# OpenTallas tools/mem_compiler/ucie_pma_gen.py: HBM host UCIe analog PMA ABSTRACT ot_ucie_pma_rxm (assumed footprint/timing)
VERSION 5.7 ;
BUSBITCHARS "[]" ;
DIVIDERCHAR "/" ;
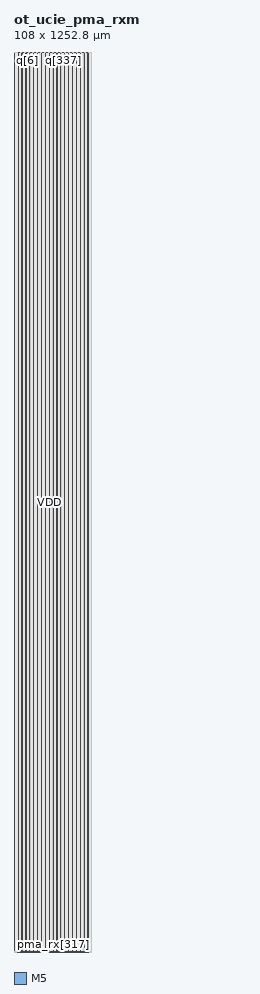
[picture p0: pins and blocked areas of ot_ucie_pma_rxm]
MACRO ot_ucie_pma_rxm
  FOREIGN ot_ucie_pma_rxm 0 0 ;
  SYMMETRY X Y ;
  SIZE 108.000 BY 1252.800 ;
  CLASS BLOCK ;
  PIN pma_rck
    DIRECTION INPUT ;
    USE CLOCK ;
    SHAPE ABUTMENT ;
    PORT
      LAYER M5 ;
      RECT 4.740 0.000 4.764 0.192 ;
    END
  END pma_rck
  PIN pma_rx[0]
    DIRECTION INPUT ;
    USE SIGNAL ;
    SHAPE ABUTMENT ;
    PORT
      LAYER M5 ;
      RECT 4.932 0.000 4.956 0.192 ;
    END
  END pma_rx[0]
  PIN pma_rx[1]
    DIRECTION INPUT ;
    USE SIGNAL ;
    SHAPE ABUTMENT ;
    PORT
      LAYER M5 ;
      RECT 5.124 0.000 5.148 0.192 ;
    END
  END pma_rx[1]
  PIN pma_rx[2]
    DIRECTION INPUT ;
    USE SIGNAL ;
    SHAPE ABUTMENT ;
    PORT
      LAYER M5 ;
      RECT 5.316 0.000 5.340 0.192 ;
    END
  END pma_rx[2]
  PIN pma_rx[3]
    DIRECTION INPUT ;
    USE SIGNAL ;
    SHAPE ABUTMENT ;
    PORT
      LAYER M5 ;
      RECT 5.508 0.000 5.532 0.192 ;
    END
  END pma_rx[3]
  PIN pma_rx[4]
    DIRECTION INPUT ;
    USE SIGNAL ;
    SHAPE ABUTMENT ;
    PORT
      LAYER M5 ;
      RECT 5.700 0.000 5.724 0.192 ;
    END
  END pma_rx[4]
  PIN pma_rx[5]
    DIRECTION INPUT ;
    USE SIGNAL ;
    SHAPE ABUTMENT ;
    PORT
      LAYER M5 ;
      RECT 5.892 0.000 5.916 0.192 ;
    END
  END pma_rx[5]
  PIN pma_rx[6]
    DIRECTION INPUT ;
    USE SIGNAL ;
    SHAPE ABUTMENT ;
    PORT
      LAYER M5 ;
      RECT 6.084 0.000 6.108 0.192 ;
    END
  END pma_rx[6]
  PIN pma_rx[7]
    DIRECTION INPUT ;
    USE SIGNAL ;
    SHAPE ABUTMENT ;
    PORT
      LAYER M5 ;
      RECT 6.276 0.000 6.300 0.192 ;
    END
  END pma_rx[7]
  PIN pma_rx[8]
    DIRECTION INPUT ;
    USE SIGNAL ;
    SHAPE ABUTMENT ;
    PORT
      LAYER M5 ;
      RECT 6.468 0.000 6.492 0.192 ;
    END
  END pma_rx[8]
  PIN pma_rx[9]
    DIRECTION INPUT ;
    USE SIGNAL ;
    SHAPE ABUTMENT ;
    PORT
      LAYER M5 ;
      RECT 6.660 0.000 6.684 0.192 ;
    END
  END pma_rx[9]
  PIN pma_rx[10]
    DIRECTION INPUT ;
    USE SIGNAL ;
    SHAPE ABUTMENT ;
    PORT
      LAYER M5 ;
      RECT 6.852 0.000 6.876 0.192 ;
    END
  END pma_rx[10]
  PIN pma_rx[11]
    DIRECTION INPUT ;
    USE SIGNAL ;
    SHAPE ABUTMENT ;
    PORT
      LAYER M5 ;
      RECT 7.044 0.000 7.068 0.192 ;
    END
  END pma_rx[11]
  PIN pma_rx[12]
    DIRECTION INPUT ;
    USE SIGNAL ;
    SHAPE ABUTMENT ;
    PORT
      LAYER M5 ;
      RECT 7.236 0.000 7.260 0.192 ;
    END
  END pma_rx[12]
  PIN pma_rx[13]
    DIRECTION INPUT ;
    USE SIGNAL ;
    SHAPE ABUTMENT ;
    PORT
      LAYER M5 ;
      RECT 7.428 0.000 7.452 0.192 ;
    END
  END pma_rx[13]
  PIN pma_rx[14]
    DIRECTION INPUT ;
    USE SIGNAL ;
    SHAPE ABUTMENT ;
    PORT
      LAYER M5 ;
      RECT 7.620 0.000 7.644 0.192 ;
    END
  END pma_rx[14]
  PIN pma_rx[15]
    DIRECTION INPUT ;
    USE SIGNAL ;
    SHAPE ABUTMENT ;
    PORT
      LAYER M5 ;
      RECT 7.812 0.000 7.836 0.192 ;
    END
  END pma_rx[15]
  PIN pma_rx[16]
    DIRECTION INPUT ;
    USE SIGNAL ;
    SHAPE ABUTMENT ;
    PORT
      LAYER M5 ;
      RECT 8.004 0.000 8.028 0.192 ;
    END
  END pma_rx[16]
  PIN pma_rx[17]
    DIRECTION INPUT ;
    USE SIGNAL ;
    SHAPE ABUTMENT ;
    PORT
      LAYER M5 ;
      RECT 8.196 0.000 8.220 0.192 ;
    END
  END pma_rx[17]
  PIN pma_rx[18]
    DIRECTION INPUT ;
    USE SIGNAL ;
    SHAPE ABUTMENT ;
    PORT
      LAYER M5 ;
      RECT 8.388 0.000 8.412 0.192 ;
    END
  END pma_rx[18]
  PIN pma_rx[19]
    DIRECTION INPUT ;
    USE SIGNAL ;
    SHAPE ABUTMENT ;
    PORT
      LAYER M5 ;
      RECT 8.580 0.000 8.604 0.192 ;
    END
  END pma_rx[19]
  PIN pma_rx[20]
    DIRECTION INPUT ;
    USE SIGNAL ;
    SHAPE ABUTMENT ;
    PORT
      LAYER M5 ;
      RECT 8.772 0.000 8.796 0.192 ;
    END
  END pma_rx[20]
  PIN pma_rx[21]
    DIRECTION INPUT ;
    USE SIGNAL ;
    SHAPE ABUTMENT ;
    PORT
      LAYER M5 ;
      RECT 8.964 0.000 8.988 0.192 ;
    END
  END pma_rx[21]
  PIN pma_rx[22]
    DIRECTION INPUT ;
    USE SIGNAL ;
    SHAPE ABUTMENT ;
    PORT
      LAYER M5 ;
      RECT 9.156 0.000 9.180 0.192 ;
    END
  END pma_rx[22]
  PIN pma_rx[23]
    DIRECTION INPUT ;
    USE SIGNAL ;
    SHAPE ABUTMENT ;
    PORT
      LAYER M5 ;
      RECT 9.348 0.000 9.372 0.192 ;
    END
  END pma_rx[23]
  PIN pma_rx[24]
    DIRECTION INPUT ;
    USE SIGNAL ;
    SHAPE ABUTMENT ;
    PORT
      LAYER M5 ;
      RECT 9.540 0.000 9.564 0.192 ;
    END
  END pma_rx[24]
  PIN pma_rx[25]
    DIRECTION INPUT ;
    USE SIGNAL ;
    SHAPE ABUTMENT ;
    PORT
      LAYER M5 ;
      RECT 9.732 0.000 9.756 0.192 ;
    END
  END pma_rx[25]
  PIN pma_rx[26]
    DIRECTION INPUT ;
    USE SIGNAL ;
    SHAPE ABUTMENT ;
    PORT
      LAYER M5 ;
      RECT 9.924 0.000 9.948 0.192 ;
    END
  END pma_rx[26]
  PIN pma_rx[27]
    DIRECTION INPUT ;
    USE SIGNAL ;
    SHAPE ABUTMENT ;
    PORT
      LAYER M5 ;
      RECT 10.116 0.000 10.140 0.192 ;
    END
  END pma_rx[27]
  PIN pma_rx[28]
    DIRECTION INPUT ;
    USE SIGNAL ;
    SHAPE ABUTMENT ;
    PORT
      LAYER M5 ;
      RECT 10.308 0.000 10.332 0.192 ;
    END
  END pma_rx[28]
  PIN pma_rx[29]
    DIRECTION INPUT ;
    USE SIGNAL ;
    SHAPE ABUTMENT ;
    PORT
      LAYER M5 ;
      RECT 10.500 0.000 10.524 0.192 ;
    END
  END pma_rx[29]
  PIN pma_rx[30]
    DIRECTION INPUT ;
    USE SIGNAL ;
    SHAPE ABUTMENT ;
    PORT
      LAYER M5 ;
      RECT 10.692 0.000 10.716 0.192 ;
    END
  END pma_rx[30]
  PIN pma_rx[31]
    DIRECTION INPUT ;
    USE SIGNAL ;
    SHAPE ABUTMENT ;
    PORT
      LAYER M5 ;
      RECT 10.884 0.000 10.908 0.192 ;
    END
  END pma_rx[31]
  PIN pma_rx[32]
    DIRECTION INPUT ;
    USE SIGNAL ;
    SHAPE ABUTMENT ;
    PORT
      LAYER M5 ;
      RECT 11.076 0.000 11.100 0.192 ;
    END
  END pma_rx[32]
  PIN pma_rx[33]
    DIRECTION INPUT ;
    USE SIGNAL ;
    SHAPE ABUTMENT ;
    PORT
      LAYER M5 ;
      RECT 11.268 0.000 11.292 0.192 ;
    END
  END pma_rx[33]
  PIN pma_rx[34]
    DIRECTION INPUT ;
    USE SIGNAL ;
    SHAPE ABUTMENT ;
    PORT
      LAYER M5 ;
      RECT 11.460 0.000 11.484 0.192 ;
    END
  END pma_rx[34]
  PIN pma_rx[35]
    DIRECTION INPUT ;
    USE SIGNAL ;
    SHAPE ABUTMENT ;
    PORT
      LAYER M5 ;
      RECT 11.652 0.000 11.676 0.192 ;
    END
  END pma_rx[35]
  PIN pma_rx[36]
    DIRECTION INPUT ;
    USE SIGNAL ;
    SHAPE ABUTMENT ;
    PORT
      LAYER M5 ;
      RECT 11.844 0.000 11.868 0.192 ;
    END
  END pma_rx[36]
  PIN pma_rx[37]
    DIRECTION INPUT ;
    USE SIGNAL ;
    SHAPE ABUTMENT ;
    PORT
      LAYER M5 ;
      RECT 12.036 0.000 12.060 0.192 ;
    END
  END pma_rx[37]
  PIN pma_rx[38]
    DIRECTION INPUT ;
    USE SIGNAL ;
    SHAPE ABUTMENT ;
    PORT
      LAYER M5 ;
      RECT 12.228 0.000 12.252 0.192 ;
    END
  END pma_rx[38]
  PIN pma_rx[39]
    DIRECTION INPUT ;
    USE SIGNAL ;
    SHAPE ABUTMENT ;
    PORT
      LAYER M5 ;
      RECT 12.420 0.000 12.444 0.192 ;
    END
  END pma_rx[39]
  PIN pma_rx[40]
    DIRECTION INPUT ;
    USE SIGNAL ;
    SHAPE ABUTMENT ;
    PORT
      LAYER M5 ;
      RECT 12.612 0.000 12.636 0.192 ;
    END
  END pma_rx[40]
  PIN pma_rx[41]
    DIRECTION INPUT ;
    USE SIGNAL ;
    SHAPE ABUTMENT ;
    PORT
      LAYER M5 ;
      RECT 12.804 0.000 12.828 0.192 ;
    END
  END pma_rx[41]
  PIN pma_rx[42]
    DIRECTION INPUT ;
    USE SIGNAL ;
    SHAPE ABUTMENT ;
    PORT
      LAYER M5 ;
      RECT 12.996 0.000 13.020 0.192 ;
    END
  END pma_rx[42]
  PIN pma_rx[43]
    DIRECTION INPUT ;
    USE SIGNAL ;
    SHAPE ABUTMENT ;
    PORT
      LAYER M5 ;
      RECT 13.188 0.000 13.212 0.192 ;
    END
  END pma_rx[43]
  PIN pma_rx[44]
    DIRECTION INPUT ;
    USE SIGNAL ;
    SHAPE ABUTMENT ;
    PORT
      LAYER M5 ;
      RECT 13.380 0.000 13.404 0.192 ;
    END
  END pma_rx[44]
  PIN pma_rx[45]
    DIRECTION INPUT ;
    USE SIGNAL ;
    SHAPE ABUTMENT ;
    PORT
      LAYER M5 ;
      RECT 13.572 0.000 13.596 0.192 ;
    END
  END pma_rx[45]
  PIN pma_rx[46]
    DIRECTION INPUT ;
    USE SIGNAL ;
    SHAPE ABUTMENT ;
    PORT
      LAYER M5 ;
      RECT 13.764 0.000 13.788 0.192 ;
    END
  END pma_rx[46]
  PIN pma_rx[47]
    DIRECTION INPUT ;
    USE SIGNAL ;
    SHAPE ABUTMENT ;
    PORT
      LAYER M5 ;
      RECT 13.956 0.000 13.980 0.192 ;
    END
  END pma_rx[47]
  PIN pma_rx[48]
    DIRECTION INPUT ;
    USE SIGNAL ;
    SHAPE ABUTMENT ;
    PORT
      LAYER M5 ;
      RECT 14.148 0.000 14.172 0.192 ;
    END
  END pma_rx[48]
  PIN pma_rx[49]
    DIRECTION INPUT ;
    USE SIGNAL ;
    SHAPE ABUTMENT ;
    PORT
      LAYER M5 ;
      RECT 14.340 0.000 14.364 0.192 ;
    END
  END pma_rx[49]
  PIN pma_rx[50]
    DIRECTION INPUT ;
    USE SIGNAL ;
    SHAPE ABUTMENT ;
    PORT
      LAYER M5 ;
      RECT 14.532 0.000 14.556 0.192 ;
    END
  END pma_rx[50]
  PIN pma_rx[51]
    DIRECTION INPUT ;
    USE SIGNAL ;
    SHAPE ABUTMENT ;
    PORT
      LAYER M5 ;
      RECT 14.724 0.000 14.748 0.192 ;
    END
  END pma_rx[51]
  PIN pma_rx[52]
    DIRECTION INPUT ;
    USE SIGNAL ;
    SHAPE ABUTMENT ;
    PORT
      LAYER M5 ;
      RECT 14.916 0.000 14.940 0.192 ;
    END
  END pma_rx[52]
  PIN pma_rx[53]
    DIRECTION INPUT ;
    USE SIGNAL ;
    SHAPE ABUTMENT ;
    PORT
      LAYER M5 ;
      RECT 15.108 0.000 15.132 0.192 ;
    END
  END pma_rx[53]
  PIN pma_rx[54]
    DIRECTION INPUT ;
    USE SIGNAL ;
    SHAPE ABUTMENT ;
    PORT
      LAYER M5 ;
      RECT 15.300 0.000 15.324 0.192 ;
    END
  END pma_rx[54]
  PIN pma_rx[55]
    DIRECTION INPUT ;
    USE SIGNAL ;
    SHAPE ABUTMENT ;
    PORT
      LAYER M5 ;
      RECT 15.492 0.000 15.516 0.192 ;
    END
  END pma_rx[55]
  PIN pma_rx[56]
    DIRECTION INPUT ;
    USE SIGNAL ;
    SHAPE ABUTMENT ;
    PORT
      LAYER M5 ;
      RECT 15.684 0.000 15.708 0.192 ;
    END
  END pma_rx[56]
  PIN pma_rx[57]
    DIRECTION INPUT ;
    USE SIGNAL ;
    SHAPE ABUTMENT ;
    PORT
      LAYER M5 ;
      RECT 15.876 0.000 15.900 0.192 ;
    END
  END pma_rx[57]
  PIN pma_rx[58]
    DIRECTION INPUT ;
    USE SIGNAL ;
    SHAPE ABUTMENT ;
    PORT
      LAYER M5 ;
      RECT 16.068 0.000 16.092 0.192 ;
    END
  END pma_rx[58]
  PIN pma_rx[59]
    DIRECTION INPUT ;
    USE SIGNAL ;
    SHAPE ABUTMENT ;
    PORT
      LAYER M5 ;
      RECT 16.260 0.000 16.284 0.192 ;
    END
  END pma_rx[59]
  PIN pma_rx[60]
    DIRECTION INPUT ;
    USE SIGNAL ;
    SHAPE ABUTMENT ;
    PORT
      LAYER M5 ;
      RECT 16.452 0.000 16.476 0.192 ;
    END
  END pma_rx[60]
  PIN pma_rx[61]
    DIRECTION INPUT ;
    USE SIGNAL ;
    SHAPE ABUTMENT ;
    PORT
      LAYER M5 ;
      RECT 16.644 0.000 16.668 0.192 ;
    END
  END pma_rx[61]
  PIN pma_rx[62]
    DIRECTION INPUT ;
    USE SIGNAL ;
    SHAPE ABUTMENT ;
    PORT
      LAYER M5 ;
      RECT 16.836 0.000 16.860 0.192 ;
    END
  END pma_rx[62]
  PIN pma_rx[63]
    DIRECTION INPUT ;
    USE SIGNAL ;
    SHAPE ABUTMENT ;
    PORT
      LAYER M5 ;
      RECT 17.028 0.000 17.052 0.192 ;
    END
  END pma_rx[63]
  PIN pma_rx[64]
    DIRECTION INPUT ;
    USE SIGNAL ;
    SHAPE ABUTMENT ;
    PORT
      LAYER M5 ;
      RECT 17.220 0.000 17.244 0.192 ;
    END
  END pma_rx[64]
  PIN pma_rx[65]
    DIRECTION INPUT ;
    USE SIGNAL ;
    SHAPE ABUTMENT ;
    PORT
      LAYER M5 ;
      RECT 17.412 0.000 17.436 0.192 ;
    END
  END pma_rx[65]
  PIN pma_rx[66]
    DIRECTION INPUT ;
    USE SIGNAL ;
    SHAPE ABUTMENT ;
    PORT
      LAYER M5 ;
      RECT 17.604 0.000 17.628 0.192 ;
    END
  END pma_rx[66]
  PIN pma_rx[67]
    DIRECTION INPUT ;
    USE SIGNAL ;
    SHAPE ABUTMENT ;
    PORT
      LAYER M5 ;
      RECT 17.796 0.000 17.820 0.192 ;
    END
  END pma_rx[67]
  PIN pma_rx[68]
    DIRECTION INPUT ;
    USE SIGNAL ;
    SHAPE ABUTMENT ;
    PORT
      LAYER M5 ;
      RECT 17.988 0.000 18.012 0.192 ;
    END
  END pma_rx[68]
  PIN pma_rx[69]
    DIRECTION INPUT ;
    USE SIGNAL ;
    SHAPE ABUTMENT ;
    PORT
      LAYER M5 ;
      RECT 18.180 0.000 18.204 0.192 ;
    END
  END pma_rx[69]
  PIN pma_rx[70]
    DIRECTION INPUT ;
    USE SIGNAL ;
    SHAPE ABUTMENT ;
    PORT
      LAYER M5 ;
      RECT 18.372 0.000 18.396 0.192 ;
    END
  END pma_rx[70]
  PIN pma_rx[71]
    DIRECTION INPUT ;
    USE SIGNAL ;
    SHAPE ABUTMENT ;
    PORT
      LAYER M5 ;
      RECT 18.564 0.000 18.588 0.192 ;
    END
  END pma_rx[71]
  PIN pma_rx[72]
    DIRECTION INPUT ;
    USE SIGNAL ;
    SHAPE ABUTMENT ;
    PORT
      LAYER M5 ;
      RECT 18.756 0.000 18.780 0.192 ;
    END
  END pma_rx[72]
  PIN pma_rx[73]
    DIRECTION INPUT ;
    USE SIGNAL ;
    SHAPE ABUTMENT ;
    PORT
      LAYER M5 ;
      RECT 18.948 0.000 18.972 0.192 ;
    END
  END pma_rx[73]
  PIN pma_rx[74]
    DIRECTION INPUT ;
    USE SIGNAL ;
    SHAPE ABUTMENT ;
    PORT
      LAYER M5 ;
      RECT 19.140 0.000 19.164 0.192 ;
    END
  END pma_rx[74]
  PIN pma_rx[75]
    DIRECTION INPUT ;
    USE SIGNAL ;
    SHAPE ABUTMENT ;
    PORT
      LAYER M5 ;
      RECT 19.332 0.000 19.356 0.192 ;
    END
  END pma_rx[75]
  PIN pma_rx[76]
    DIRECTION INPUT ;
    USE SIGNAL ;
    SHAPE ABUTMENT ;
    PORT
      LAYER M5 ;
      RECT 19.524 0.000 19.548 0.192 ;
    END
  END pma_rx[76]
  PIN pma_rx[77]
    DIRECTION INPUT ;
    USE SIGNAL ;
    SHAPE ABUTMENT ;
    PORT
      LAYER M5 ;
      RECT 19.716 0.000 19.740 0.192 ;
    END
  END pma_rx[77]
  PIN pma_rx[78]
    DIRECTION INPUT ;
    USE SIGNAL ;
    SHAPE ABUTMENT ;
    PORT
      LAYER M5 ;
      RECT 19.908 0.000 19.932 0.192 ;
    END
  END pma_rx[78]
  PIN pma_rx[79]
    DIRECTION INPUT ;
    USE SIGNAL ;
    SHAPE ABUTMENT ;
    PORT
      LAYER M5 ;
      RECT 20.100 0.000 20.124 0.192 ;
    END
  END pma_rx[79]
  PIN pma_rx[80]
    DIRECTION INPUT ;
    USE SIGNAL ;
    SHAPE ABUTMENT ;
    PORT
      LAYER M5 ;
      RECT 20.292 0.000 20.316 0.192 ;
    END
  END pma_rx[80]
  PIN pma_rx[81]
    DIRECTION INPUT ;
    USE SIGNAL ;
    SHAPE ABUTMENT ;
    PORT
      LAYER M5 ;
      RECT 20.484 0.000 20.508 0.192 ;
    END
  END pma_rx[81]
  PIN pma_rx[82]
    DIRECTION INPUT ;
    USE SIGNAL ;
    SHAPE ABUTMENT ;
    PORT
      LAYER M5 ;
      RECT 20.676 0.000 20.700 0.192 ;
    END
  END pma_rx[82]
  PIN pma_rx[83]
    DIRECTION INPUT ;
    USE SIGNAL ;
    SHAPE ABUTMENT ;
    PORT
      LAYER M5 ;
      RECT 20.868 0.000 20.892 0.192 ;
    END
  END pma_rx[83]
  PIN pma_rx[84]
    DIRECTION INPUT ;
    USE SIGNAL ;
    SHAPE ABUTMENT ;
    PORT
      LAYER M5 ;
      RECT 21.060 0.000 21.084 0.192 ;
    END
  END pma_rx[84]
  PIN pma_rx[85]
    DIRECTION INPUT ;
    USE SIGNAL ;
    SHAPE ABUTMENT ;
    PORT
      LAYER M5 ;
      RECT 21.252 0.000 21.276 0.192 ;
    END
  END pma_rx[85]
  PIN pma_rx[86]
    DIRECTION INPUT ;
    USE SIGNAL ;
    SHAPE ABUTMENT ;
    PORT
      LAYER M5 ;
      RECT 21.444 0.000 21.468 0.192 ;
    END
  END pma_rx[86]
  PIN pma_rx[87]
    DIRECTION INPUT ;
    USE SIGNAL ;
    SHAPE ABUTMENT ;
    PORT
      LAYER M5 ;
      RECT 21.636 0.000 21.660 0.192 ;
    END
  END pma_rx[87]
  PIN pma_rx[88]
    DIRECTION INPUT ;
    USE SIGNAL ;
    SHAPE ABUTMENT ;
    PORT
      LAYER M5 ;
      RECT 21.828 0.000 21.852 0.192 ;
    END
  END pma_rx[88]
  PIN pma_rx[89]
    DIRECTION INPUT ;
    USE SIGNAL ;
    SHAPE ABUTMENT ;
    PORT
      LAYER M5 ;
      RECT 22.020 0.000 22.044 0.192 ;
    END
  END pma_rx[89]
  PIN pma_rx[90]
    DIRECTION INPUT ;
    USE SIGNAL ;
    SHAPE ABUTMENT ;
    PORT
      LAYER M5 ;
      RECT 22.212 0.000 22.236 0.192 ;
    END
  END pma_rx[90]
  PIN pma_rx[91]
    DIRECTION INPUT ;
    USE SIGNAL ;
    SHAPE ABUTMENT ;
    PORT
      LAYER M5 ;
      RECT 22.404 0.000 22.428 0.192 ;
    END
  END pma_rx[91]
  PIN pma_rx[92]
    DIRECTION INPUT ;
    USE SIGNAL ;
    SHAPE ABUTMENT ;
    PORT
      LAYER M5 ;
      RECT 22.596 0.000 22.620 0.192 ;
    END
  END pma_rx[92]
  PIN pma_rx[93]
    DIRECTION INPUT ;
    USE SIGNAL ;
    SHAPE ABUTMENT ;
    PORT
      LAYER M5 ;
      RECT 22.788 0.000 22.812 0.192 ;
    END
  END pma_rx[93]
  PIN pma_rx[94]
    DIRECTION INPUT ;
    USE SIGNAL ;
    SHAPE ABUTMENT ;
    PORT
      LAYER M5 ;
      RECT 22.980 0.000 23.004 0.192 ;
    END
  END pma_rx[94]
  PIN pma_rx[95]
    DIRECTION INPUT ;
    USE SIGNAL ;
    SHAPE ABUTMENT ;
    PORT
      LAYER M5 ;
      RECT 23.172 0.000 23.196 0.192 ;
    END
  END pma_rx[95]
  PIN pma_rx[96]
    DIRECTION INPUT ;
    USE SIGNAL ;
    SHAPE ABUTMENT ;
    PORT
      LAYER M5 ;
      RECT 23.364 0.000 23.388 0.192 ;
    END
  END pma_rx[96]
  PIN pma_rx[97]
    DIRECTION INPUT ;
    USE SIGNAL ;
    SHAPE ABUTMENT ;
    PORT
      LAYER M5 ;
      RECT 23.556 0.000 23.580 0.192 ;
    END
  END pma_rx[97]
  PIN pma_rx[98]
    DIRECTION INPUT ;
    USE SIGNAL ;
    SHAPE ABUTMENT ;
    PORT
      LAYER M5 ;
      RECT 23.748 0.000 23.772 0.192 ;
    END
  END pma_rx[98]
  PIN pma_rx[99]
    DIRECTION INPUT ;
    USE SIGNAL ;
    SHAPE ABUTMENT ;
    PORT
      LAYER M5 ;
      RECT 23.940 0.000 23.964 0.192 ;
    END
  END pma_rx[99]
  PIN pma_rx[100]
    DIRECTION INPUT ;
    USE SIGNAL ;
    SHAPE ABUTMENT ;
    PORT
      LAYER M5 ;
      RECT 24.132 0.000 24.156 0.192 ;
    END
  END pma_rx[100]
  PIN pma_rx[101]
    DIRECTION INPUT ;
    USE SIGNAL ;
    SHAPE ABUTMENT ;
    PORT
      LAYER M5 ;
      RECT 24.324 0.000 24.348 0.192 ;
    END
  END pma_rx[101]
  PIN pma_rx[102]
    DIRECTION INPUT ;
    USE SIGNAL ;
    SHAPE ABUTMENT ;
    PORT
      LAYER M5 ;
      RECT 24.516 0.000 24.540 0.192 ;
    END
  END pma_rx[102]
  PIN pma_rx[103]
    DIRECTION INPUT ;
    USE SIGNAL ;
    SHAPE ABUTMENT ;
    PORT
      LAYER M5 ;
      RECT 24.708 0.000 24.732 0.192 ;
    END
  END pma_rx[103]
  PIN pma_rx[104]
    DIRECTION INPUT ;
    USE SIGNAL ;
    SHAPE ABUTMENT ;
    PORT
      LAYER M5 ;
      RECT 24.900 0.000 24.924 0.192 ;
    END
  END pma_rx[104]
  PIN pma_rx[105]
    DIRECTION INPUT ;
    USE SIGNAL ;
    SHAPE ABUTMENT ;
    PORT
      LAYER M5 ;
      RECT 25.092 0.000 25.116 0.192 ;
    END
  END pma_rx[105]
  PIN pma_rx[106]
    DIRECTION INPUT ;
    USE SIGNAL ;
    SHAPE ABUTMENT ;
    PORT
      LAYER M5 ;
      RECT 25.284 0.000 25.308 0.192 ;
    END
  END pma_rx[106]
  PIN pma_rx[107]
    DIRECTION INPUT ;
    USE SIGNAL ;
    SHAPE ABUTMENT ;
    PORT
      LAYER M5 ;
      RECT 25.476 0.000 25.500 0.192 ;
    END
  END pma_rx[107]
  PIN pma_rx[108]
    DIRECTION INPUT ;
    USE SIGNAL ;
    SHAPE ABUTMENT ;
    PORT
      LAYER M5 ;
      RECT 25.668 0.000 25.692 0.192 ;
    END
  END pma_rx[108]
  PIN pma_rx[109]
    DIRECTION INPUT ;
    USE SIGNAL ;
    SHAPE ABUTMENT ;
    PORT
      LAYER M5 ;
      RECT 25.860 0.000 25.884 0.192 ;
    END
  END pma_rx[109]
  PIN pma_rx[110]
    DIRECTION INPUT ;
    USE SIGNAL ;
    SHAPE ABUTMENT ;
    PORT
      LAYER M5 ;
      RECT 26.052 0.000 26.076 0.192 ;
    END
  END pma_rx[110]
  PIN pma_rx[111]
    DIRECTION INPUT ;
    USE SIGNAL ;
    SHAPE ABUTMENT ;
    PORT
      LAYER M5 ;
      RECT 26.244 0.000 26.268 0.192 ;
    END
  END pma_rx[111]
  PIN pma_rx[112]
    DIRECTION INPUT ;
    USE SIGNAL ;
    SHAPE ABUTMENT ;
    PORT
      LAYER M5 ;
      RECT 26.436 0.000 26.460 0.192 ;
    END
  END pma_rx[112]
  PIN pma_rx[113]
    DIRECTION INPUT ;
    USE SIGNAL ;
    SHAPE ABUTMENT ;
    PORT
      LAYER M5 ;
      RECT 26.628 0.000 26.652 0.192 ;
    END
  END pma_rx[113]
  PIN pma_rx[114]
    DIRECTION INPUT ;
    USE SIGNAL ;
    SHAPE ABUTMENT ;
    PORT
      LAYER M5 ;
      RECT 26.820 0.000 26.844 0.192 ;
    END
  END pma_rx[114]
  PIN pma_rx[115]
    DIRECTION INPUT ;
    USE SIGNAL ;
    SHAPE ABUTMENT ;
    PORT
      LAYER M5 ;
      RECT 27.012 0.000 27.036 0.192 ;
    END
  END pma_rx[115]
  PIN pma_rx[116]
    DIRECTION INPUT ;
    USE SIGNAL ;
    SHAPE ABUTMENT ;
    PORT
      LAYER M5 ;
      RECT 27.204 0.000 27.228 0.192 ;
    END
  END pma_rx[116]
  PIN pma_rx[117]
    DIRECTION INPUT ;
    USE SIGNAL ;
    SHAPE ABUTMENT ;
    PORT
      LAYER M5 ;
      RECT 27.396 0.000 27.420 0.192 ;
    END
  END pma_rx[117]
  PIN pma_rx[118]
    DIRECTION INPUT ;
    USE SIGNAL ;
    SHAPE ABUTMENT ;
    PORT
      LAYER M5 ;
      RECT 27.588 0.000 27.612 0.192 ;
    END
  END pma_rx[118]
  PIN pma_rx[119]
    DIRECTION INPUT ;
    USE SIGNAL ;
    SHAPE ABUTMENT ;
    PORT
      LAYER M5 ;
      RECT 27.780 0.000 27.804 0.192 ;
    END
  END pma_rx[119]
  PIN pma_rx[120]
    DIRECTION INPUT ;
    USE SIGNAL ;
    SHAPE ABUTMENT ;
    PORT
      LAYER M5 ;
      RECT 27.972 0.000 27.996 0.192 ;
    END
  END pma_rx[120]
  PIN pma_rx[121]
    DIRECTION INPUT ;
    USE SIGNAL ;
    SHAPE ABUTMENT ;
    PORT
      LAYER M5 ;
      RECT 28.164 0.000 28.188 0.192 ;
    END
  END pma_rx[121]
  PIN pma_rx[122]
    DIRECTION INPUT ;
    USE SIGNAL ;
    SHAPE ABUTMENT ;
    PORT
      LAYER M5 ;
      RECT 28.356 0.000 28.380 0.192 ;
    END
  END pma_rx[122]
  PIN pma_rx[123]
    DIRECTION INPUT ;
    USE SIGNAL ;
    SHAPE ABUTMENT ;
    PORT
      LAYER M5 ;
      RECT 28.548 0.000 28.572 0.192 ;
    END
  END pma_rx[123]
  PIN pma_rx[124]
    DIRECTION INPUT ;
    USE SIGNAL ;
    SHAPE ABUTMENT ;
    PORT
      LAYER M5 ;
      RECT 28.740 0.000 28.764 0.192 ;
    END
  END pma_rx[124]
  PIN pma_rx[125]
    DIRECTION INPUT ;
    USE SIGNAL ;
    SHAPE ABUTMENT ;
    PORT
      LAYER M5 ;
      RECT 28.932 0.000 28.956 0.192 ;
    END
  END pma_rx[125]
  PIN pma_rx[126]
    DIRECTION INPUT ;
    USE SIGNAL ;
    SHAPE ABUTMENT ;
    PORT
      LAYER M5 ;
      RECT 29.124 0.000 29.148 0.192 ;
    END
  END pma_rx[126]
  PIN pma_rx[127]
    DIRECTION INPUT ;
    USE SIGNAL ;
    SHAPE ABUTMENT ;
    PORT
      LAYER M5 ;
      RECT 29.316 0.000 29.340 0.192 ;
    END
  END pma_rx[127]
  PIN pma_rx[128]
    DIRECTION INPUT ;
    USE SIGNAL ;
    SHAPE ABUTMENT ;
    PORT
      LAYER M5 ;
      RECT 29.508 0.000 29.532 0.192 ;
    END
  END pma_rx[128]
  PIN pma_rx[129]
    DIRECTION INPUT ;
    USE SIGNAL ;
    SHAPE ABUTMENT ;
    PORT
      LAYER M5 ;
      RECT 29.700 0.000 29.724 0.192 ;
    END
  END pma_rx[129]
  PIN pma_rx[130]
    DIRECTION INPUT ;
    USE SIGNAL ;
    SHAPE ABUTMENT ;
    PORT
      LAYER M5 ;
      RECT 29.892 0.000 29.916 0.192 ;
    END
  END pma_rx[130]
  PIN pma_rx[131]
    DIRECTION INPUT ;
    USE SIGNAL ;
    SHAPE ABUTMENT ;
    PORT
      LAYER M5 ;
      RECT 30.084 0.000 30.108 0.192 ;
    END
  END pma_rx[131]
  PIN pma_rx[132]
    DIRECTION INPUT ;
    USE SIGNAL ;
    SHAPE ABUTMENT ;
    PORT
      LAYER M5 ;
      RECT 30.276 0.000 30.300 0.192 ;
    END
  END pma_rx[132]
  PIN pma_rx[133]
    DIRECTION INPUT ;
    USE SIGNAL ;
    SHAPE ABUTMENT ;
    PORT
      LAYER M5 ;
      RECT 30.468 0.000 30.492 0.192 ;
    END
  END pma_rx[133]
  PIN pma_rx[134]
    DIRECTION INPUT ;
    USE SIGNAL ;
    SHAPE ABUTMENT ;
    PORT
      LAYER M5 ;
      RECT 30.660 0.000 30.684 0.192 ;
    END
  END pma_rx[134]
  PIN pma_rx[135]
    DIRECTION INPUT ;
    USE SIGNAL ;
    SHAPE ABUTMENT ;
    PORT
      LAYER M5 ;
      RECT 30.852 0.000 30.876 0.192 ;
    END
  END pma_rx[135]
  PIN pma_rx[136]
    DIRECTION INPUT ;
    USE SIGNAL ;
    SHAPE ABUTMENT ;
    PORT
      LAYER M5 ;
      RECT 31.044 0.000 31.068 0.192 ;
    END
  END pma_rx[136]
  PIN pma_rx[137]
    DIRECTION INPUT ;
    USE SIGNAL ;
    SHAPE ABUTMENT ;
    PORT
      LAYER M5 ;
      RECT 31.236 0.000 31.260 0.192 ;
    END
  END pma_rx[137]
  PIN pma_rx[138]
    DIRECTION INPUT ;
    USE SIGNAL ;
    SHAPE ABUTMENT ;
    PORT
      LAYER M5 ;
      RECT 31.428 0.000 31.452 0.192 ;
    END
  END pma_rx[138]
  PIN pma_rx[139]
    DIRECTION INPUT ;
    USE SIGNAL ;
    SHAPE ABUTMENT ;
    PORT
      LAYER M5 ;
      RECT 31.620 0.000 31.644 0.192 ;
    END
  END pma_rx[139]
  PIN pma_rx[140]
    DIRECTION INPUT ;
    USE SIGNAL ;
    SHAPE ABUTMENT ;
    PORT
      LAYER M5 ;
      RECT 31.812 0.000 31.836 0.192 ;
    END
  END pma_rx[140]
  PIN pma_rx[141]
    DIRECTION INPUT ;
    USE SIGNAL ;
    SHAPE ABUTMENT ;
    PORT
      LAYER M5 ;
      RECT 32.004 0.000 32.028 0.192 ;
    END
  END pma_rx[141]
  PIN pma_rx[142]
    DIRECTION INPUT ;
    USE SIGNAL ;
    SHAPE ABUTMENT ;
    PORT
      LAYER M5 ;
      RECT 32.196 0.000 32.220 0.192 ;
    END
  END pma_rx[142]
  PIN pma_rx[143]
    DIRECTION INPUT ;
    USE SIGNAL ;
    SHAPE ABUTMENT ;
    PORT
      LAYER M5 ;
      RECT 32.388 0.000 32.412 0.192 ;
    END
  END pma_rx[143]
  PIN pma_rx[144]
    DIRECTION INPUT ;
    USE SIGNAL ;
    SHAPE ABUTMENT ;
    PORT
      LAYER M5 ;
      RECT 32.580 0.000 32.604 0.192 ;
    END
  END pma_rx[144]
  PIN pma_rx[145]
    DIRECTION INPUT ;
    USE SIGNAL ;
    SHAPE ABUTMENT ;
    PORT
      LAYER M5 ;
      RECT 32.772 0.000 32.796 0.192 ;
    END
  END pma_rx[145]
  PIN pma_rx[146]
    DIRECTION INPUT ;
    USE SIGNAL ;
    SHAPE ABUTMENT ;
    PORT
      LAYER M5 ;
      RECT 32.964 0.000 32.988 0.192 ;
    END
  END pma_rx[146]
  PIN pma_rx[147]
    DIRECTION INPUT ;
    USE SIGNAL ;
    SHAPE ABUTMENT ;
    PORT
      LAYER M5 ;
      RECT 33.156 0.000 33.180 0.192 ;
    END
  END pma_rx[147]
  PIN pma_rx[148]
    DIRECTION INPUT ;
    USE SIGNAL ;
    SHAPE ABUTMENT ;
    PORT
      LAYER M5 ;
      RECT 33.348 0.000 33.372 0.192 ;
    END
  END pma_rx[148]
  PIN pma_rx[149]
    DIRECTION INPUT ;
    USE SIGNAL ;
    SHAPE ABUTMENT ;
    PORT
      LAYER M5 ;
      RECT 33.540 0.000 33.564 0.192 ;
    END
  END pma_rx[149]
  PIN pma_rx[150]
    DIRECTION INPUT ;
    USE SIGNAL ;
    SHAPE ABUTMENT ;
    PORT
      LAYER M5 ;
      RECT 33.732 0.000 33.756 0.192 ;
    END
  END pma_rx[150]
  PIN pma_rx[151]
    DIRECTION INPUT ;
    USE SIGNAL ;
    SHAPE ABUTMENT ;
    PORT
      LAYER M5 ;
      RECT 33.924 0.000 33.948 0.192 ;
    END
  END pma_rx[151]
  PIN pma_rx[152]
    DIRECTION INPUT ;
    USE SIGNAL ;
    SHAPE ABUTMENT ;
    PORT
      LAYER M5 ;
      RECT 34.116 0.000 34.140 0.192 ;
    END
  END pma_rx[152]
  PIN pma_rx[153]
    DIRECTION INPUT ;
    USE SIGNAL ;
    SHAPE ABUTMENT ;
    PORT
      LAYER M5 ;
      RECT 34.308 0.000 34.332 0.192 ;
    END
  END pma_rx[153]
  PIN pma_rx[154]
    DIRECTION INPUT ;
    USE SIGNAL ;
    SHAPE ABUTMENT ;
    PORT
      LAYER M5 ;
      RECT 34.500 0.000 34.524 0.192 ;
    END
  END pma_rx[154]
  PIN pma_rx[155]
    DIRECTION INPUT ;
    USE SIGNAL ;
    SHAPE ABUTMENT ;
    PORT
      LAYER M5 ;
      RECT 34.692 0.000 34.716 0.192 ;
    END
  END pma_rx[155]
  PIN pma_rx[156]
    DIRECTION INPUT ;
    USE SIGNAL ;
    SHAPE ABUTMENT ;
    PORT
      LAYER M5 ;
      RECT 34.884 0.000 34.908 0.192 ;
    END
  END pma_rx[156]
  PIN pma_rx[157]
    DIRECTION INPUT ;
    USE SIGNAL ;
    SHAPE ABUTMENT ;
    PORT
      LAYER M5 ;
      RECT 35.076 0.000 35.100 0.192 ;
    END
  END pma_rx[157]
  PIN pma_rx[158]
    DIRECTION INPUT ;
    USE SIGNAL ;
    SHAPE ABUTMENT ;
    PORT
      LAYER M5 ;
      RECT 35.268 0.000 35.292 0.192 ;
    END
  END pma_rx[158]
  PIN pma_rx[159]
    DIRECTION INPUT ;
    USE SIGNAL ;
    SHAPE ABUTMENT ;
    PORT
      LAYER M5 ;
      RECT 35.460 0.000 35.484 0.192 ;
    END
  END pma_rx[159]
  PIN pma_rx[160]
    DIRECTION INPUT ;
    USE SIGNAL ;
    SHAPE ABUTMENT ;
    PORT
      LAYER M5 ;
      RECT 35.652 0.000 35.676 0.192 ;
    END
  END pma_rx[160]
  PIN pma_rx[161]
    DIRECTION INPUT ;
    USE SIGNAL ;
    SHAPE ABUTMENT ;
    PORT
      LAYER M5 ;
      RECT 35.844 0.000 35.868 0.192 ;
    END
  END pma_rx[161]
  PIN pma_rx[162]
    DIRECTION INPUT ;
    USE SIGNAL ;
    SHAPE ABUTMENT ;
    PORT
      LAYER M5 ;
      RECT 36.036 0.000 36.060 0.192 ;
    END
  END pma_rx[162]
  PIN pma_rx[163]
    DIRECTION INPUT ;
    USE SIGNAL ;
    SHAPE ABUTMENT ;
    PORT
      LAYER M5 ;
      RECT 36.228 0.000 36.252 0.192 ;
    END
  END pma_rx[163]
  PIN pma_rx[164]
    DIRECTION INPUT ;
    USE SIGNAL ;
    SHAPE ABUTMENT ;
    PORT
      LAYER M5 ;
      RECT 36.420 0.000 36.444 0.192 ;
    END
  END pma_rx[164]
  PIN pma_rx[165]
    DIRECTION INPUT ;
    USE SIGNAL ;
    SHAPE ABUTMENT ;
    PORT
      LAYER M5 ;
      RECT 36.612 0.000 36.636 0.192 ;
    END
  END pma_rx[165]
  PIN pma_rx[166]
    DIRECTION INPUT ;
    USE SIGNAL ;
    SHAPE ABUTMENT ;
    PORT
      LAYER M5 ;
      RECT 36.804 0.000 36.828 0.192 ;
    END
  END pma_rx[166]
  PIN pma_rx[167]
    DIRECTION INPUT ;
    USE SIGNAL ;
    SHAPE ABUTMENT ;
    PORT
      LAYER M5 ;
      RECT 36.996 0.000 37.020 0.192 ;
    END
  END pma_rx[167]
  PIN pma_rx[168]
    DIRECTION INPUT ;
    USE SIGNAL ;
    SHAPE ABUTMENT ;
    PORT
      LAYER M5 ;
      RECT 37.188 0.000 37.212 0.192 ;
    END
  END pma_rx[168]
  PIN pma_rx[169]
    DIRECTION INPUT ;
    USE SIGNAL ;
    SHAPE ABUTMENT ;
    PORT
      LAYER M5 ;
      RECT 37.380 0.000 37.404 0.192 ;
    END
  END pma_rx[169]
  PIN pma_rx[170]
    DIRECTION INPUT ;
    USE SIGNAL ;
    SHAPE ABUTMENT ;
    PORT
      LAYER M5 ;
      RECT 37.572 0.000 37.596 0.192 ;
    END
  END pma_rx[170]
  PIN pma_rx[171]
    DIRECTION INPUT ;
    USE SIGNAL ;
    SHAPE ABUTMENT ;
    PORT
      LAYER M5 ;
      RECT 37.764 0.000 37.788 0.192 ;
    END
  END pma_rx[171]
  PIN pma_rx[172]
    DIRECTION INPUT ;
    USE SIGNAL ;
    SHAPE ABUTMENT ;
    PORT
      LAYER M5 ;
      RECT 37.956 0.000 37.980 0.192 ;
    END
  END pma_rx[172]
  PIN pma_rx[173]
    DIRECTION INPUT ;
    USE SIGNAL ;
    SHAPE ABUTMENT ;
    PORT
      LAYER M5 ;
      RECT 38.148 0.000 38.172 0.192 ;
    END
  END pma_rx[173]
  PIN pma_rx[174]
    DIRECTION INPUT ;
    USE SIGNAL ;
    SHAPE ABUTMENT ;
    PORT
      LAYER M5 ;
      RECT 38.340 0.000 38.364 0.192 ;
    END
  END pma_rx[174]
  PIN pma_rx[175]
    DIRECTION INPUT ;
    USE SIGNAL ;
    SHAPE ABUTMENT ;
    PORT
      LAYER M5 ;
      RECT 38.532 0.000 38.556 0.192 ;
    END
  END pma_rx[175]
  PIN pma_rx[176]
    DIRECTION INPUT ;
    USE SIGNAL ;
    SHAPE ABUTMENT ;
    PORT
      LAYER M5 ;
      RECT 38.724 0.000 38.748 0.192 ;
    END
  END pma_rx[176]
  PIN pma_rx[177]
    DIRECTION INPUT ;
    USE SIGNAL ;
    SHAPE ABUTMENT ;
    PORT
      LAYER M5 ;
      RECT 38.916 0.000 38.940 0.192 ;
    END
  END pma_rx[177]
  PIN pma_rx[178]
    DIRECTION INPUT ;
    USE SIGNAL ;
    SHAPE ABUTMENT ;
    PORT
      LAYER M5 ;
      RECT 39.108 0.000 39.132 0.192 ;
    END
  END pma_rx[178]
  PIN pma_rx[179]
    DIRECTION INPUT ;
    USE SIGNAL ;
    SHAPE ABUTMENT ;
    PORT
      LAYER M5 ;
      RECT 39.300 0.000 39.324 0.192 ;
    END
  END pma_rx[179]
  PIN pma_rx[180]
    DIRECTION INPUT ;
    USE SIGNAL ;
    SHAPE ABUTMENT ;
    PORT
      LAYER M5 ;
      RECT 39.492 0.000 39.516 0.192 ;
    END
  END pma_rx[180]
  PIN pma_rx[181]
    DIRECTION INPUT ;
    USE SIGNAL ;
    SHAPE ABUTMENT ;
    PORT
      LAYER M5 ;
      RECT 39.684 0.000 39.708 0.192 ;
    END
  END pma_rx[181]
  PIN pma_rx[182]
    DIRECTION INPUT ;
    USE SIGNAL ;
    SHAPE ABUTMENT ;
    PORT
      LAYER M5 ;
      RECT 39.876 0.000 39.900 0.192 ;
    END
  END pma_rx[182]
  PIN pma_rx[183]
    DIRECTION INPUT ;
    USE SIGNAL ;
    SHAPE ABUTMENT ;
    PORT
      LAYER M5 ;
      RECT 40.068 0.000 40.092 0.192 ;
    END
  END pma_rx[183]
  PIN pma_rx[184]
    DIRECTION INPUT ;
    USE SIGNAL ;
    SHAPE ABUTMENT ;
    PORT
      LAYER M5 ;
      RECT 40.260 0.000 40.284 0.192 ;
    END
  END pma_rx[184]
  PIN pma_rx[185]
    DIRECTION INPUT ;
    USE SIGNAL ;
    SHAPE ABUTMENT ;
    PORT
      LAYER M5 ;
      RECT 40.452 0.000 40.476 0.192 ;
    END
  END pma_rx[185]
  PIN pma_rx[186]
    DIRECTION INPUT ;
    USE SIGNAL ;
    SHAPE ABUTMENT ;
    PORT
      LAYER M5 ;
      RECT 40.644 0.000 40.668 0.192 ;
    END
  END pma_rx[186]
  PIN pma_rx[187]
    DIRECTION INPUT ;
    USE SIGNAL ;
    SHAPE ABUTMENT ;
    PORT
      LAYER M5 ;
      RECT 40.836 0.000 40.860 0.192 ;
    END
  END pma_rx[187]
  PIN pma_rx[188]
    DIRECTION INPUT ;
    USE SIGNAL ;
    SHAPE ABUTMENT ;
    PORT
      LAYER M5 ;
      RECT 41.028 0.000 41.052 0.192 ;
    END
  END pma_rx[188]
  PIN pma_rx[189]
    DIRECTION INPUT ;
    USE SIGNAL ;
    SHAPE ABUTMENT ;
    PORT
      LAYER M5 ;
      RECT 41.220 0.000 41.244 0.192 ;
    END
  END pma_rx[189]
  PIN pma_rx[190]
    DIRECTION INPUT ;
    USE SIGNAL ;
    SHAPE ABUTMENT ;
    PORT
      LAYER M5 ;
      RECT 41.412 0.000 41.436 0.192 ;
    END
  END pma_rx[190]
  PIN pma_rx[191]
    DIRECTION INPUT ;
    USE SIGNAL ;
    SHAPE ABUTMENT ;
    PORT
      LAYER M5 ;
      RECT 41.604 0.000 41.628 0.192 ;
    END
  END pma_rx[191]
  PIN pma_rx[192]
    DIRECTION INPUT ;
    USE SIGNAL ;
    SHAPE ABUTMENT ;
    PORT
      LAYER M5 ;
      RECT 41.796 0.000 41.820 0.192 ;
    END
  END pma_rx[192]
  PIN pma_rx[193]
    DIRECTION INPUT ;
    USE SIGNAL ;
    SHAPE ABUTMENT ;
    PORT
      LAYER M5 ;
      RECT 41.988 0.000 42.012 0.192 ;
    END
  END pma_rx[193]
  PIN pma_rx[194]
    DIRECTION INPUT ;
    USE SIGNAL ;
    SHAPE ABUTMENT ;
    PORT
      LAYER M5 ;
      RECT 42.180 0.000 42.204 0.192 ;
    END
  END pma_rx[194]
  PIN pma_rx[195]
    DIRECTION INPUT ;
    USE SIGNAL ;
    SHAPE ABUTMENT ;
    PORT
      LAYER M5 ;
      RECT 42.372 0.000 42.396 0.192 ;
    END
  END pma_rx[195]
  PIN pma_rx[196]
    DIRECTION INPUT ;
    USE SIGNAL ;
    SHAPE ABUTMENT ;
    PORT
      LAYER M5 ;
      RECT 42.564 0.000 42.588 0.192 ;
    END
  END pma_rx[196]
  PIN pma_rx[197]
    DIRECTION INPUT ;
    USE SIGNAL ;
    SHAPE ABUTMENT ;
    PORT
      LAYER M5 ;
      RECT 42.756 0.000 42.780 0.192 ;
    END
  END pma_rx[197]
  PIN pma_rx[198]
    DIRECTION INPUT ;
    USE SIGNAL ;
    SHAPE ABUTMENT ;
    PORT
      LAYER M5 ;
      RECT 42.948 0.000 42.972 0.192 ;
    END
  END pma_rx[198]
  PIN pma_rx[199]
    DIRECTION INPUT ;
    USE SIGNAL ;
    SHAPE ABUTMENT ;
    PORT
      LAYER M5 ;
      RECT 43.140 0.000 43.164 0.192 ;
    END
  END pma_rx[199]
  PIN pma_rx[200]
    DIRECTION INPUT ;
    USE SIGNAL ;
    SHAPE ABUTMENT ;
    PORT
      LAYER M5 ;
      RECT 43.332 0.000 43.356 0.192 ;
    END
  END pma_rx[200]
  PIN pma_rx[201]
    DIRECTION INPUT ;
    USE SIGNAL ;
    SHAPE ABUTMENT ;
    PORT
      LAYER M5 ;
      RECT 43.524 0.000 43.548 0.192 ;
    END
  END pma_rx[201]
  PIN pma_rx[202]
    DIRECTION INPUT ;
    USE SIGNAL ;
    SHAPE ABUTMENT ;
    PORT
      LAYER M5 ;
      RECT 43.716 0.000 43.740 0.192 ;
    END
  END pma_rx[202]
  PIN pma_rx[203]
    DIRECTION INPUT ;
    USE SIGNAL ;
    SHAPE ABUTMENT ;
    PORT
      LAYER M5 ;
      RECT 43.908 0.000 43.932 0.192 ;
    END
  END pma_rx[203]
  PIN pma_rx[204]
    DIRECTION INPUT ;
    USE SIGNAL ;
    SHAPE ABUTMENT ;
    PORT
      LAYER M5 ;
      RECT 44.100 0.000 44.124 0.192 ;
    END
  END pma_rx[204]
  PIN pma_rx[205]
    DIRECTION INPUT ;
    USE SIGNAL ;
    SHAPE ABUTMENT ;
    PORT
      LAYER M5 ;
      RECT 44.292 0.000 44.316 0.192 ;
    END
  END pma_rx[205]
  PIN pma_rx[206]
    DIRECTION INPUT ;
    USE SIGNAL ;
    SHAPE ABUTMENT ;
    PORT
      LAYER M5 ;
      RECT 44.484 0.000 44.508 0.192 ;
    END
  END pma_rx[206]
  PIN pma_rx[207]
    DIRECTION INPUT ;
    USE SIGNAL ;
    SHAPE ABUTMENT ;
    PORT
      LAYER M5 ;
      RECT 44.676 0.000 44.700 0.192 ;
    END
  END pma_rx[207]
  PIN pma_rx[208]
    DIRECTION INPUT ;
    USE SIGNAL ;
    SHAPE ABUTMENT ;
    PORT
      LAYER M5 ;
      RECT 44.868 0.000 44.892 0.192 ;
    END
  END pma_rx[208]
  PIN pma_rx[209]
    DIRECTION INPUT ;
    USE SIGNAL ;
    SHAPE ABUTMENT ;
    PORT
      LAYER M5 ;
      RECT 45.060 0.000 45.084 0.192 ;
    END
  END pma_rx[209]
  PIN pma_rx[210]
    DIRECTION INPUT ;
    USE SIGNAL ;
    SHAPE ABUTMENT ;
    PORT
      LAYER M5 ;
      RECT 45.252 0.000 45.276 0.192 ;
    END
  END pma_rx[210]
  PIN pma_rx[211]
    DIRECTION INPUT ;
    USE SIGNAL ;
    SHAPE ABUTMENT ;
    PORT
      LAYER M5 ;
      RECT 45.444 0.000 45.468 0.192 ;
    END
  END pma_rx[211]
  PIN pma_rx[212]
    DIRECTION INPUT ;
    USE SIGNAL ;
    SHAPE ABUTMENT ;
    PORT
      LAYER M5 ;
      RECT 45.636 0.000 45.660 0.192 ;
    END
  END pma_rx[212]
  PIN pma_rx[213]
    DIRECTION INPUT ;
    USE SIGNAL ;
    SHAPE ABUTMENT ;
    PORT
      LAYER M5 ;
      RECT 45.828 0.000 45.852 0.192 ;
    END
  END pma_rx[213]
  PIN pma_rx[214]
    DIRECTION INPUT ;
    USE SIGNAL ;
    SHAPE ABUTMENT ;
    PORT
      LAYER M5 ;
      RECT 46.020 0.000 46.044 0.192 ;
    END
  END pma_rx[214]
  PIN pma_rx[215]
    DIRECTION INPUT ;
    USE SIGNAL ;
    SHAPE ABUTMENT ;
    PORT
      LAYER M5 ;
      RECT 46.212 0.000 46.236 0.192 ;
    END
  END pma_rx[215]
  PIN pma_rx[216]
    DIRECTION INPUT ;
    USE SIGNAL ;
    SHAPE ABUTMENT ;
    PORT
      LAYER M5 ;
      RECT 46.404 0.000 46.428 0.192 ;
    END
  END pma_rx[216]
  PIN pma_rx[217]
    DIRECTION INPUT ;
    USE SIGNAL ;
    SHAPE ABUTMENT ;
    PORT
      LAYER M5 ;
      RECT 46.596 0.000 46.620 0.192 ;
    END
  END pma_rx[217]
  PIN pma_rx[218]
    DIRECTION INPUT ;
    USE SIGNAL ;
    SHAPE ABUTMENT ;
    PORT
      LAYER M5 ;
      RECT 46.788 0.000 46.812 0.192 ;
    END
  END pma_rx[218]
  PIN pma_rx[219]
    DIRECTION INPUT ;
    USE SIGNAL ;
    SHAPE ABUTMENT ;
    PORT
      LAYER M5 ;
      RECT 46.980 0.000 47.004 0.192 ;
    END
  END pma_rx[219]
  PIN pma_rx[220]
    DIRECTION INPUT ;
    USE SIGNAL ;
    SHAPE ABUTMENT ;
    PORT
      LAYER M5 ;
      RECT 47.172 0.000 47.196 0.192 ;
    END
  END pma_rx[220]
  PIN pma_rx[221]
    DIRECTION INPUT ;
    USE SIGNAL ;
    SHAPE ABUTMENT ;
    PORT
      LAYER M5 ;
      RECT 47.364 0.000 47.388 0.192 ;
    END
  END pma_rx[221]
  PIN pma_rx[222]
    DIRECTION INPUT ;
    USE SIGNAL ;
    SHAPE ABUTMENT ;
    PORT
      LAYER M5 ;
      RECT 47.556 0.000 47.580 0.192 ;
    END
  END pma_rx[222]
  PIN pma_rx[223]
    DIRECTION INPUT ;
    USE SIGNAL ;
    SHAPE ABUTMENT ;
    PORT
      LAYER M5 ;
      RECT 47.748 0.000 47.772 0.192 ;
    END
  END pma_rx[223]
  PIN pma_rx[224]
    DIRECTION INPUT ;
    USE SIGNAL ;
    SHAPE ABUTMENT ;
    PORT
      LAYER M5 ;
      RECT 47.940 0.000 47.964 0.192 ;
    END
  END pma_rx[224]
  PIN pma_rx[225]
    DIRECTION INPUT ;
    USE SIGNAL ;
    SHAPE ABUTMENT ;
    PORT
      LAYER M5 ;
      RECT 48.132 0.000 48.156 0.192 ;
    END
  END pma_rx[225]
  PIN pma_rx[226]
    DIRECTION INPUT ;
    USE SIGNAL ;
    SHAPE ABUTMENT ;
    PORT
      LAYER M5 ;
      RECT 48.324 0.000 48.348 0.192 ;
    END
  END pma_rx[226]
  PIN pma_rx[227]
    DIRECTION INPUT ;
    USE SIGNAL ;
    SHAPE ABUTMENT ;
    PORT
      LAYER M5 ;
      RECT 48.516 0.000 48.540 0.192 ;
    END
  END pma_rx[227]
  PIN pma_rx[228]
    DIRECTION INPUT ;
    USE SIGNAL ;
    SHAPE ABUTMENT ;
    PORT
      LAYER M5 ;
      RECT 48.708 0.000 48.732 0.192 ;
    END
  END pma_rx[228]
  PIN pma_rx[229]
    DIRECTION INPUT ;
    USE SIGNAL ;
    SHAPE ABUTMENT ;
    PORT
      LAYER M5 ;
      RECT 48.900 0.000 48.924 0.192 ;
    END
  END pma_rx[229]
  PIN pma_rx[230]
    DIRECTION INPUT ;
    USE SIGNAL ;
    SHAPE ABUTMENT ;
    PORT
      LAYER M5 ;
      RECT 49.092 0.000 49.116 0.192 ;
    END
  END pma_rx[230]
  PIN pma_rx[231]
    DIRECTION INPUT ;
    USE SIGNAL ;
    SHAPE ABUTMENT ;
    PORT
      LAYER M5 ;
      RECT 49.284 0.000 49.308 0.192 ;
    END
  END pma_rx[231]
  PIN pma_rx[232]
    DIRECTION INPUT ;
    USE SIGNAL ;
    SHAPE ABUTMENT ;
    PORT
      LAYER M5 ;
      RECT 49.476 0.000 49.500 0.192 ;
    END
  END pma_rx[232]
  PIN pma_rx[233]
    DIRECTION INPUT ;
    USE SIGNAL ;
    SHAPE ABUTMENT ;
    PORT
      LAYER M5 ;
      RECT 49.668 0.000 49.692 0.192 ;
    END
  END pma_rx[233]
  PIN pma_rx[234]
    DIRECTION INPUT ;
    USE SIGNAL ;
    SHAPE ABUTMENT ;
    PORT
      LAYER M5 ;
      RECT 49.860 0.000 49.884 0.192 ;
    END
  END pma_rx[234]
  PIN pma_rx[235]
    DIRECTION INPUT ;
    USE SIGNAL ;
    SHAPE ABUTMENT ;
    PORT
      LAYER M5 ;
      RECT 50.052 0.000 50.076 0.192 ;
    END
  END pma_rx[235]
  PIN pma_rx[236]
    DIRECTION INPUT ;
    USE SIGNAL ;
    SHAPE ABUTMENT ;
    PORT
      LAYER M5 ;
      RECT 50.244 0.000 50.268 0.192 ;
    END
  END pma_rx[236]
  PIN pma_rx[237]
    DIRECTION INPUT ;
    USE SIGNAL ;
    SHAPE ABUTMENT ;
    PORT
      LAYER M5 ;
      RECT 50.436 0.000 50.460 0.192 ;
    END
  END pma_rx[237]
  PIN pma_rx[238]
    DIRECTION INPUT ;
    USE SIGNAL ;
    SHAPE ABUTMENT ;
    PORT
      LAYER M5 ;
      RECT 50.628 0.000 50.652 0.192 ;
    END
  END pma_rx[238]
  PIN pma_rx[239]
    DIRECTION INPUT ;
    USE SIGNAL ;
    SHAPE ABUTMENT ;
    PORT
      LAYER M5 ;
      RECT 50.820 0.000 50.844 0.192 ;
    END
  END pma_rx[239]
  PIN pma_rx[240]
    DIRECTION INPUT ;
    USE SIGNAL ;
    SHAPE ABUTMENT ;
    PORT
      LAYER M5 ;
      RECT 51.012 0.000 51.036 0.192 ;
    END
  END pma_rx[240]
  PIN pma_rx[241]
    DIRECTION INPUT ;
    USE SIGNAL ;
    SHAPE ABUTMENT ;
    PORT
      LAYER M5 ;
      RECT 51.204 0.000 51.228 0.192 ;
    END
  END pma_rx[241]
  PIN pma_rx[242]
    DIRECTION INPUT ;
    USE SIGNAL ;
    SHAPE ABUTMENT ;
    PORT
      LAYER M5 ;
      RECT 51.396 0.000 51.420 0.192 ;
    END
  END pma_rx[242]
  PIN pma_rx[243]
    DIRECTION INPUT ;
    USE SIGNAL ;
    SHAPE ABUTMENT ;
    PORT
      LAYER M5 ;
      RECT 51.588 0.000 51.612 0.192 ;
    END
  END pma_rx[243]
  PIN pma_rx[244]
    DIRECTION INPUT ;
    USE SIGNAL ;
    SHAPE ABUTMENT ;
    PORT
      LAYER M5 ;
      RECT 51.780 0.000 51.804 0.192 ;
    END
  END pma_rx[244]
  PIN pma_rx[245]
    DIRECTION INPUT ;
    USE SIGNAL ;
    SHAPE ABUTMENT ;
    PORT
      LAYER M5 ;
      RECT 51.972 0.000 51.996 0.192 ;
    END
  END pma_rx[245]
  PIN pma_rx[246]
    DIRECTION INPUT ;
    USE SIGNAL ;
    SHAPE ABUTMENT ;
    PORT
      LAYER M5 ;
      RECT 52.164 0.000 52.188 0.192 ;
    END
  END pma_rx[246]
  PIN pma_rx[247]
    DIRECTION INPUT ;
    USE SIGNAL ;
    SHAPE ABUTMENT ;
    PORT
      LAYER M5 ;
      RECT 52.356 0.000 52.380 0.192 ;
    END
  END pma_rx[247]
  PIN pma_rx[248]
    DIRECTION INPUT ;
    USE SIGNAL ;
    SHAPE ABUTMENT ;
    PORT
      LAYER M5 ;
      RECT 52.548 0.000 52.572 0.192 ;
    END
  END pma_rx[248]
  PIN pma_rx[249]
    DIRECTION INPUT ;
    USE SIGNAL ;
    SHAPE ABUTMENT ;
    PORT
      LAYER M5 ;
      RECT 52.740 0.000 52.764 0.192 ;
    END
  END pma_rx[249]
  PIN pma_rx[250]
    DIRECTION INPUT ;
    USE SIGNAL ;
    SHAPE ABUTMENT ;
    PORT
      LAYER M5 ;
      RECT 52.932 0.000 52.956 0.192 ;
    END
  END pma_rx[250]
  PIN pma_rx[251]
    DIRECTION INPUT ;
    USE SIGNAL ;
    SHAPE ABUTMENT ;
    PORT
      LAYER M5 ;
      RECT 53.124 0.000 53.148 0.192 ;
    END
  END pma_rx[251]
  PIN pma_rx[252]
    DIRECTION INPUT ;
    USE SIGNAL ;
    SHAPE ABUTMENT ;
    PORT
      LAYER M5 ;
      RECT 53.316 0.000 53.340 0.192 ;
    END
  END pma_rx[252]
  PIN pma_rx[253]
    DIRECTION INPUT ;
    USE SIGNAL ;
    SHAPE ABUTMENT ;
    PORT
      LAYER M5 ;
      RECT 53.508 0.000 53.532 0.192 ;
    END
  END pma_rx[253]
  PIN pma_rx[254]
    DIRECTION INPUT ;
    USE SIGNAL ;
    SHAPE ABUTMENT ;
    PORT
      LAYER M5 ;
      RECT 53.700 0.000 53.724 0.192 ;
    END
  END pma_rx[254]
  PIN pma_rx[255]
    DIRECTION INPUT ;
    USE SIGNAL ;
    SHAPE ABUTMENT ;
    PORT
      LAYER M5 ;
      RECT 53.892 0.000 53.916 0.192 ;
    END
  END pma_rx[255]
  PIN pma_rx[256]
    DIRECTION INPUT ;
    USE SIGNAL ;
    SHAPE ABUTMENT ;
    PORT
      LAYER M5 ;
      RECT 54.084 0.000 54.108 0.192 ;
    END
  END pma_rx[256]
  PIN pma_rx[257]
    DIRECTION INPUT ;
    USE SIGNAL ;
    SHAPE ABUTMENT ;
    PORT
      LAYER M5 ;
      RECT 54.276 0.000 54.300 0.192 ;
    END
  END pma_rx[257]
  PIN pma_rx[258]
    DIRECTION INPUT ;
    USE SIGNAL ;
    SHAPE ABUTMENT ;
    PORT
      LAYER M5 ;
      RECT 54.468 0.000 54.492 0.192 ;
    END
  END pma_rx[258]
  PIN pma_rx[259]
    DIRECTION INPUT ;
    USE SIGNAL ;
    SHAPE ABUTMENT ;
    PORT
      LAYER M5 ;
      RECT 54.660 0.000 54.684 0.192 ;
    END
  END pma_rx[259]
  PIN pma_rx[260]
    DIRECTION INPUT ;
    USE SIGNAL ;
    SHAPE ABUTMENT ;
    PORT
      LAYER M5 ;
      RECT 54.852 0.000 54.876 0.192 ;
    END
  END pma_rx[260]
  PIN pma_rx[261]
    DIRECTION INPUT ;
    USE SIGNAL ;
    SHAPE ABUTMENT ;
    PORT
      LAYER M5 ;
      RECT 55.044 0.000 55.068 0.192 ;
    END
  END pma_rx[261]
  PIN pma_rx[262]
    DIRECTION INPUT ;
    USE SIGNAL ;
    SHAPE ABUTMENT ;
    PORT
      LAYER M5 ;
      RECT 55.236 0.000 55.260 0.192 ;
    END
  END pma_rx[262]
  PIN pma_rx[263]
    DIRECTION INPUT ;
    USE SIGNAL ;
    SHAPE ABUTMENT ;
    PORT
      LAYER M5 ;
      RECT 55.428 0.000 55.452 0.192 ;
    END
  END pma_rx[263]
  PIN pma_rx[264]
    DIRECTION INPUT ;
    USE SIGNAL ;
    SHAPE ABUTMENT ;
    PORT
      LAYER M5 ;
      RECT 55.620 0.000 55.644 0.192 ;
    END
  END pma_rx[264]
  PIN pma_rx[265]
    DIRECTION INPUT ;
    USE SIGNAL ;
    SHAPE ABUTMENT ;
    PORT
      LAYER M5 ;
      RECT 55.812 0.000 55.836 0.192 ;
    END
  END pma_rx[265]
  PIN pma_rx[266]
    DIRECTION INPUT ;
    USE SIGNAL ;
    SHAPE ABUTMENT ;
    PORT
      LAYER M5 ;
      RECT 56.004 0.000 56.028 0.192 ;
    END
  END pma_rx[266]
  PIN pma_rx[267]
    DIRECTION INPUT ;
    USE SIGNAL ;
    SHAPE ABUTMENT ;
    PORT
      LAYER M5 ;
      RECT 56.196 0.000 56.220 0.192 ;
    END
  END pma_rx[267]
  PIN pma_rx[268]
    DIRECTION INPUT ;
    USE SIGNAL ;
    SHAPE ABUTMENT ;
    PORT
      LAYER M5 ;
      RECT 56.388 0.000 56.412 0.192 ;
    END
  END pma_rx[268]
  PIN pma_rx[269]
    DIRECTION INPUT ;
    USE SIGNAL ;
    SHAPE ABUTMENT ;
    PORT
      LAYER M5 ;
      RECT 56.580 0.000 56.604 0.192 ;
    END
  END pma_rx[269]
  PIN pma_rx[270]
    DIRECTION INPUT ;
    USE SIGNAL ;
    SHAPE ABUTMENT ;
    PORT
      LAYER M5 ;
      RECT 56.772 0.000 56.796 0.192 ;
    END
  END pma_rx[270]
  PIN pma_rx[271]
    DIRECTION INPUT ;
    USE SIGNAL ;
    SHAPE ABUTMENT ;
    PORT
      LAYER M5 ;
      RECT 56.964 0.000 56.988 0.192 ;
    END
  END pma_rx[271]
  PIN pma_rx[272]
    DIRECTION INPUT ;
    USE SIGNAL ;
    SHAPE ABUTMENT ;
    PORT
      LAYER M5 ;
      RECT 57.156 0.000 57.180 0.192 ;
    END
  END pma_rx[272]
  PIN pma_rx[273]
    DIRECTION INPUT ;
    USE SIGNAL ;
    SHAPE ABUTMENT ;
    PORT
      LAYER M5 ;
      RECT 57.348 0.000 57.372 0.192 ;
    END
  END pma_rx[273]
  PIN pma_rx[274]
    DIRECTION INPUT ;
    USE SIGNAL ;
    SHAPE ABUTMENT ;
    PORT
      LAYER M5 ;
      RECT 57.540 0.000 57.564 0.192 ;
    END
  END pma_rx[274]
  PIN pma_rx[275]
    DIRECTION INPUT ;
    USE SIGNAL ;
    SHAPE ABUTMENT ;
    PORT
      LAYER M5 ;
      RECT 57.732 0.000 57.756 0.192 ;
    END
  END pma_rx[275]
  PIN pma_rx[276]
    DIRECTION INPUT ;
    USE SIGNAL ;
    SHAPE ABUTMENT ;
    PORT
      LAYER M5 ;
      RECT 57.924 0.000 57.948 0.192 ;
    END
  END pma_rx[276]
  PIN pma_rx[277]
    DIRECTION INPUT ;
    USE SIGNAL ;
    SHAPE ABUTMENT ;
    PORT
      LAYER M5 ;
      RECT 58.116 0.000 58.140 0.192 ;
    END
  END pma_rx[277]
  PIN pma_rx[278]
    DIRECTION INPUT ;
    USE SIGNAL ;
    SHAPE ABUTMENT ;
    PORT
      LAYER M5 ;
      RECT 58.308 0.000 58.332 0.192 ;
    END
  END pma_rx[278]
  PIN pma_rx[279]
    DIRECTION INPUT ;
    USE SIGNAL ;
    SHAPE ABUTMENT ;
    PORT
      LAYER M5 ;
      RECT 58.500 0.000 58.524 0.192 ;
    END
  END pma_rx[279]
  PIN pma_rx[280]
    DIRECTION INPUT ;
    USE SIGNAL ;
    SHAPE ABUTMENT ;
    PORT
      LAYER M5 ;
      RECT 58.692 0.000 58.716 0.192 ;
    END
  END pma_rx[280]
  PIN pma_rx[281]
    DIRECTION INPUT ;
    USE SIGNAL ;
    SHAPE ABUTMENT ;
    PORT
      LAYER M5 ;
      RECT 58.884 0.000 58.908 0.192 ;
    END
  END pma_rx[281]
  PIN pma_rx[282]
    DIRECTION INPUT ;
    USE SIGNAL ;
    SHAPE ABUTMENT ;
    PORT
      LAYER M5 ;
      RECT 59.076 0.000 59.100 0.192 ;
    END
  END pma_rx[282]
  PIN pma_rx[283]
    DIRECTION INPUT ;
    USE SIGNAL ;
    SHAPE ABUTMENT ;
    PORT
      LAYER M5 ;
      RECT 59.268 0.000 59.292 0.192 ;
    END
  END pma_rx[283]
  PIN pma_rx[284]
    DIRECTION INPUT ;
    USE SIGNAL ;
    SHAPE ABUTMENT ;
    PORT
      LAYER M5 ;
      RECT 59.460 0.000 59.484 0.192 ;
    END
  END pma_rx[284]
  PIN pma_rx[285]
    DIRECTION INPUT ;
    USE SIGNAL ;
    SHAPE ABUTMENT ;
    PORT
      LAYER M5 ;
      RECT 59.652 0.000 59.676 0.192 ;
    END
  END pma_rx[285]
  PIN pma_rx[286]
    DIRECTION INPUT ;
    USE SIGNAL ;
    SHAPE ABUTMENT ;
    PORT
      LAYER M5 ;
      RECT 59.844 0.000 59.868 0.192 ;
    END
  END pma_rx[286]
  PIN pma_rx[287]
    DIRECTION INPUT ;
    USE SIGNAL ;
    SHAPE ABUTMENT ;
    PORT
      LAYER M5 ;
      RECT 60.036 0.000 60.060 0.192 ;
    END
  END pma_rx[287]
  PIN pma_rx[288]
    DIRECTION INPUT ;
    USE SIGNAL ;
    SHAPE ABUTMENT ;
    PORT
      LAYER M5 ;
      RECT 60.228 0.000 60.252 0.192 ;
    END
  END pma_rx[288]
  PIN pma_rx[289]
    DIRECTION INPUT ;
    USE SIGNAL ;
    SHAPE ABUTMENT ;
    PORT
      LAYER M5 ;
      RECT 60.420 0.000 60.444 0.192 ;
    END
  END pma_rx[289]
  PIN pma_rx[290]
    DIRECTION INPUT ;
    USE SIGNAL ;
    SHAPE ABUTMENT ;
    PORT
      LAYER M5 ;
      RECT 60.612 0.000 60.636 0.192 ;
    END
  END pma_rx[290]
  PIN pma_rx[291]
    DIRECTION INPUT ;
    USE SIGNAL ;
    SHAPE ABUTMENT ;
    PORT
      LAYER M5 ;
      RECT 60.804 0.000 60.828 0.192 ;
    END
  END pma_rx[291]
  PIN pma_rx[292]
    DIRECTION INPUT ;
    USE SIGNAL ;
    SHAPE ABUTMENT ;
    PORT
      LAYER M5 ;
      RECT 60.996 0.000 61.020 0.192 ;
    END
  END pma_rx[292]
  PIN pma_rx[293]
    DIRECTION INPUT ;
    USE SIGNAL ;
    SHAPE ABUTMENT ;
    PORT
      LAYER M5 ;
      RECT 61.188 0.000 61.212 0.192 ;
    END
  END pma_rx[293]
  PIN pma_rx[294]
    DIRECTION INPUT ;
    USE SIGNAL ;
    SHAPE ABUTMENT ;
    PORT
      LAYER M5 ;
      RECT 61.380 0.000 61.404 0.192 ;
    END
  END pma_rx[294]
  PIN pma_rx[295]
    DIRECTION INPUT ;
    USE SIGNAL ;
    SHAPE ABUTMENT ;
    PORT
      LAYER M5 ;
      RECT 61.572 0.000 61.596 0.192 ;
    END
  END pma_rx[295]
  PIN pma_rx[296]
    DIRECTION INPUT ;
    USE SIGNAL ;
    SHAPE ABUTMENT ;
    PORT
      LAYER M5 ;
      RECT 61.764 0.000 61.788 0.192 ;
    END
  END pma_rx[296]
  PIN pma_rx[297]
    DIRECTION INPUT ;
    USE SIGNAL ;
    SHAPE ABUTMENT ;
    PORT
      LAYER M5 ;
      RECT 61.956 0.000 61.980 0.192 ;
    END
  END pma_rx[297]
  PIN pma_rx[298]
    DIRECTION INPUT ;
    USE SIGNAL ;
    SHAPE ABUTMENT ;
    PORT
      LAYER M5 ;
      RECT 62.148 0.000 62.172 0.192 ;
    END
  END pma_rx[298]
  PIN pma_rx[299]
    DIRECTION INPUT ;
    USE SIGNAL ;
    SHAPE ABUTMENT ;
    PORT
      LAYER M5 ;
      RECT 62.340 0.000 62.364 0.192 ;
    END
  END pma_rx[299]
  PIN pma_rx[300]
    DIRECTION INPUT ;
    USE SIGNAL ;
    SHAPE ABUTMENT ;
    PORT
      LAYER M5 ;
      RECT 62.532 0.000 62.556 0.192 ;
    END
  END pma_rx[300]
  PIN pma_rx[301]
    DIRECTION INPUT ;
    USE SIGNAL ;
    SHAPE ABUTMENT ;
    PORT
      LAYER M5 ;
      RECT 62.724 0.000 62.748 0.192 ;
    END
  END pma_rx[301]
  PIN pma_rx[302]
    DIRECTION INPUT ;
    USE SIGNAL ;
    SHAPE ABUTMENT ;
    PORT
      LAYER M5 ;
      RECT 62.916 0.000 62.940 0.192 ;
    END
  END pma_rx[302]
  PIN pma_rx[303]
    DIRECTION INPUT ;
    USE SIGNAL ;
    SHAPE ABUTMENT ;
    PORT
      LAYER M5 ;
      RECT 63.108 0.000 63.132 0.192 ;
    END
  END pma_rx[303]
  PIN pma_rx[304]
    DIRECTION INPUT ;
    USE SIGNAL ;
    SHAPE ABUTMENT ;
    PORT
      LAYER M5 ;
      RECT 63.300 0.000 63.324 0.192 ;
    END
  END pma_rx[304]
  PIN pma_rx[305]
    DIRECTION INPUT ;
    USE SIGNAL ;
    SHAPE ABUTMENT ;
    PORT
      LAYER M5 ;
      RECT 63.492 0.000 63.516 0.192 ;
    END
  END pma_rx[305]
  PIN pma_rx[306]
    DIRECTION INPUT ;
    USE SIGNAL ;
    SHAPE ABUTMENT ;
    PORT
      LAYER M5 ;
      RECT 63.684 0.000 63.708 0.192 ;
    END
  END pma_rx[306]
  PIN pma_rx[307]
    DIRECTION INPUT ;
    USE SIGNAL ;
    SHAPE ABUTMENT ;
    PORT
      LAYER M5 ;
      RECT 63.876 0.000 63.900 0.192 ;
    END
  END pma_rx[307]
  PIN pma_rx[308]
    DIRECTION INPUT ;
    USE SIGNAL ;
    SHAPE ABUTMENT ;
    PORT
      LAYER M5 ;
      RECT 64.068 0.000 64.092 0.192 ;
    END
  END pma_rx[308]
  PIN pma_rx[309]
    DIRECTION INPUT ;
    USE SIGNAL ;
    SHAPE ABUTMENT ;
    PORT
      LAYER M5 ;
      RECT 64.260 0.000 64.284 0.192 ;
    END
  END pma_rx[309]
  PIN pma_rx[310]
    DIRECTION INPUT ;
    USE SIGNAL ;
    SHAPE ABUTMENT ;
    PORT
      LAYER M5 ;
      RECT 64.452 0.000 64.476 0.192 ;
    END
  END pma_rx[310]
  PIN pma_rx[311]
    DIRECTION INPUT ;
    USE SIGNAL ;
    SHAPE ABUTMENT ;
    PORT
      LAYER M5 ;
      RECT 64.644 0.000 64.668 0.192 ;
    END
  END pma_rx[311]
  PIN pma_rx[312]
    DIRECTION INPUT ;
    USE SIGNAL ;
    SHAPE ABUTMENT ;
    PORT
      LAYER M5 ;
      RECT 64.836 0.000 64.860 0.192 ;
    END
  END pma_rx[312]
  PIN pma_rx[313]
    DIRECTION INPUT ;
    USE SIGNAL ;
    SHAPE ABUTMENT ;
    PORT
      LAYER M5 ;
      RECT 65.028 0.000 65.052 0.192 ;
    END
  END pma_rx[313]
  PIN pma_rx[314]
    DIRECTION INPUT ;
    USE SIGNAL ;
    SHAPE ABUTMENT ;
    PORT
      LAYER M5 ;
      RECT 65.220 0.000 65.244 0.192 ;
    END
  END pma_rx[314]
  PIN pma_rx[315]
    DIRECTION INPUT ;
    USE SIGNAL ;
    SHAPE ABUTMENT ;
    PORT
      LAYER M5 ;
      RECT 65.412 0.000 65.436 0.192 ;
    END
  END pma_rx[315]
  PIN pma_rx[316]
    DIRECTION INPUT ;
    USE SIGNAL ;
    SHAPE ABUTMENT ;
    PORT
      LAYER M5 ;
      RECT 65.604 0.000 65.628 0.192 ;
    END
  END pma_rx[316]
  PIN pma_rx[317]
    DIRECTION INPUT ;
    USE SIGNAL ;
    SHAPE ABUTMENT ;
    PORT
      LAYER M5 ;
      RECT 65.796 0.000 65.820 0.192 ;
    END
  END pma_rx[317]
  PIN pma_rx[318]
    DIRECTION INPUT ;
    USE SIGNAL ;
    SHAPE ABUTMENT ;
    PORT
      LAYER M5 ;
      RECT 65.988 0.000 66.012 0.192 ;
    END
  END pma_rx[318]
  PIN pma_rx[319]
    DIRECTION INPUT ;
    USE SIGNAL ;
    SHAPE ABUTMENT ;
    PORT
      LAYER M5 ;
      RECT 66.180 0.000 66.204 0.192 ;
    END
  END pma_rx[319]
  PIN pma_rx[320]
    DIRECTION INPUT ;
    USE SIGNAL ;
    SHAPE ABUTMENT ;
    PORT
      LAYER M5 ;
      RECT 66.372 0.000 66.396 0.192 ;
    END
  END pma_rx[320]
  PIN pma_rx[321]
    DIRECTION INPUT ;
    USE SIGNAL ;
    SHAPE ABUTMENT ;
    PORT
      LAYER M5 ;
      RECT 66.564 0.000 66.588 0.192 ;
    END
  END pma_rx[321]
  PIN pma_rx[322]
    DIRECTION INPUT ;
    USE SIGNAL ;
    SHAPE ABUTMENT ;
    PORT
      LAYER M5 ;
      RECT 66.756 0.000 66.780 0.192 ;
    END
  END pma_rx[322]
  PIN pma_rx[323]
    DIRECTION INPUT ;
    USE SIGNAL ;
    SHAPE ABUTMENT ;
    PORT
      LAYER M5 ;
      RECT 66.948 0.000 66.972 0.192 ;
    END
  END pma_rx[323]
  PIN pma_rx[324]
    DIRECTION INPUT ;
    USE SIGNAL ;
    SHAPE ABUTMENT ;
    PORT
      LAYER M5 ;
      RECT 67.140 0.000 67.164 0.192 ;
    END
  END pma_rx[324]
  PIN pma_rx[325]
    DIRECTION INPUT ;
    USE SIGNAL ;
    SHAPE ABUTMENT ;
    PORT
      LAYER M5 ;
      RECT 67.332 0.000 67.356 0.192 ;
    END
  END pma_rx[325]
  PIN pma_rx[326]
    DIRECTION INPUT ;
    USE SIGNAL ;
    SHAPE ABUTMENT ;
    PORT
      LAYER M5 ;
      RECT 67.524 0.000 67.548 0.192 ;
    END
  END pma_rx[326]
  PIN pma_rx[327]
    DIRECTION INPUT ;
    USE SIGNAL ;
    SHAPE ABUTMENT ;
    PORT
      LAYER M5 ;
      RECT 67.716 0.000 67.740 0.192 ;
    END
  END pma_rx[327]
  PIN pma_rx[328]
    DIRECTION INPUT ;
    USE SIGNAL ;
    SHAPE ABUTMENT ;
    PORT
      LAYER M5 ;
      RECT 67.908 0.000 67.932 0.192 ;
    END
  END pma_rx[328]
  PIN pma_rx[329]
    DIRECTION INPUT ;
    USE SIGNAL ;
    SHAPE ABUTMENT ;
    PORT
      LAYER M5 ;
      RECT 68.100 0.000 68.124 0.192 ;
    END
  END pma_rx[329]
  PIN pma_rx[330]
    DIRECTION INPUT ;
    USE SIGNAL ;
    SHAPE ABUTMENT ;
    PORT
      LAYER M5 ;
      RECT 68.292 0.000 68.316 0.192 ;
    END
  END pma_rx[330]
  PIN pma_rx[331]
    DIRECTION INPUT ;
    USE SIGNAL ;
    SHAPE ABUTMENT ;
    PORT
      LAYER M5 ;
      RECT 68.484 0.000 68.508 0.192 ;
    END
  END pma_rx[331]
  PIN pma_rx[332]
    DIRECTION INPUT ;
    USE SIGNAL ;
    SHAPE ABUTMENT ;
    PORT
      LAYER M5 ;
      RECT 68.676 0.000 68.700 0.192 ;
    END
  END pma_rx[332]
  PIN pma_rx[333]
    DIRECTION INPUT ;
    USE SIGNAL ;
    SHAPE ABUTMENT ;
    PORT
      LAYER M5 ;
      RECT 68.868 0.000 68.892 0.192 ;
    END
  END pma_rx[333]
  PIN pma_rx[334]
    DIRECTION INPUT ;
    USE SIGNAL ;
    SHAPE ABUTMENT ;
    PORT
      LAYER M5 ;
      RECT 69.060 0.000 69.084 0.192 ;
    END
  END pma_rx[334]
  PIN pma_rx[335]
    DIRECTION INPUT ;
    USE SIGNAL ;
    SHAPE ABUTMENT ;
    PORT
      LAYER M5 ;
      RECT 69.252 0.000 69.276 0.192 ;
    END
  END pma_rx[335]
  PIN pma_rx[336]
    DIRECTION INPUT ;
    USE SIGNAL ;
    SHAPE ABUTMENT ;
    PORT
      LAYER M5 ;
      RECT 69.444 0.000 69.468 0.192 ;
    END
  END pma_rx[336]
  PIN pma_rx[337]
    DIRECTION INPUT ;
    USE SIGNAL ;
    SHAPE ABUTMENT ;
    PORT
      LAYER M5 ;
      RECT 69.636 0.000 69.660 0.192 ;
    END
  END pma_rx[337]
  PIN pma_rx[338]
    DIRECTION INPUT ;
    USE SIGNAL ;
    SHAPE ABUTMENT ;
    PORT
      LAYER M5 ;
      RECT 69.828 0.000 69.852 0.192 ;
    END
  END pma_rx[338]
  PIN pma_rx[339]
    DIRECTION INPUT ;
    USE SIGNAL ;
    SHAPE ABUTMENT ;
    PORT
      LAYER M5 ;
      RECT 70.020 0.000 70.044 0.192 ;
    END
  END pma_rx[339]
  PIN pma_rx[340]
    DIRECTION INPUT ;
    USE SIGNAL ;
    SHAPE ABUTMENT ;
    PORT
      LAYER M5 ;
      RECT 70.212 0.000 70.236 0.192 ;
    END
  END pma_rx[340]
  PIN pma_rx[341]
    DIRECTION INPUT ;
    USE SIGNAL ;
    SHAPE ABUTMENT ;
    PORT
      LAYER M5 ;
      RECT 70.404 0.000 70.428 0.192 ;
    END
  END pma_rx[341]
  PIN pma_rx[342]
    DIRECTION INPUT ;
    USE SIGNAL ;
    SHAPE ABUTMENT ;
    PORT
      LAYER M5 ;
      RECT 70.596 0.000 70.620 0.192 ;
    END
  END pma_rx[342]
  PIN pma_rx[343]
    DIRECTION INPUT ;
    USE SIGNAL ;
    SHAPE ABUTMENT ;
    PORT
      LAYER M5 ;
      RECT 70.788 0.000 70.812 0.192 ;
    END
  END pma_rx[343]
  PIN pma_rx[344]
    DIRECTION INPUT ;
    USE SIGNAL ;
    SHAPE ABUTMENT ;
    PORT
      LAYER M5 ;
      RECT 70.980 0.000 71.004 0.192 ;
    END
  END pma_rx[344]
  PIN pma_rx[345]
    DIRECTION INPUT ;
    USE SIGNAL ;
    SHAPE ABUTMENT ;
    PORT
      LAYER M5 ;
      RECT 71.172 0.000 71.196 0.192 ;
    END
  END pma_rx[345]
  PIN pma_rx[346]
    DIRECTION INPUT ;
    USE SIGNAL ;
    SHAPE ABUTMENT ;
    PORT
      LAYER M5 ;
      RECT 71.364 0.000 71.388 0.192 ;
    END
  END pma_rx[346]
  PIN pma_rx[347]
    DIRECTION INPUT ;
    USE SIGNAL ;
    SHAPE ABUTMENT ;
    PORT
      LAYER M5 ;
      RECT 71.556 0.000 71.580 0.192 ;
    END
  END pma_rx[347]
  PIN pma_rx[348]
    DIRECTION INPUT ;
    USE SIGNAL ;
    SHAPE ABUTMENT ;
    PORT
      LAYER M5 ;
      RECT 71.748 0.000 71.772 0.192 ;
    END
  END pma_rx[348]
  PIN pma_rx[349]
    DIRECTION INPUT ;
    USE SIGNAL ;
    SHAPE ABUTMENT ;
    PORT
      LAYER M5 ;
      RECT 71.940 0.000 71.964 0.192 ;
    END
  END pma_rx[349]
  PIN pma_rx[350]
    DIRECTION INPUT ;
    USE SIGNAL ;
    SHAPE ABUTMENT ;
    PORT
      LAYER M5 ;
      RECT 72.132 0.000 72.156 0.192 ;
    END
  END pma_rx[350]
  PIN pma_rx[351]
    DIRECTION INPUT ;
    USE SIGNAL ;
    SHAPE ABUTMENT ;
    PORT
      LAYER M5 ;
      RECT 72.324 0.000 72.348 0.192 ;
    END
  END pma_rx[351]
  PIN pma_rx[352]
    DIRECTION INPUT ;
    USE SIGNAL ;
    SHAPE ABUTMENT ;
    PORT
      LAYER M5 ;
      RECT 72.516 0.000 72.540 0.192 ;
    END
  END pma_rx[352]
  PIN pma_rx[353]
    DIRECTION INPUT ;
    USE SIGNAL ;
    SHAPE ABUTMENT ;
    PORT
      LAYER M5 ;
      RECT 72.708 0.000 72.732 0.192 ;
    END
  END pma_rx[353]
  PIN pma_rx[354]
    DIRECTION INPUT ;
    USE SIGNAL ;
    SHAPE ABUTMENT ;
    PORT
      LAYER M5 ;
      RECT 72.900 0.000 72.924 0.192 ;
    END
  END pma_rx[354]
  PIN pma_rx[355]
    DIRECTION INPUT ;
    USE SIGNAL ;
    SHAPE ABUTMENT ;
    PORT
      LAYER M5 ;
      RECT 73.092 0.000 73.116 0.192 ;
    END
  END pma_rx[355]
  PIN pma_rx[356]
    DIRECTION INPUT ;
    USE SIGNAL ;
    SHAPE ABUTMENT ;
    PORT
      LAYER M5 ;
      RECT 73.284 0.000 73.308 0.192 ;
    END
  END pma_rx[356]
  PIN pma_rx[357]
    DIRECTION INPUT ;
    USE SIGNAL ;
    SHAPE ABUTMENT ;
    PORT
      LAYER M5 ;
      RECT 73.476 0.000 73.500 0.192 ;
    END
  END pma_rx[357]
  PIN pma_rx[358]
    DIRECTION INPUT ;
    USE SIGNAL ;
    SHAPE ABUTMENT ;
    PORT
      LAYER M5 ;
      RECT 73.668 0.000 73.692 0.192 ;
    END
  END pma_rx[358]
  PIN pma_rx[359]
    DIRECTION INPUT ;
    USE SIGNAL ;
    SHAPE ABUTMENT ;
    PORT
      LAYER M5 ;
      RECT 73.860 0.000 73.884 0.192 ;
    END
  END pma_rx[359]
  PIN pma_rx[360]
    DIRECTION INPUT ;
    USE SIGNAL ;
    SHAPE ABUTMENT ;
    PORT
      LAYER M5 ;
      RECT 74.052 0.000 74.076 0.192 ;
    END
  END pma_rx[360]
  PIN pma_rx[361]
    DIRECTION INPUT ;
    USE SIGNAL ;
    SHAPE ABUTMENT ;
    PORT
      LAYER M5 ;
      RECT 74.244 0.000 74.268 0.192 ;
    END
  END pma_rx[361]
  PIN pma_rx[362]
    DIRECTION INPUT ;
    USE SIGNAL ;
    SHAPE ABUTMENT ;
    PORT
      LAYER M5 ;
      RECT 74.436 0.000 74.460 0.192 ;
    END
  END pma_rx[362]
  PIN pma_rx[363]
    DIRECTION INPUT ;
    USE SIGNAL ;
    SHAPE ABUTMENT ;
    PORT
      LAYER M5 ;
      RECT 74.628 0.000 74.652 0.192 ;
    END
  END pma_rx[363]
  PIN pma_rx[364]
    DIRECTION INPUT ;
    USE SIGNAL ;
    SHAPE ABUTMENT ;
    PORT
      LAYER M5 ;
      RECT 74.820 0.000 74.844 0.192 ;
    END
  END pma_rx[364]
  PIN pma_rx[365]
    DIRECTION INPUT ;
    USE SIGNAL ;
    SHAPE ABUTMENT ;
    PORT
      LAYER M5 ;
      RECT 75.012 0.000 75.036 0.192 ;
    END
  END pma_rx[365]
  PIN pma_rx[366]
    DIRECTION INPUT ;
    USE SIGNAL ;
    SHAPE ABUTMENT ;
    PORT
      LAYER M5 ;
      RECT 75.204 0.000 75.228 0.192 ;
    END
  END pma_rx[366]
  PIN pma_rx[367]
    DIRECTION INPUT ;
    USE SIGNAL ;
    SHAPE ABUTMENT ;
    PORT
      LAYER M5 ;
      RECT 75.396 0.000 75.420 0.192 ;
    END
  END pma_rx[367]
  PIN pma_rx[368]
    DIRECTION INPUT ;
    USE SIGNAL ;
    SHAPE ABUTMENT ;
    PORT
      LAYER M5 ;
      RECT 75.588 0.000 75.612 0.192 ;
    END
  END pma_rx[368]
  PIN pma_rx[369]
    DIRECTION INPUT ;
    USE SIGNAL ;
    SHAPE ABUTMENT ;
    PORT
      LAYER M5 ;
      RECT 75.780 0.000 75.804 0.192 ;
    END
  END pma_rx[369]
  PIN pma_rx[370]
    DIRECTION INPUT ;
    USE SIGNAL ;
    SHAPE ABUTMENT ;
    PORT
      LAYER M5 ;
      RECT 75.972 0.000 75.996 0.192 ;
    END
  END pma_rx[370]
  PIN pma_rx[371]
    DIRECTION INPUT ;
    USE SIGNAL ;
    SHAPE ABUTMENT ;
    PORT
      LAYER M5 ;
      RECT 76.164 0.000 76.188 0.192 ;
    END
  END pma_rx[371]
  PIN pma_rx[372]
    DIRECTION INPUT ;
    USE SIGNAL ;
    SHAPE ABUTMENT ;
    PORT
      LAYER M5 ;
      RECT 76.356 0.000 76.380 0.192 ;
    END
  END pma_rx[372]
  PIN pma_rx[373]
    DIRECTION INPUT ;
    USE SIGNAL ;
    SHAPE ABUTMENT ;
    PORT
      LAYER M5 ;
      RECT 76.548 0.000 76.572 0.192 ;
    END
  END pma_rx[373]
  PIN pma_rx[374]
    DIRECTION INPUT ;
    USE SIGNAL ;
    SHAPE ABUTMENT ;
    PORT
      LAYER M5 ;
      RECT 76.740 0.000 76.764 0.192 ;
    END
  END pma_rx[374]
  PIN pma_rx[375]
    DIRECTION INPUT ;
    USE SIGNAL ;
    SHAPE ABUTMENT ;
    PORT
      LAYER M5 ;
      RECT 76.932 0.000 76.956 0.192 ;
    END
  END pma_rx[375]
  PIN pma_rx[376]
    DIRECTION INPUT ;
    USE SIGNAL ;
    SHAPE ABUTMENT ;
    PORT
      LAYER M5 ;
      RECT 77.124 0.000 77.148 0.192 ;
    END
  END pma_rx[376]
  PIN pma_rx[377]
    DIRECTION INPUT ;
    USE SIGNAL ;
    SHAPE ABUTMENT ;
    PORT
      LAYER M5 ;
      RECT 77.316 0.000 77.340 0.192 ;
    END
  END pma_rx[377]
  PIN pma_rx[378]
    DIRECTION INPUT ;
    USE SIGNAL ;
    SHAPE ABUTMENT ;
    PORT
      LAYER M5 ;
      RECT 77.508 0.000 77.532 0.192 ;
    END
  END pma_rx[378]
  PIN pma_rx[379]
    DIRECTION INPUT ;
    USE SIGNAL ;
    SHAPE ABUTMENT ;
    PORT
      LAYER M5 ;
      RECT 77.700 0.000 77.724 0.192 ;
    END
  END pma_rx[379]
  PIN pma_rx[380]
    DIRECTION INPUT ;
    USE SIGNAL ;
    SHAPE ABUTMENT ;
    PORT
      LAYER M5 ;
      RECT 77.892 0.000 77.916 0.192 ;
    END
  END pma_rx[380]
  PIN pma_rx[381]
    DIRECTION INPUT ;
    USE SIGNAL ;
    SHAPE ABUTMENT ;
    PORT
      LAYER M5 ;
      RECT 78.084 0.000 78.108 0.192 ;
    END
  END pma_rx[381]
  PIN pma_rx[382]
    DIRECTION INPUT ;
    USE SIGNAL ;
    SHAPE ABUTMENT ;
    PORT
      LAYER M5 ;
      RECT 78.276 0.000 78.300 0.192 ;
    END
  END pma_rx[382]
  PIN pma_rx[383]
    DIRECTION INPUT ;
    USE SIGNAL ;
    SHAPE ABUTMENT ;
    PORT
      LAYER M5 ;
      RECT 78.468 0.000 78.492 0.192 ;
    END
  END pma_rx[383]
  PIN pma_rx[384]
    DIRECTION INPUT ;
    USE SIGNAL ;
    SHAPE ABUTMENT ;
    PORT
      LAYER M5 ;
      RECT 78.660 0.000 78.684 0.192 ;
    END
  END pma_rx[384]
  PIN pma_rx[385]
    DIRECTION INPUT ;
    USE SIGNAL ;
    SHAPE ABUTMENT ;
    PORT
      LAYER M5 ;
      RECT 78.852 0.000 78.876 0.192 ;
    END
  END pma_rx[385]
  PIN pma_rx[386]
    DIRECTION INPUT ;
    USE SIGNAL ;
    SHAPE ABUTMENT ;
    PORT
      LAYER M5 ;
      RECT 79.044 0.000 79.068 0.192 ;
    END
  END pma_rx[386]
  PIN pma_rx[387]
    DIRECTION INPUT ;
    USE SIGNAL ;
    SHAPE ABUTMENT ;
    PORT
      LAYER M5 ;
      RECT 79.236 0.000 79.260 0.192 ;
    END
  END pma_rx[387]
  PIN pma_rx[388]
    DIRECTION INPUT ;
    USE SIGNAL ;
    SHAPE ABUTMENT ;
    PORT
      LAYER M5 ;
      RECT 79.428 0.000 79.452 0.192 ;
    END
  END pma_rx[388]
  PIN pma_rx[389]
    DIRECTION INPUT ;
    USE SIGNAL ;
    SHAPE ABUTMENT ;
    PORT
      LAYER M5 ;
      RECT 79.620 0.000 79.644 0.192 ;
    END
  END pma_rx[389]
  PIN pma_rx[390]
    DIRECTION INPUT ;
    USE SIGNAL ;
    SHAPE ABUTMENT ;
    PORT
      LAYER M5 ;
      RECT 79.812 0.000 79.836 0.192 ;
    END
  END pma_rx[390]
  PIN pma_rx[391]
    DIRECTION INPUT ;
    USE SIGNAL ;
    SHAPE ABUTMENT ;
    PORT
      LAYER M5 ;
      RECT 80.004 0.000 80.028 0.192 ;
    END
  END pma_rx[391]
  PIN pma_rx[392]
    DIRECTION INPUT ;
    USE SIGNAL ;
    SHAPE ABUTMENT ;
    PORT
      LAYER M5 ;
      RECT 80.196 0.000 80.220 0.192 ;
    END
  END pma_rx[392]
  PIN pma_rx[393]
    DIRECTION INPUT ;
    USE SIGNAL ;
    SHAPE ABUTMENT ;
    PORT
      LAYER M5 ;
      RECT 80.388 0.000 80.412 0.192 ;
    END
  END pma_rx[393]
  PIN pma_rx[394]
    DIRECTION INPUT ;
    USE SIGNAL ;
    SHAPE ABUTMENT ;
    PORT
      LAYER M5 ;
      RECT 80.580 0.000 80.604 0.192 ;
    END
  END pma_rx[394]
  PIN pma_rx[395]
    DIRECTION INPUT ;
    USE SIGNAL ;
    SHAPE ABUTMENT ;
    PORT
      LAYER M5 ;
      RECT 80.772 0.000 80.796 0.192 ;
    END
  END pma_rx[395]
  PIN pma_rx[396]
    DIRECTION INPUT ;
    USE SIGNAL ;
    SHAPE ABUTMENT ;
    PORT
      LAYER M5 ;
      RECT 80.964 0.000 80.988 0.192 ;
    END
  END pma_rx[396]
  PIN pma_rx[397]
    DIRECTION INPUT ;
    USE SIGNAL ;
    SHAPE ABUTMENT ;
    PORT
      LAYER M5 ;
      RECT 81.156 0.000 81.180 0.192 ;
    END
  END pma_rx[397]
  PIN pma_rx[398]
    DIRECTION INPUT ;
    USE SIGNAL ;
    SHAPE ABUTMENT ;
    PORT
      LAYER M5 ;
      RECT 81.348 0.000 81.372 0.192 ;
    END
  END pma_rx[398]
  PIN pma_rx[399]
    DIRECTION INPUT ;
    USE SIGNAL ;
    SHAPE ABUTMENT ;
    PORT
      LAYER M5 ;
      RECT 81.540 0.000 81.564 0.192 ;
    END
  END pma_rx[399]
  PIN pma_rx[400]
    DIRECTION INPUT ;
    USE SIGNAL ;
    SHAPE ABUTMENT ;
    PORT
      LAYER M5 ;
      RECT 81.732 0.000 81.756 0.192 ;
    END
  END pma_rx[400]
  PIN pma_rx[401]
    DIRECTION INPUT ;
    USE SIGNAL ;
    SHAPE ABUTMENT ;
    PORT
      LAYER M5 ;
      RECT 81.924 0.000 81.948 0.192 ;
    END
  END pma_rx[401]
  PIN pma_rx[402]
    DIRECTION INPUT ;
    USE SIGNAL ;
    SHAPE ABUTMENT ;
    PORT
      LAYER M5 ;
      RECT 82.116 0.000 82.140 0.192 ;
    END
  END pma_rx[402]
  PIN pma_rx[403]
    DIRECTION INPUT ;
    USE SIGNAL ;
    SHAPE ABUTMENT ;
    PORT
      LAYER M5 ;
      RECT 82.308 0.000 82.332 0.192 ;
    END
  END pma_rx[403]
  PIN pma_rx[404]
    DIRECTION INPUT ;
    USE SIGNAL ;
    SHAPE ABUTMENT ;
    PORT
      LAYER M5 ;
      RECT 82.500 0.000 82.524 0.192 ;
    END
  END pma_rx[404]
  PIN pma_rx[405]
    DIRECTION INPUT ;
    USE SIGNAL ;
    SHAPE ABUTMENT ;
    PORT
      LAYER M5 ;
      RECT 82.692 0.000 82.716 0.192 ;
    END
  END pma_rx[405]
  PIN pma_rx[406]
    DIRECTION INPUT ;
    USE SIGNAL ;
    SHAPE ABUTMENT ;
    PORT
      LAYER M5 ;
      RECT 82.884 0.000 82.908 0.192 ;
    END
  END pma_rx[406]
  PIN pma_rx[407]
    DIRECTION INPUT ;
    USE SIGNAL ;
    SHAPE ABUTMENT ;
    PORT
      LAYER M5 ;
      RECT 83.076 0.000 83.100 0.192 ;
    END
  END pma_rx[407]
  PIN pma_rx[408]
    DIRECTION INPUT ;
    USE SIGNAL ;
    SHAPE ABUTMENT ;
    PORT
      LAYER M5 ;
      RECT 83.268 0.000 83.292 0.192 ;
    END
  END pma_rx[408]
  PIN pma_rx[409]
    DIRECTION INPUT ;
    USE SIGNAL ;
    SHAPE ABUTMENT ;
    PORT
      LAYER M5 ;
      RECT 83.460 0.000 83.484 0.192 ;
    END
  END pma_rx[409]
  PIN pma_rx[410]
    DIRECTION INPUT ;
    USE SIGNAL ;
    SHAPE ABUTMENT ;
    PORT
      LAYER M5 ;
      RECT 83.652 0.000 83.676 0.192 ;
    END
  END pma_rx[410]
  PIN pma_rx[411]
    DIRECTION INPUT ;
    USE SIGNAL ;
    SHAPE ABUTMENT ;
    PORT
      LAYER M5 ;
      RECT 83.844 0.000 83.868 0.192 ;
    END
  END pma_rx[411]
  PIN pma_rx[412]
    DIRECTION INPUT ;
    USE SIGNAL ;
    SHAPE ABUTMENT ;
    PORT
      LAYER M5 ;
      RECT 84.036 0.000 84.060 0.192 ;
    END
  END pma_rx[412]
  PIN pma_rx[413]
    DIRECTION INPUT ;
    USE SIGNAL ;
    SHAPE ABUTMENT ;
    PORT
      LAYER M5 ;
      RECT 84.228 0.000 84.252 0.192 ;
    END
  END pma_rx[413]
  PIN pma_rx[414]
    DIRECTION INPUT ;
    USE SIGNAL ;
    SHAPE ABUTMENT ;
    PORT
      LAYER M5 ;
      RECT 84.420 0.000 84.444 0.192 ;
    END
  END pma_rx[414]
  PIN pma_rx[415]
    DIRECTION INPUT ;
    USE SIGNAL ;
    SHAPE ABUTMENT ;
    PORT
      LAYER M5 ;
      RECT 84.612 0.000 84.636 0.192 ;
    END
  END pma_rx[415]
  PIN pma_rx[416]
    DIRECTION INPUT ;
    USE SIGNAL ;
    SHAPE ABUTMENT ;
    PORT
      LAYER M5 ;
      RECT 84.804 0.000 84.828 0.192 ;
    END
  END pma_rx[416]
  PIN pma_rx[417]
    DIRECTION INPUT ;
    USE SIGNAL ;
    SHAPE ABUTMENT ;
    PORT
      LAYER M5 ;
      RECT 84.996 0.000 85.020 0.192 ;
    END
  END pma_rx[417]
  PIN pma_rx[418]
    DIRECTION INPUT ;
    USE SIGNAL ;
    SHAPE ABUTMENT ;
    PORT
      LAYER M5 ;
      RECT 85.188 0.000 85.212 0.192 ;
    END
  END pma_rx[418]
  PIN pma_rx[419]
    DIRECTION INPUT ;
    USE SIGNAL ;
    SHAPE ABUTMENT ;
    PORT
      LAYER M5 ;
      RECT 85.380 0.000 85.404 0.192 ;
    END
  END pma_rx[419]
  PIN pma_rx[420]
    DIRECTION INPUT ;
    USE SIGNAL ;
    SHAPE ABUTMENT ;
    PORT
      LAYER M5 ;
      RECT 85.572 0.000 85.596 0.192 ;
    END
  END pma_rx[420]
  PIN pma_rx[421]
    DIRECTION INPUT ;
    USE SIGNAL ;
    SHAPE ABUTMENT ;
    PORT
      LAYER M5 ;
      RECT 85.764 0.000 85.788 0.192 ;
    END
  END pma_rx[421]
  PIN pma_rx[422]
    DIRECTION INPUT ;
    USE SIGNAL ;
    SHAPE ABUTMENT ;
    PORT
      LAYER M5 ;
      RECT 85.956 0.000 85.980 0.192 ;
    END
  END pma_rx[422]
  PIN pma_rx[423]
    DIRECTION INPUT ;
    USE SIGNAL ;
    SHAPE ABUTMENT ;
    PORT
      LAYER M5 ;
      RECT 86.148 0.000 86.172 0.192 ;
    END
  END pma_rx[423]
  PIN pma_rx[424]
    DIRECTION INPUT ;
    USE SIGNAL ;
    SHAPE ABUTMENT ;
    PORT
      LAYER M5 ;
      RECT 86.340 0.000 86.364 0.192 ;
    END
  END pma_rx[424]
  PIN pma_rx[425]
    DIRECTION INPUT ;
    USE SIGNAL ;
    SHAPE ABUTMENT ;
    PORT
      LAYER M5 ;
      RECT 86.532 0.000 86.556 0.192 ;
    END
  END pma_rx[425]
  PIN pma_rx[426]
    DIRECTION INPUT ;
    USE SIGNAL ;
    SHAPE ABUTMENT ;
    PORT
      LAYER M5 ;
      RECT 86.724 0.000 86.748 0.192 ;
    END
  END pma_rx[426]
  PIN pma_rx[427]
    DIRECTION INPUT ;
    USE SIGNAL ;
    SHAPE ABUTMENT ;
    PORT
      LAYER M5 ;
      RECT 86.916 0.000 86.940 0.192 ;
    END
  END pma_rx[427]
  PIN pma_rx[428]
    DIRECTION INPUT ;
    USE SIGNAL ;
    SHAPE ABUTMENT ;
    PORT
      LAYER M5 ;
      RECT 87.108 0.000 87.132 0.192 ;
    END
  END pma_rx[428]
  PIN pma_rx[429]
    DIRECTION INPUT ;
    USE SIGNAL ;
    SHAPE ABUTMENT ;
    PORT
      LAYER M5 ;
      RECT 87.300 0.000 87.324 0.192 ;
    END
  END pma_rx[429]
  PIN pma_rx[430]
    DIRECTION INPUT ;
    USE SIGNAL ;
    SHAPE ABUTMENT ;
    PORT
      LAYER M5 ;
      RECT 87.492 0.000 87.516 0.192 ;
    END
  END pma_rx[430]
  PIN pma_rx[431]
    DIRECTION INPUT ;
    USE SIGNAL ;
    SHAPE ABUTMENT ;
    PORT
      LAYER M5 ;
      RECT 87.684 0.000 87.708 0.192 ;
    END
  END pma_rx[431]
  PIN pma_rx[432]
    DIRECTION INPUT ;
    USE SIGNAL ;
    SHAPE ABUTMENT ;
    PORT
      LAYER M5 ;
      RECT 87.876 0.000 87.900 0.192 ;
    END
  END pma_rx[432]
  PIN pma_rx[433]
    DIRECTION INPUT ;
    USE SIGNAL ;
    SHAPE ABUTMENT ;
    PORT
      LAYER M5 ;
      RECT 88.068 0.000 88.092 0.192 ;
    END
  END pma_rx[433]
  PIN pma_rx[434]
    DIRECTION INPUT ;
    USE SIGNAL ;
    SHAPE ABUTMENT ;
    PORT
      LAYER M5 ;
      RECT 88.260 0.000 88.284 0.192 ;
    END
  END pma_rx[434]
  PIN pma_rx[435]
    DIRECTION INPUT ;
    USE SIGNAL ;
    SHAPE ABUTMENT ;
    PORT
      LAYER M5 ;
      RECT 88.452 0.000 88.476 0.192 ;
    END
  END pma_rx[435]
  PIN pma_rx[436]
    DIRECTION INPUT ;
    USE SIGNAL ;
    SHAPE ABUTMENT ;
    PORT
      LAYER M5 ;
      RECT 88.644 0.000 88.668 0.192 ;
    END
  END pma_rx[436]
  PIN pma_rx[437]
    DIRECTION INPUT ;
    USE SIGNAL ;
    SHAPE ABUTMENT ;
    PORT
      LAYER M5 ;
      RECT 88.836 0.000 88.860 0.192 ;
    END
  END pma_rx[437]
  PIN pma_rx[438]
    DIRECTION INPUT ;
    USE SIGNAL ;
    SHAPE ABUTMENT ;
    PORT
      LAYER M5 ;
      RECT 89.028 0.000 89.052 0.192 ;
    END
  END pma_rx[438]
  PIN pma_rx[439]
    DIRECTION INPUT ;
    USE SIGNAL ;
    SHAPE ABUTMENT ;
    PORT
      LAYER M5 ;
      RECT 89.220 0.000 89.244 0.192 ;
    END
  END pma_rx[439]
  PIN pma_rx[440]
    DIRECTION INPUT ;
    USE SIGNAL ;
    SHAPE ABUTMENT ;
    PORT
      LAYER M5 ;
      RECT 89.412 0.000 89.436 0.192 ;
    END
  END pma_rx[440]
  PIN pma_rx[441]
    DIRECTION INPUT ;
    USE SIGNAL ;
    SHAPE ABUTMENT ;
    PORT
      LAYER M5 ;
      RECT 89.604 0.000 89.628 0.192 ;
    END
  END pma_rx[441]
  PIN pma_rx[442]
    DIRECTION INPUT ;
    USE SIGNAL ;
    SHAPE ABUTMENT ;
    PORT
      LAYER M5 ;
      RECT 89.796 0.000 89.820 0.192 ;
    END
  END pma_rx[442]
  PIN pma_rx[443]
    DIRECTION INPUT ;
    USE SIGNAL ;
    SHAPE ABUTMENT ;
    PORT
      LAYER M5 ;
      RECT 89.988 0.000 90.012 0.192 ;
    END
  END pma_rx[443]
  PIN pma_rx[444]
    DIRECTION INPUT ;
    USE SIGNAL ;
    SHAPE ABUTMENT ;
    PORT
      LAYER M5 ;
      RECT 90.180 0.000 90.204 0.192 ;
    END
  END pma_rx[444]
  PIN pma_rx[445]
    DIRECTION INPUT ;
    USE SIGNAL ;
    SHAPE ABUTMENT ;
    PORT
      LAYER M5 ;
      RECT 90.372 0.000 90.396 0.192 ;
    END
  END pma_rx[445]
  PIN pma_rx[446]
    DIRECTION INPUT ;
    USE SIGNAL ;
    SHAPE ABUTMENT ;
    PORT
      LAYER M5 ;
      RECT 90.564 0.000 90.588 0.192 ;
    END
  END pma_rx[446]
  PIN pma_rx[447]
    DIRECTION INPUT ;
    USE SIGNAL ;
    SHAPE ABUTMENT ;
    PORT
      LAYER M5 ;
      RECT 90.756 0.000 90.780 0.192 ;
    END
  END pma_rx[447]
  PIN pma_rx[448]
    DIRECTION INPUT ;
    USE SIGNAL ;
    SHAPE ABUTMENT ;
    PORT
      LAYER M5 ;
      RECT 90.948 0.000 90.972 0.192 ;
    END
  END pma_rx[448]
  PIN pma_rx[449]
    DIRECTION INPUT ;
    USE SIGNAL ;
    SHAPE ABUTMENT ;
    PORT
      LAYER M5 ;
      RECT 91.140 0.000 91.164 0.192 ;
    END
  END pma_rx[449]
  PIN pma_rx[450]
    DIRECTION INPUT ;
    USE SIGNAL ;
    SHAPE ABUTMENT ;
    PORT
      LAYER M5 ;
      RECT 91.332 0.000 91.356 0.192 ;
    END
  END pma_rx[450]
  PIN pma_rx[451]
    DIRECTION INPUT ;
    USE SIGNAL ;
    SHAPE ABUTMENT ;
    PORT
      LAYER M5 ;
      RECT 91.524 0.000 91.548 0.192 ;
    END
  END pma_rx[451]
  PIN pma_rx[452]
    DIRECTION INPUT ;
    USE SIGNAL ;
    SHAPE ABUTMENT ;
    PORT
      LAYER M5 ;
      RECT 91.716 0.000 91.740 0.192 ;
    END
  END pma_rx[452]
  PIN pma_rx[453]
    DIRECTION INPUT ;
    USE SIGNAL ;
    SHAPE ABUTMENT ;
    PORT
      LAYER M5 ;
      RECT 91.908 0.000 91.932 0.192 ;
    END
  END pma_rx[453]
  PIN pma_rx[454]
    DIRECTION INPUT ;
    USE SIGNAL ;
    SHAPE ABUTMENT ;
    PORT
      LAYER M5 ;
      RECT 92.100 0.000 92.124 0.192 ;
    END
  END pma_rx[454]
  PIN pma_rx[455]
    DIRECTION INPUT ;
    USE SIGNAL ;
    SHAPE ABUTMENT ;
    PORT
      LAYER M5 ;
      RECT 92.292 0.000 92.316 0.192 ;
    END
  END pma_rx[455]
  PIN pma_rx[456]
    DIRECTION INPUT ;
    USE SIGNAL ;
    SHAPE ABUTMENT ;
    PORT
      LAYER M5 ;
      RECT 92.484 0.000 92.508 0.192 ;
    END
  END pma_rx[456]
  PIN pma_rx[457]
    DIRECTION INPUT ;
    USE SIGNAL ;
    SHAPE ABUTMENT ;
    PORT
      LAYER M5 ;
      RECT 92.676 0.000 92.700 0.192 ;
    END
  END pma_rx[457]
  PIN pma_rx[458]
    DIRECTION INPUT ;
    USE SIGNAL ;
    SHAPE ABUTMENT ;
    PORT
      LAYER M5 ;
      RECT 92.868 0.000 92.892 0.192 ;
    END
  END pma_rx[458]
  PIN pma_rx[459]
    DIRECTION INPUT ;
    USE SIGNAL ;
    SHAPE ABUTMENT ;
    PORT
      LAYER M5 ;
      RECT 93.060 0.000 93.084 0.192 ;
    END
  END pma_rx[459]
  PIN pma_rx[460]
    DIRECTION INPUT ;
    USE SIGNAL ;
    SHAPE ABUTMENT ;
    PORT
      LAYER M5 ;
      RECT 93.252 0.000 93.276 0.192 ;
    END
  END pma_rx[460]
  PIN pma_rx[461]
    DIRECTION INPUT ;
    USE SIGNAL ;
    SHAPE ABUTMENT ;
    PORT
      LAYER M5 ;
      RECT 93.444 0.000 93.468 0.192 ;
    END
  END pma_rx[461]
  PIN pma_rx[462]
    DIRECTION INPUT ;
    USE SIGNAL ;
    SHAPE ABUTMENT ;
    PORT
      LAYER M5 ;
      RECT 93.636 0.000 93.660 0.192 ;
    END
  END pma_rx[462]
  PIN pma_rx[463]
    DIRECTION INPUT ;
    USE SIGNAL ;
    SHAPE ABUTMENT ;
    PORT
      LAYER M5 ;
      RECT 93.828 0.000 93.852 0.192 ;
    END
  END pma_rx[463]
  PIN pma_rx[464]
    DIRECTION INPUT ;
    USE SIGNAL ;
    SHAPE ABUTMENT ;
    PORT
      LAYER M5 ;
      RECT 94.020 0.000 94.044 0.192 ;
    END
  END pma_rx[464]
  PIN pma_rx[465]
    DIRECTION INPUT ;
    USE SIGNAL ;
    SHAPE ABUTMENT ;
    PORT
      LAYER M5 ;
      RECT 94.212 0.000 94.236 0.192 ;
    END
  END pma_rx[465]
  PIN pma_rx[466]
    DIRECTION INPUT ;
    USE SIGNAL ;
    SHAPE ABUTMENT ;
    PORT
      LAYER M5 ;
      RECT 94.404 0.000 94.428 0.192 ;
    END
  END pma_rx[466]
  PIN pma_rx[467]
    DIRECTION INPUT ;
    USE SIGNAL ;
    SHAPE ABUTMENT ;
    PORT
      LAYER M5 ;
      RECT 94.596 0.000 94.620 0.192 ;
    END
  END pma_rx[467]
  PIN pma_rx[468]
    DIRECTION INPUT ;
    USE SIGNAL ;
    SHAPE ABUTMENT ;
    PORT
      LAYER M5 ;
      RECT 94.788 0.000 94.812 0.192 ;
    END
  END pma_rx[468]
  PIN pma_rx[469]
    DIRECTION INPUT ;
    USE SIGNAL ;
    SHAPE ABUTMENT ;
    PORT
      LAYER M5 ;
      RECT 94.980 0.000 95.004 0.192 ;
    END
  END pma_rx[469]
  PIN pma_rx[470]
    DIRECTION INPUT ;
    USE SIGNAL ;
    SHAPE ABUTMENT ;
    PORT
      LAYER M5 ;
      RECT 95.172 0.000 95.196 0.192 ;
    END
  END pma_rx[470]
  PIN pma_rx[471]
    DIRECTION INPUT ;
    USE SIGNAL ;
    SHAPE ABUTMENT ;
    PORT
      LAYER M5 ;
      RECT 95.364 0.000 95.388 0.192 ;
    END
  END pma_rx[471]
  PIN pma_rx[472]
    DIRECTION INPUT ;
    USE SIGNAL ;
    SHAPE ABUTMENT ;
    PORT
      LAYER M5 ;
      RECT 95.556 0.000 95.580 0.192 ;
    END
  END pma_rx[472]
  PIN pma_rx[473]
    DIRECTION INPUT ;
    USE SIGNAL ;
    SHAPE ABUTMENT ;
    PORT
      LAYER M5 ;
      RECT 95.748 0.000 95.772 0.192 ;
    END
  END pma_rx[473]
  PIN pma_rx[474]
    DIRECTION INPUT ;
    USE SIGNAL ;
    SHAPE ABUTMENT ;
    PORT
      LAYER M5 ;
      RECT 95.940 0.000 95.964 0.192 ;
    END
  END pma_rx[474]
  PIN pma_rx[475]
    DIRECTION INPUT ;
    USE SIGNAL ;
    SHAPE ABUTMENT ;
    PORT
      LAYER M5 ;
      RECT 96.132 0.000 96.156 0.192 ;
    END
  END pma_rx[475]
  PIN pma_rx[476]
    DIRECTION INPUT ;
    USE SIGNAL ;
    SHAPE ABUTMENT ;
    PORT
      LAYER M5 ;
      RECT 96.324 0.000 96.348 0.192 ;
    END
  END pma_rx[476]
  PIN pma_rx[477]
    DIRECTION INPUT ;
    USE SIGNAL ;
    SHAPE ABUTMENT ;
    PORT
      LAYER M5 ;
      RECT 96.516 0.000 96.540 0.192 ;
    END
  END pma_rx[477]
  PIN pma_rx[478]
    DIRECTION INPUT ;
    USE SIGNAL ;
    SHAPE ABUTMENT ;
    PORT
      LAYER M5 ;
      RECT 96.708 0.000 96.732 0.192 ;
    END
  END pma_rx[478]
  PIN pma_rx[479]
    DIRECTION INPUT ;
    USE SIGNAL ;
    SHAPE ABUTMENT ;
    PORT
      LAYER M5 ;
      RECT 96.900 0.000 96.924 0.192 ;
    END
  END pma_rx[479]
  PIN pma_rx[480]
    DIRECTION INPUT ;
    USE SIGNAL ;
    SHAPE ABUTMENT ;
    PORT
      LAYER M5 ;
      RECT 97.092 0.000 97.116 0.192 ;
    END
  END pma_rx[480]
  PIN pma_rx[481]
    DIRECTION INPUT ;
    USE SIGNAL ;
    SHAPE ABUTMENT ;
    PORT
      LAYER M5 ;
      RECT 97.284 0.000 97.308 0.192 ;
    END
  END pma_rx[481]
  PIN pma_rx[482]
    DIRECTION INPUT ;
    USE SIGNAL ;
    SHAPE ABUTMENT ;
    PORT
      LAYER M5 ;
      RECT 97.476 0.000 97.500 0.192 ;
    END
  END pma_rx[482]
  PIN pma_rx[483]
    DIRECTION INPUT ;
    USE SIGNAL ;
    SHAPE ABUTMENT ;
    PORT
      LAYER M5 ;
      RECT 97.668 0.000 97.692 0.192 ;
    END
  END pma_rx[483]
  PIN pma_rx[484]
    DIRECTION INPUT ;
    USE SIGNAL ;
    SHAPE ABUTMENT ;
    PORT
      LAYER M5 ;
      RECT 97.860 0.000 97.884 0.192 ;
    END
  END pma_rx[484]
  PIN pma_rx[485]
    DIRECTION INPUT ;
    USE SIGNAL ;
    SHAPE ABUTMENT ;
    PORT
      LAYER M5 ;
      RECT 98.052 0.000 98.076 0.192 ;
    END
  END pma_rx[485]
  PIN pma_rx[486]
    DIRECTION INPUT ;
    USE SIGNAL ;
    SHAPE ABUTMENT ;
    PORT
      LAYER M5 ;
      RECT 98.244 0.000 98.268 0.192 ;
    END
  END pma_rx[486]
  PIN pma_rx[487]
    DIRECTION INPUT ;
    USE SIGNAL ;
    SHAPE ABUTMENT ;
    PORT
      LAYER M5 ;
      RECT 98.436 0.000 98.460 0.192 ;
    END
  END pma_rx[487]
  PIN pma_rx[488]
    DIRECTION INPUT ;
    USE SIGNAL ;
    SHAPE ABUTMENT ;
    PORT
      LAYER M5 ;
      RECT 98.628 0.000 98.652 0.192 ;
    END
  END pma_rx[488]
  PIN pma_rx[489]
    DIRECTION INPUT ;
    USE SIGNAL ;
    SHAPE ABUTMENT ;
    PORT
      LAYER M5 ;
      RECT 98.820 0.000 98.844 0.192 ;
    END
  END pma_rx[489]
  PIN pma_rx[490]
    DIRECTION INPUT ;
    USE SIGNAL ;
    SHAPE ABUTMENT ;
    PORT
      LAYER M5 ;
      RECT 99.012 0.000 99.036 0.192 ;
    END
  END pma_rx[490]
  PIN pma_rx[491]
    DIRECTION INPUT ;
    USE SIGNAL ;
    SHAPE ABUTMENT ;
    PORT
      LAYER M5 ;
      RECT 99.204 0.000 99.228 0.192 ;
    END
  END pma_rx[491]
  PIN pma_rx[492]
    DIRECTION INPUT ;
    USE SIGNAL ;
    SHAPE ABUTMENT ;
    PORT
      LAYER M5 ;
      RECT 99.396 0.000 99.420 0.192 ;
    END
  END pma_rx[492]
  PIN pma_rx[493]
    DIRECTION INPUT ;
    USE SIGNAL ;
    SHAPE ABUTMENT ;
    PORT
      LAYER M5 ;
      RECT 99.588 0.000 99.612 0.192 ;
    END
  END pma_rx[493]
  PIN pma_rx[494]
    DIRECTION INPUT ;
    USE SIGNAL ;
    SHAPE ABUTMENT ;
    PORT
      LAYER M5 ;
      RECT 99.780 0.000 99.804 0.192 ;
    END
  END pma_rx[494]
  PIN pma_rx[495]
    DIRECTION INPUT ;
    USE SIGNAL ;
    SHAPE ABUTMENT ;
    PORT
      LAYER M5 ;
      RECT 99.972 0.000 99.996 0.192 ;
    END
  END pma_rx[495]
  PIN pma_rx[496]
    DIRECTION INPUT ;
    USE SIGNAL ;
    SHAPE ABUTMENT ;
    PORT
      LAYER M5 ;
      RECT 100.164 0.000 100.188 0.192 ;
    END
  END pma_rx[496]
  PIN pma_rx[497]
    DIRECTION INPUT ;
    USE SIGNAL ;
    SHAPE ABUTMENT ;
    PORT
      LAYER M5 ;
      RECT 100.356 0.000 100.380 0.192 ;
    END
  END pma_rx[497]
  PIN pma_rx[498]
    DIRECTION INPUT ;
    USE SIGNAL ;
    SHAPE ABUTMENT ;
    PORT
      LAYER M5 ;
      RECT 100.548 0.000 100.572 0.192 ;
    END
  END pma_rx[498]
  PIN pma_rx[499]
    DIRECTION INPUT ;
    USE SIGNAL ;
    SHAPE ABUTMENT ;
    PORT
      LAYER M5 ;
      RECT 100.740 0.000 100.764 0.192 ;
    END
  END pma_rx[499]
  PIN pma_rx[500]
    DIRECTION INPUT ;
    USE SIGNAL ;
    SHAPE ABUTMENT ;
    PORT
      LAYER M5 ;
      RECT 100.932 0.000 100.956 0.192 ;
    END
  END pma_rx[500]
  PIN pma_rx[501]
    DIRECTION INPUT ;
    USE SIGNAL ;
    SHAPE ABUTMENT ;
    PORT
      LAYER M5 ;
      RECT 101.124 0.000 101.148 0.192 ;
    END
  END pma_rx[501]
  PIN pma_rx[502]
    DIRECTION INPUT ;
    USE SIGNAL ;
    SHAPE ABUTMENT ;
    PORT
      LAYER M5 ;
      RECT 101.316 0.000 101.340 0.192 ;
    END
  END pma_rx[502]
  PIN pma_rx[503]
    DIRECTION INPUT ;
    USE SIGNAL ;
    SHAPE ABUTMENT ;
    PORT
      LAYER M5 ;
      RECT 101.508 0.000 101.532 0.192 ;
    END
  END pma_rx[503]
  PIN pma_rx[504]
    DIRECTION INPUT ;
    USE SIGNAL ;
    SHAPE ABUTMENT ;
    PORT
      LAYER M5 ;
      RECT 101.700 0.000 101.724 0.192 ;
    END
  END pma_rx[504]
  PIN pma_rx[505]
    DIRECTION INPUT ;
    USE SIGNAL ;
    SHAPE ABUTMENT ;
    PORT
      LAYER M5 ;
      RECT 101.892 0.000 101.916 0.192 ;
    END
  END pma_rx[505]
  PIN pma_rx[506]
    DIRECTION INPUT ;
    USE SIGNAL ;
    SHAPE ABUTMENT ;
    PORT
      LAYER M5 ;
      RECT 102.084 0.000 102.108 0.192 ;
    END
  END pma_rx[506]
  PIN pma_rx[507]
    DIRECTION INPUT ;
    USE SIGNAL ;
    SHAPE ABUTMENT ;
    PORT
      LAYER M5 ;
      RECT 102.276 0.000 102.300 0.192 ;
    END
  END pma_rx[507]
  PIN pma_rx[508]
    DIRECTION INPUT ;
    USE SIGNAL ;
    SHAPE ABUTMENT ;
    PORT
      LAYER M5 ;
      RECT 102.468 0.000 102.492 0.192 ;
    END
  END pma_rx[508]
  PIN pma_rx[509]
    DIRECTION INPUT ;
    USE SIGNAL ;
    SHAPE ABUTMENT ;
    PORT
      LAYER M5 ;
      RECT 102.660 0.000 102.684 0.192 ;
    END
  END pma_rx[509]
  PIN pma_rx[510]
    DIRECTION INPUT ;
    USE SIGNAL ;
    SHAPE ABUTMENT ;
    PORT
      LAYER M5 ;
      RECT 102.852 0.000 102.876 0.192 ;
    END
  END pma_rx[510]
  PIN pma_rx[511]
    DIRECTION INPUT ;
    USE SIGNAL ;
    SHAPE ABUTMENT ;
    PORT
      LAYER M5 ;
      RECT 103.044 0.000 103.068 0.192 ;
    END
  END pma_rx[511]
  PIN pma_rx[512]
    DIRECTION INPUT ;
    USE SIGNAL ;
    SHAPE ABUTMENT ;
    PORT
      LAYER M5 ;
      RECT 103.236 0.000 103.260 0.192 ;
    END
  END pma_rx[512]
  PIN q[0]
    DIRECTION OUTPUT ;
    USE SIGNAL ;
    SHAPE ABUTMENT ;
    PORT
      LAYER M5 ;
      RECT 4.836 1252.608 4.860 1252.800 ;
    END
  END q[0]
  PIN q[1]
    DIRECTION OUTPUT ;
    USE SIGNAL ;
    SHAPE ABUTMENT ;
    PORT
      LAYER M5 ;
      RECT 5.028 1252.608 5.052 1252.800 ;
    END
  END q[1]
  PIN q[2]
    DIRECTION OUTPUT ;
    USE SIGNAL ;
    SHAPE ABUTMENT ;
    PORT
      LAYER M5 ;
      RECT 5.220 1252.608 5.244 1252.800 ;
    END
  END q[2]
  PIN q[3]
    DIRECTION OUTPUT ;
    USE SIGNAL ;
    SHAPE ABUTMENT ;
    PORT
      LAYER M5 ;
      RECT 5.412 1252.608 5.436 1252.800 ;
    END
  END q[3]
  PIN q[4]
    DIRECTION OUTPUT ;
    USE SIGNAL ;
    SHAPE ABUTMENT ;
    PORT
      LAYER M5 ;
      RECT 5.604 1252.608 5.628 1252.800 ;
    END
  END q[4]
  PIN q[5]
    DIRECTION OUTPUT ;
    USE SIGNAL ;
    SHAPE ABUTMENT ;
    PORT
      LAYER M5 ;
      RECT 5.796 1252.608 5.820 1252.800 ;
    END
  END q[5]
  PIN q[6]
    DIRECTION OUTPUT ;
    USE SIGNAL ;
    SHAPE ABUTMENT ;
    PORT
      LAYER M5 ;
      RECT 5.988 1252.608 6.012 1252.800 ;
    END
  END q[6]
  PIN q[7]
    DIRECTION OUTPUT ;
    USE SIGNAL ;
    SHAPE ABUTMENT ;
    PORT
      LAYER M5 ;
      RECT 6.180 1252.608 6.204 1252.800 ;
    END
  END q[7]
  PIN q[8]
    DIRECTION OUTPUT ;
    USE SIGNAL ;
    SHAPE ABUTMENT ;
    PORT
      LAYER M5 ;
      RECT 6.372 1252.608 6.396 1252.800 ;
    END
  END q[8]
  PIN q[9]
    DIRECTION OUTPUT ;
    USE SIGNAL ;
    SHAPE ABUTMENT ;
    PORT
      LAYER M5 ;
      RECT 6.564 1252.608 6.588 1252.800 ;
    END
  END q[9]
  PIN q[10]
    DIRECTION OUTPUT ;
    USE SIGNAL ;
    SHAPE ABUTMENT ;
    PORT
      LAYER M5 ;
      RECT 6.756 1252.608 6.780 1252.800 ;
    END
  END q[10]
  PIN q[11]
    DIRECTION OUTPUT ;
    USE SIGNAL ;
    SHAPE ABUTMENT ;
    PORT
      LAYER M5 ;
      RECT 6.948 1252.608 6.972 1252.800 ;
    END
  END q[11]
  PIN q[12]
    DIRECTION OUTPUT ;
    USE SIGNAL ;
    SHAPE ABUTMENT ;
    PORT
      LAYER M5 ;
      RECT 7.140 1252.608 7.164 1252.800 ;
    END
  END q[12]
  PIN q[13]
    DIRECTION OUTPUT ;
    USE SIGNAL ;
    SHAPE ABUTMENT ;
    PORT
      LAYER M5 ;
      RECT 7.332 1252.608 7.356 1252.800 ;
    END
  END q[13]
  PIN q[14]
    DIRECTION OUTPUT ;
    USE SIGNAL ;
    SHAPE ABUTMENT ;
    PORT
      LAYER M5 ;
      RECT 7.524 1252.608 7.548 1252.800 ;
    END
  END q[14]
  PIN q[15]
    DIRECTION OUTPUT ;
    USE SIGNAL ;
    SHAPE ABUTMENT ;
    PORT
      LAYER M5 ;
      RECT 7.716 1252.608 7.740 1252.800 ;
    END
  END q[15]
  PIN q[16]
    DIRECTION OUTPUT ;
    USE SIGNAL ;
    SHAPE ABUTMENT ;
    PORT
      LAYER M5 ;
      RECT 7.908 1252.608 7.932 1252.800 ;
    END
  END q[16]
  PIN q[17]
    DIRECTION OUTPUT ;
    USE SIGNAL ;
    SHAPE ABUTMENT ;
    PORT
      LAYER M5 ;
      RECT 8.100 1252.608 8.124 1252.800 ;
    END
  END q[17]
  PIN q[18]
    DIRECTION OUTPUT ;
    USE SIGNAL ;
    SHAPE ABUTMENT ;
    PORT
      LAYER M5 ;
      RECT 8.292 1252.608 8.316 1252.800 ;
    END
  END q[18]
  PIN q[19]
    DIRECTION OUTPUT ;
    USE SIGNAL ;
    SHAPE ABUTMENT ;
    PORT
      LAYER M5 ;
      RECT 8.484 1252.608 8.508 1252.800 ;
    END
  END q[19]
  PIN q[20]
    DIRECTION OUTPUT ;
    USE SIGNAL ;
    SHAPE ABUTMENT ;
    PORT
      LAYER M5 ;
      RECT 8.676 1252.608 8.700 1252.800 ;
    END
  END q[20]
  PIN q[21]
    DIRECTION OUTPUT ;
    USE SIGNAL ;
    SHAPE ABUTMENT ;
    PORT
      LAYER M5 ;
      RECT 8.868 1252.608 8.892 1252.800 ;
    END
  END q[21]
  PIN q[22]
    DIRECTION OUTPUT ;
    USE SIGNAL ;
    SHAPE ABUTMENT ;
    PORT
      LAYER M5 ;
      RECT 9.060 1252.608 9.084 1252.800 ;
    END
  END q[22]
  PIN q[23]
    DIRECTION OUTPUT ;
    USE SIGNAL ;
    SHAPE ABUTMENT ;
    PORT
      LAYER M5 ;
      RECT 9.252 1252.608 9.276 1252.800 ;
    END
  END q[23]
  PIN q[24]
    DIRECTION OUTPUT ;
    USE SIGNAL ;
    SHAPE ABUTMENT ;
    PORT
      LAYER M5 ;
      RECT 9.444 1252.608 9.468 1252.800 ;
    END
  END q[24]
  PIN q[25]
    DIRECTION OUTPUT ;
    USE SIGNAL ;
    SHAPE ABUTMENT ;
    PORT
      LAYER M5 ;
      RECT 9.636 1252.608 9.660 1252.800 ;
    END
  END q[25]
  PIN q[26]
    DIRECTION OUTPUT ;
    USE SIGNAL ;
    SHAPE ABUTMENT ;
    PORT
      LAYER M5 ;
      RECT 9.828 1252.608 9.852 1252.800 ;
    END
  END q[26]
  PIN q[27]
    DIRECTION OUTPUT ;
    USE SIGNAL ;
    SHAPE ABUTMENT ;
    PORT
      LAYER M5 ;
      RECT 10.020 1252.608 10.044 1252.800 ;
    END
  END q[27]
  PIN q[28]
    DIRECTION OUTPUT ;
    USE SIGNAL ;
    SHAPE ABUTMENT ;
    PORT
      LAYER M5 ;
      RECT 10.212 1252.608 10.236 1252.800 ;
    END
  END q[28]
  PIN q[29]
    DIRECTION OUTPUT ;
    USE SIGNAL ;
    SHAPE ABUTMENT ;
    PORT
      LAYER M5 ;
      RECT 10.404 1252.608 10.428 1252.800 ;
    END
  END q[29]
  PIN q[30]
    DIRECTION OUTPUT ;
    USE SIGNAL ;
    SHAPE ABUTMENT ;
    PORT
      LAYER M5 ;
      RECT 10.596 1252.608 10.620 1252.800 ;
    END
  END q[30]
  PIN q[31]
    DIRECTION OUTPUT ;
    USE SIGNAL ;
    SHAPE ABUTMENT ;
    PORT
      LAYER M5 ;
      RECT 10.788 1252.608 10.812 1252.800 ;
    END
  END q[31]
  PIN q[32]
    DIRECTION OUTPUT ;
    USE SIGNAL ;
    SHAPE ABUTMENT ;
    PORT
      LAYER M5 ;
      RECT 10.980 1252.608 11.004 1252.800 ;
    END
  END q[32]
  PIN q[33]
    DIRECTION OUTPUT ;
    USE SIGNAL ;
    SHAPE ABUTMENT ;
    PORT
      LAYER M5 ;
      RECT 11.172 1252.608 11.196 1252.800 ;
    END
  END q[33]
  PIN q[34]
    DIRECTION OUTPUT ;
    USE SIGNAL ;
    SHAPE ABUTMENT ;
    PORT
      LAYER M5 ;
      RECT 11.364 1252.608 11.388 1252.800 ;
    END
  END q[34]
  PIN q[35]
    DIRECTION OUTPUT ;
    USE SIGNAL ;
    SHAPE ABUTMENT ;
    PORT
      LAYER M5 ;
      RECT 11.556 1252.608 11.580 1252.800 ;
    END
  END q[35]
  PIN q[36]
    DIRECTION OUTPUT ;
    USE SIGNAL ;
    SHAPE ABUTMENT ;
    PORT
      LAYER M5 ;
      RECT 11.748 1252.608 11.772 1252.800 ;
    END
  END q[36]
  PIN q[37]
    DIRECTION OUTPUT ;
    USE SIGNAL ;
    SHAPE ABUTMENT ;
    PORT
      LAYER M5 ;
      RECT 11.940 1252.608 11.964 1252.800 ;
    END
  END q[37]
  PIN q[38]
    DIRECTION OUTPUT ;
    USE SIGNAL ;
    SHAPE ABUTMENT ;
    PORT
      LAYER M5 ;
      RECT 12.132 1252.608 12.156 1252.800 ;
    END
  END q[38]
  PIN q[39]
    DIRECTION OUTPUT ;
    USE SIGNAL ;
    SHAPE ABUTMENT ;
    PORT
      LAYER M5 ;
      RECT 12.324 1252.608 12.348 1252.800 ;
    END
  END q[39]
  PIN q[40]
    DIRECTION OUTPUT ;
    USE SIGNAL ;
    SHAPE ABUTMENT ;
    PORT
      LAYER M5 ;
      RECT 12.516 1252.608 12.540 1252.800 ;
    END
  END q[40]
  PIN q[41]
    DIRECTION OUTPUT ;
    USE SIGNAL ;
    SHAPE ABUTMENT ;
    PORT
      LAYER M5 ;
      RECT 12.708 1252.608 12.732 1252.800 ;
    END
  END q[41]
  PIN q[42]
    DIRECTION OUTPUT ;
    USE SIGNAL ;
    SHAPE ABUTMENT ;
    PORT
      LAYER M5 ;
      RECT 12.900 1252.608 12.924 1252.800 ;
    END
  END q[42]
  PIN q[43]
    DIRECTION OUTPUT ;
    USE SIGNAL ;
    SHAPE ABUTMENT ;
    PORT
      LAYER M5 ;
      RECT 13.092 1252.608 13.116 1252.800 ;
    END
  END q[43]
  PIN q[44]
    DIRECTION OUTPUT ;
    USE SIGNAL ;
    SHAPE ABUTMENT ;
    PORT
      LAYER M5 ;
      RECT 13.284 1252.608 13.308 1252.800 ;
    END
  END q[44]
  PIN q[45]
    DIRECTION OUTPUT ;
    USE SIGNAL ;
    SHAPE ABUTMENT ;
    PORT
      LAYER M5 ;
      RECT 13.476 1252.608 13.500 1252.800 ;
    END
  END q[45]
  PIN q[46]
    DIRECTION OUTPUT ;
    USE SIGNAL ;
    SHAPE ABUTMENT ;
    PORT
      LAYER M5 ;
      RECT 13.668 1252.608 13.692 1252.800 ;
    END
  END q[46]
  PIN q[47]
    DIRECTION OUTPUT ;
    USE SIGNAL ;
    SHAPE ABUTMENT ;
    PORT
      LAYER M5 ;
      RECT 13.860 1252.608 13.884 1252.800 ;
    END
  END q[47]
  PIN q[48]
    DIRECTION OUTPUT ;
    USE SIGNAL ;
    SHAPE ABUTMENT ;
    PORT
      LAYER M5 ;
      RECT 14.052 1252.608 14.076 1252.800 ;
    END
  END q[48]
  PIN q[49]
    DIRECTION OUTPUT ;
    USE SIGNAL ;
    SHAPE ABUTMENT ;
    PORT
      LAYER M5 ;
      RECT 14.244 1252.608 14.268 1252.800 ;
    END
  END q[49]
  PIN q[50]
    DIRECTION OUTPUT ;
    USE SIGNAL ;
    SHAPE ABUTMENT ;
    PORT
      LAYER M5 ;
      RECT 14.436 1252.608 14.460 1252.800 ;
    END
  END q[50]
  PIN q[51]
    DIRECTION OUTPUT ;
    USE SIGNAL ;
    SHAPE ABUTMENT ;
    PORT
      LAYER M5 ;
      RECT 14.628 1252.608 14.652 1252.800 ;
    END
  END q[51]
  PIN q[52]
    DIRECTION OUTPUT ;
    USE SIGNAL ;
    SHAPE ABUTMENT ;
    PORT
      LAYER M5 ;
      RECT 14.820 1252.608 14.844 1252.800 ;
    END
  END q[52]
  PIN q[53]
    DIRECTION OUTPUT ;
    USE SIGNAL ;
    SHAPE ABUTMENT ;
    PORT
      LAYER M5 ;
      RECT 15.012 1252.608 15.036 1252.800 ;
    END
  END q[53]
  PIN q[54]
    DIRECTION OUTPUT ;
    USE SIGNAL ;
    SHAPE ABUTMENT ;
    PORT
      LAYER M5 ;
      RECT 15.204 1252.608 15.228 1252.800 ;
    END
  END q[54]
  PIN q[55]
    DIRECTION OUTPUT ;
    USE SIGNAL ;
    SHAPE ABUTMENT ;
    PORT
      LAYER M5 ;
      RECT 15.396 1252.608 15.420 1252.800 ;
    END
  END q[55]
  PIN q[56]
    DIRECTION OUTPUT ;
    USE SIGNAL ;
    SHAPE ABUTMENT ;
    PORT
      LAYER M5 ;
      RECT 15.588 1252.608 15.612 1252.800 ;
    END
  END q[56]
  PIN q[57]
    DIRECTION OUTPUT ;
    USE SIGNAL ;
    SHAPE ABUTMENT ;
    PORT
      LAYER M5 ;
      RECT 15.780 1252.608 15.804 1252.800 ;
    END
  END q[57]
  PIN q[58]
    DIRECTION OUTPUT ;
    USE SIGNAL ;
    SHAPE ABUTMENT ;
    PORT
      LAYER M5 ;
      RECT 15.972 1252.608 15.996 1252.800 ;
    END
  END q[58]
  PIN q[59]
    DIRECTION OUTPUT ;
    USE SIGNAL ;
    SHAPE ABUTMENT ;
    PORT
      LAYER M5 ;
      RECT 16.164 1252.608 16.188 1252.800 ;
    END
  END q[59]
  PIN q[60]
    DIRECTION OUTPUT ;
    USE SIGNAL ;
    SHAPE ABUTMENT ;
    PORT
      LAYER M5 ;
      RECT 16.356 1252.608 16.380 1252.800 ;
    END
  END q[60]
  PIN q[61]
    DIRECTION OUTPUT ;
    USE SIGNAL ;
    SHAPE ABUTMENT ;
    PORT
      LAYER M5 ;
      RECT 16.548 1252.608 16.572 1252.800 ;
    END
  END q[61]
  PIN q[62]
    DIRECTION OUTPUT ;
    USE SIGNAL ;
    SHAPE ABUTMENT ;
    PORT
      LAYER M5 ;
      RECT 16.740 1252.608 16.764 1252.800 ;
    END
  END q[62]
  PIN q[63]
    DIRECTION OUTPUT ;
    USE SIGNAL ;
    SHAPE ABUTMENT ;
    PORT
      LAYER M5 ;
      RECT 16.932 1252.608 16.956 1252.800 ;
    END
  END q[63]
  PIN q[64]
    DIRECTION OUTPUT ;
    USE SIGNAL ;
    SHAPE ABUTMENT ;
    PORT
      LAYER M5 ;
      RECT 17.124 1252.608 17.148 1252.800 ;
    END
  END q[64]
  PIN q[65]
    DIRECTION OUTPUT ;
    USE SIGNAL ;
    SHAPE ABUTMENT ;
    PORT
      LAYER M5 ;
      RECT 17.316 1252.608 17.340 1252.800 ;
    END
  END q[65]
  PIN q[66]
    DIRECTION OUTPUT ;
    USE SIGNAL ;
    SHAPE ABUTMENT ;
    PORT
      LAYER M5 ;
      RECT 17.508 1252.608 17.532 1252.800 ;
    END
  END q[66]
  PIN q[67]
    DIRECTION OUTPUT ;
    USE SIGNAL ;
    SHAPE ABUTMENT ;
    PORT
      LAYER M5 ;
      RECT 17.700 1252.608 17.724 1252.800 ;
    END
  END q[67]
  PIN q[68]
    DIRECTION OUTPUT ;
    USE SIGNAL ;
    SHAPE ABUTMENT ;
    PORT
      LAYER M5 ;
      RECT 17.892 1252.608 17.916 1252.800 ;
    END
  END q[68]
  PIN q[69]
    DIRECTION OUTPUT ;
    USE SIGNAL ;
    SHAPE ABUTMENT ;
    PORT
      LAYER M5 ;
      RECT 18.084 1252.608 18.108 1252.800 ;
    END
  END q[69]
  PIN q[70]
    DIRECTION OUTPUT ;
    USE SIGNAL ;
    SHAPE ABUTMENT ;
    PORT
      LAYER M5 ;
      RECT 18.276 1252.608 18.300 1252.800 ;
    END
  END q[70]
  PIN q[71]
    DIRECTION OUTPUT ;
    USE SIGNAL ;
    SHAPE ABUTMENT ;
    PORT
      LAYER M5 ;
      RECT 18.468 1252.608 18.492 1252.800 ;
    END
  END q[71]
  PIN q[72]
    DIRECTION OUTPUT ;
    USE SIGNAL ;
    SHAPE ABUTMENT ;
    PORT
      LAYER M5 ;
      RECT 18.660 1252.608 18.684 1252.800 ;
    END
  END q[72]
  PIN q[73]
    DIRECTION OUTPUT ;
    USE SIGNAL ;
    SHAPE ABUTMENT ;
    PORT
      LAYER M5 ;
      RECT 18.852 1252.608 18.876 1252.800 ;
    END
  END q[73]
  PIN q[74]
    DIRECTION OUTPUT ;
    USE SIGNAL ;
    SHAPE ABUTMENT ;
    PORT
      LAYER M5 ;
      RECT 19.044 1252.608 19.068 1252.800 ;
    END
  END q[74]
  PIN q[75]
    DIRECTION OUTPUT ;
    USE SIGNAL ;
    SHAPE ABUTMENT ;
    PORT
      LAYER M5 ;
      RECT 19.236 1252.608 19.260 1252.800 ;
    END
  END q[75]
  PIN q[76]
    DIRECTION OUTPUT ;
    USE SIGNAL ;
    SHAPE ABUTMENT ;
    PORT
      LAYER M5 ;
      RECT 19.428 1252.608 19.452 1252.800 ;
    END
  END q[76]
  PIN q[77]
    DIRECTION OUTPUT ;
    USE SIGNAL ;
    SHAPE ABUTMENT ;
    PORT
      LAYER M5 ;
      RECT 19.620 1252.608 19.644 1252.800 ;
    END
  END q[77]
  PIN q[78]
    DIRECTION OUTPUT ;
    USE SIGNAL ;
    SHAPE ABUTMENT ;
    PORT
      LAYER M5 ;
      RECT 19.812 1252.608 19.836 1252.800 ;
    END
  END q[78]
  PIN q[79]
    DIRECTION OUTPUT ;
    USE SIGNAL ;
    SHAPE ABUTMENT ;
    PORT
      LAYER M5 ;
      RECT 20.004 1252.608 20.028 1252.800 ;
    END
  END q[79]
  PIN q[80]
    DIRECTION OUTPUT ;
    USE SIGNAL ;
    SHAPE ABUTMENT ;
    PORT
      LAYER M5 ;
      RECT 20.196 1252.608 20.220 1252.800 ;
    END
  END q[80]
  PIN q[81]
    DIRECTION OUTPUT ;
    USE SIGNAL ;
    SHAPE ABUTMENT ;
    PORT
      LAYER M5 ;
      RECT 20.388 1252.608 20.412 1252.800 ;
    END
  END q[81]
  PIN q[82]
    DIRECTION OUTPUT ;
    USE SIGNAL ;
    SHAPE ABUTMENT ;
    PORT
      LAYER M5 ;
      RECT 20.580 1252.608 20.604 1252.800 ;
    END
  END q[82]
  PIN q[83]
    DIRECTION OUTPUT ;
    USE SIGNAL ;
    SHAPE ABUTMENT ;
    PORT
      LAYER M5 ;
      RECT 20.772 1252.608 20.796 1252.800 ;
    END
  END q[83]
  PIN q[84]
    DIRECTION OUTPUT ;
    USE SIGNAL ;
    SHAPE ABUTMENT ;
    PORT
      LAYER M5 ;
      RECT 20.964 1252.608 20.988 1252.800 ;
    END
  END q[84]
  PIN q[85]
    DIRECTION OUTPUT ;
    USE SIGNAL ;
    SHAPE ABUTMENT ;
    PORT
      LAYER M5 ;
      RECT 21.156 1252.608 21.180 1252.800 ;
    END
  END q[85]
  PIN q[86]
    DIRECTION OUTPUT ;
    USE SIGNAL ;
    SHAPE ABUTMENT ;
    PORT
      LAYER M5 ;
      RECT 21.348 1252.608 21.372 1252.800 ;
    END
  END q[86]
  PIN q[87]
    DIRECTION OUTPUT ;
    USE SIGNAL ;
    SHAPE ABUTMENT ;
    PORT
      LAYER M5 ;
      RECT 21.540 1252.608 21.564 1252.800 ;
    END
  END q[87]
  PIN q[88]
    DIRECTION OUTPUT ;
    USE SIGNAL ;
    SHAPE ABUTMENT ;
    PORT
      LAYER M5 ;
      RECT 21.732 1252.608 21.756 1252.800 ;
    END
  END q[88]
  PIN q[89]
    DIRECTION OUTPUT ;
    USE SIGNAL ;
    SHAPE ABUTMENT ;
    PORT
      LAYER M5 ;
      RECT 21.924 1252.608 21.948 1252.800 ;
    END
  END q[89]
  PIN q[90]
    DIRECTION OUTPUT ;
    USE SIGNAL ;
    SHAPE ABUTMENT ;
    PORT
      LAYER M5 ;
      RECT 22.116 1252.608 22.140 1252.800 ;
    END
  END q[90]
  PIN q[91]
    DIRECTION OUTPUT ;
    USE SIGNAL ;
    SHAPE ABUTMENT ;
    PORT
      LAYER M5 ;
      RECT 22.308 1252.608 22.332 1252.800 ;
    END
  END q[91]
  PIN q[92]
    DIRECTION OUTPUT ;
    USE SIGNAL ;
    SHAPE ABUTMENT ;
    PORT
      LAYER M5 ;
      RECT 22.500 1252.608 22.524 1252.800 ;
    END
  END q[92]
  PIN q[93]
    DIRECTION OUTPUT ;
    USE SIGNAL ;
    SHAPE ABUTMENT ;
    PORT
      LAYER M5 ;
      RECT 22.692 1252.608 22.716 1252.800 ;
    END
  END q[93]
  PIN q[94]
    DIRECTION OUTPUT ;
    USE SIGNAL ;
    SHAPE ABUTMENT ;
    PORT
      LAYER M5 ;
      RECT 22.884 1252.608 22.908 1252.800 ;
    END
  END q[94]
  PIN q[95]
    DIRECTION OUTPUT ;
    USE SIGNAL ;
    SHAPE ABUTMENT ;
    PORT
      LAYER M5 ;
      RECT 23.076 1252.608 23.100 1252.800 ;
    END
  END q[95]
  PIN q[96]
    DIRECTION OUTPUT ;
    USE SIGNAL ;
    SHAPE ABUTMENT ;
    PORT
      LAYER M5 ;
      RECT 23.268 1252.608 23.292 1252.800 ;
    END
  END q[96]
  PIN q[97]
    DIRECTION OUTPUT ;
    USE SIGNAL ;
    SHAPE ABUTMENT ;
    PORT
      LAYER M5 ;
      RECT 23.460 1252.608 23.484 1252.800 ;
    END
  END q[97]
  PIN q[98]
    DIRECTION OUTPUT ;
    USE SIGNAL ;
    SHAPE ABUTMENT ;
    PORT
      LAYER M5 ;
      RECT 23.652 1252.608 23.676 1252.800 ;
    END
  END q[98]
  PIN q[99]
    DIRECTION OUTPUT ;
    USE SIGNAL ;
    SHAPE ABUTMENT ;
    PORT
      LAYER M5 ;
      RECT 23.844 1252.608 23.868 1252.800 ;
    END
  END q[99]
  PIN q[100]
    DIRECTION OUTPUT ;
    USE SIGNAL ;
    SHAPE ABUTMENT ;
    PORT
      LAYER M5 ;
      RECT 24.036 1252.608 24.060 1252.800 ;
    END
  END q[100]
  PIN q[101]
    DIRECTION OUTPUT ;
    USE SIGNAL ;
    SHAPE ABUTMENT ;
    PORT
      LAYER M5 ;
      RECT 24.228 1252.608 24.252 1252.800 ;
    END
  END q[101]
  PIN q[102]
    DIRECTION OUTPUT ;
    USE SIGNAL ;
    SHAPE ABUTMENT ;
    PORT
      LAYER M5 ;
      RECT 24.420 1252.608 24.444 1252.800 ;
    END
  END q[102]
  PIN q[103]
    DIRECTION OUTPUT ;
    USE SIGNAL ;
    SHAPE ABUTMENT ;
    PORT
      LAYER M5 ;
      RECT 24.612 1252.608 24.636 1252.800 ;
    END
  END q[103]
  PIN q[104]
    DIRECTION OUTPUT ;
    USE SIGNAL ;
    SHAPE ABUTMENT ;
    PORT
      LAYER M5 ;
      RECT 24.804 1252.608 24.828 1252.800 ;
    END
  END q[104]
  PIN q[105]
    DIRECTION OUTPUT ;
    USE SIGNAL ;
    SHAPE ABUTMENT ;
    PORT
      LAYER M5 ;
      RECT 24.996 1252.608 25.020 1252.800 ;
    END
  END q[105]
  PIN q[106]
    DIRECTION OUTPUT ;
    USE SIGNAL ;
    SHAPE ABUTMENT ;
    PORT
      LAYER M5 ;
      RECT 25.188 1252.608 25.212 1252.800 ;
    END
  END q[106]
  PIN q[107]
    DIRECTION OUTPUT ;
    USE SIGNAL ;
    SHAPE ABUTMENT ;
    PORT
      LAYER M5 ;
      RECT 25.380 1252.608 25.404 1252.800 ;
    END
  END q[107]
  PIN q[108]
    DIRECTION OUTPUT ;
    USE SIGNAL ;
    SHAPE ABUTMENT ;
    PORT
      LAYER M5 ;
      RECT 25.572 1252.608 25.596 1252.800 ;
    END
  END q[108]
  PIN q[109]
    DIRECTION OUTPUT ;
    USE SIGNAL ;
    SHAPE ABUTMENT ;
    PORT
      LAYER M5 ;
      RECT 25.764 1252.608 25.788 1252.800 ;
    END
  END q[109]
  PIN q[110]
    DIRECTION OUTPUT ;
    USE SIGNAL ;
    SHAPE ABUTMENT ;
    PORT
      LAYER M5 ;
      RECT 25.956 1252.608 25.980 1252.800 ;
    END
  END q[110]
  PIN q[111]
    DIRECTION OUTPUT ;
    USE SIGNAL ;
    SHAPE ABUTMENT ;
    PORT
      LAYER M5 ;
      RECT 26.148 1252.608 26.172 1252.800 ;
    END
  END q[111]
  PIN q[112]
    DIRECTION OUTPUT ;
    USE SIGNAL ;
    SHAPE ABUTMENT ;
    PORT
      LAYER M5 ;
      RECT 26.340 1252.608 26.364 1252.800 ;
    END
  END q[112]
  PIN q[113]
    DIRECTION OUTPUT ;
    USE SIGNAL ;
    SHAPE ABUTMENT ;
    PORT
      LAYER M5 ;
      RECT 26.532 1252.608 26.556 1252.800 ;
    END
  END q[113]
  PIN q[114]
    DIRECTION OUTPUT ;
    USE SIGNAL ;
    SHAPE ABUTMENT ;
    PORT
      LAYER M5 ;
      RECT 26.724 1252.608 26.748 1252.800 ;
    END
  END q[114]
  PIN q[115]
    DIRECTION OUTPUT ;
    USE SIGNAL ;
    SHAPE ABUTMENT ;
    PORT
      LAYER M5 ;
      RECT 26.916 1252.608 26.940 1252.800 ;
    END
  END q[115]
  PIN q[116]
    DIRECTION OUTPUT ;
    USE SIGNAL ;
    SHAPE ABUTMENT ;
    PORT
      LAYER M5 ;
      RECT 27.108 1252.608 27.132 1252.800 ;
    END
  END q[116]
  PIN q[117]
    DIRECTION OUTPUT ;
    USE SIGNAL ;
    SHAPE ABUTMENT ;
    PORT
      LAYER M5 ;
      RECT 27.300 1252.608 27.324 1252.800 ;
    END
  END q[117]
  PIN q[118]
    DIRECTION OUTPUT ;
    USE SIGNAL ;
    SHAPE ABUTMENT ;
    PORT
      LAYER M5 ;
      RECT 27.492 1252.608 27.516 1252.800 ;
    END
  END q[118]
  PIN q[119]
    DIRECTION OUTPUT ;
    USE SIGNAL ;
    SHAPE ABUTMENT ;
    PORT
      LAYER M5 ;
      RECT 27.684 1252.608 27.708 1252.800 ;
    END
  END q[119]
  PIN q[120]
    DIRECTION OUTPUT ;
    USE SIGNAL ;
    SHAPE ABUTMENT ;
    PORT
      LAYER M5 ;
      RECT 27.876 1252.608 27.900 1252.800 ;
    END
  END q[120]
  PIN q[121]
    DIRECTION OUTPUT ;
    USE SIGNAL ;
    SHAPE ABUTMENT ;
    PORT
      LAYER M5 ;
      RECT 28.068 1252.608 28.092 1252.800 ;
    END
  END q[121]
  PIN q[122]
    DIRECTION OUTPUT ;
    USE SIGNAL ;
    SHAPE ABUTMENT ;
    PORT
      LAYER M5 ;
      RECT 28.260 1252.608 28.284 1252.800 ;
    END
  END q[122]
  PIN q[123]
    DIRECTION OUTPUT ;
    USE SIGNAL ;
    SHAPE ABUTMENT ;
    PORT
      LAYER M5 ;
      RECT 28.452 1252.608 28.476 1252.800 ;
    END
  END q[123]
  PIN q[124]
    DIRECTION OUTPUT ;
    USE SIGNAL ;
    SHAPE ABUTMENT ;
    PORT
      LAYER M5 ;
      RECT 28.644 1252.608 28.668 1252.800 ;
    END
  END q[124]
  PIN q[125]
    DIRECTION OUTPUT ;
    USE SIGNAL ;
    SHAPE ABUTMENT ;
    PORT
      LAYER M5 ;
      RECT 28.836 1252.608 28.860 1252.800 ;
    END
  END q[125]
  PIN q[126]
    DIRECTION OUTPUT ;
    USE SIGNAL ;
    SHAPE ABUTMENT ;
    PORT
      LAYER M5 ;
      RECT 29.028 1252.608 29.052 1252.800 ;
    END
  END q[126]
  PIN q[127]
    DIRECTION OUTPUT ;
    USE SIGNAL ;
    SHAPE ABUTMENT ;
    PORT
      LAYER M5 ;
      RECT 29.220 1252.608 29.244 1252.800 ;
    END
  END q[127]
  PIN q[128]
    DIRECTION OUTPUT ;
    USE SIGNAL ;
    SHAPE ABUTMENT ;
    PORT
      LAYER M5 ;
      RECT 29.412 1252.608 29.436 1252.800 ;
    END
  END q[128]
  PIN q[129]
    DIRECTION OUTPUT ;
    USE SIGNAL ;
    SHAPE ABUTMENT ;
    PORT
      LAYER M5 ;
      RECT 29.604 1252.608 29.628 1252.800 ;
    END
  END q[129]
  PIN q[130]
    DIRECTION OUTPUT ;
    USE SIGNAL ;
    SHAPE ABUTMENT ;
    PORT
      LAYER M5 ;
      RECT 29.796 1252.608 29.820 1252.800 ;
    END
  END q[130]
  PIN q[131]
    DIRECTION OUTPUT ;
    USE SIGNAL ;
    SHAPE ABUTMENT ;
    PORT
      LAYER M5 ;
      RECT 29.988 1252.608 30.012 1252.800 ;
    END
  END q[131]
  PIN q[132]
    DIRECTION OUTPUT ;
    USE SIGNAL ;
    SHAPE ABUTMENT ;
    PORT
      LAYER M5 ;
      RECT 30.180 1252.608 30.204 1252.800 ;
    END
  END q[132]
  PIN q[133]
    DIRECTION OUTPUT ;
    USE SIGNAL ;
    SHAPE ABUTMENT ;
    PORT
      LAYER M5 ;
      RECT 30.372 1252.608 30.396 1252.800 ;
    END
  END q[133]
  PIN q[134]
    DIRECTION OUTPUT ;
    USE SIGNAL ;
    SHAPE ABUTMENT ;
    PORT
      LAYER M5 ;
      RECT 30.564 1252.608 30.588 1252.800 ;
    END
  END q[134]
  PIN q[135]
    DIRECTION OUTPUT ;
    USE SIGNAL ;
    SHAPE ABUTMENT ;
    PORT
      LAYER M5 ;
      RECT 30.756 1252.608 30.780 1252.800 ;
    END
  END q[135]
  PIN q[136]
    DIRECTION OUTPUT ;
    USE SIGNAL ;
    SHAPE ABUTMENT ;
    PORT
      LAYER M5 ;
      RECT 30.948 1252.608 30.972 1252.800 ;
    END
  END q[136]
  PIN q[137]
    DIRECTION OUTPUT ;
    USE SIGNAL ;
    SHAPE ABUTMENT ;
    PORT
      LAYER M5 ;
      RECT 31.140 1252.608 31.164 1252.800 ;
    END
  END q[137]
  PIN q[138]
    DIRECTION OUTPUT ;
    USE SIGNAL ;
    SHAPE ABUTMENT ;
    PORT
      LAYER M5 ;
      RECT 31.332 1252.608 31.356 1252.800 ;
    END
  END q[138]
  PIN q[139]
    DIRECTION OUTPUT ;
    USE SIGNAL ;
    SHAPE ABUTMENT ;
    PORT
      LAYER M5 ;
      RECT 31.524 1252.608 31.548 1252.800 ;
    END
  END q[139]
  PIN q[140]
    DIRECTION OUTPUT ;
    USE SIGNAL ;
    SHAPE ABUTMENT ;
    PORT
      LAYER M5 ;
      RECT 31.716 1252.608 31.740 1252.800 ;
    END
  END q[140]
  PIN q[141]
    DIRECTION OUTPUT ;
    USE SIGNAL ;
    SHAPE ABUTMENT ;
    PORT
      LAYER M5 ;
      RECT 31.908 1252.608 31.932 1252.800 ;
    END
  END q[141]
  PIN q[142]
    DIRECTION OUTPUT ;
    USE SIGNAL ;
    SHAPE ABUTMENT ;
    PORT
      LAYER M5 ;
      RECT 32.100 1252.608 32.124 1252.800 ;
    END
  END q[142]
  PIN q[143]
    DIRECTION OUTPUT ;
    USE SIGNAL ;
    SHAPE ABUTMENT ;
    PORT
      LAYER M5 ;
      RECT 32.292 1252.608 32.316 1252.800 ;
    END
  END q[143]
  PIN q[144]
    DIRECTION OUTPUT ;
    USE SIGNAL ;
    SHAPE ABUTMENT ;
    PORT
      LAYER M5 ;
      RECT 32.484 1252.608 32.508 1252.800 ;
    END
  END q[144]
  PIN q[145]
    DIRECTION OUTPUT ;
    USE SIGNAL ;
    SHAPE ABUTMENT ;
    PORT
      LAYER M5 ;
      RECT 32.676 1252.608 32.700 1252.800 ;
    END
  END q[145]
  PIN q[146]
    DIRECTION OUTPUT ;
    USE SIGNAL ;
    SHAPE ABUTMENT ;
    PORT
      LAYER M5 ;
      RECT 32.868 1252.608 32.892 1252.800 ;
    END
  END q[146]
  PIN q[147]
    DIRECTION OUTPUT ;
    USE SIGNAL ;
    SHAPE ABUTMENT ;
    PORT
      LAYER M5 ;
      RECT 33.060 1252.608 33.084 1252.800 ;
    END
  END q[147]
  PIN q[148]
    DIRECTION OUTPUT ;
    USE SIGNAL ;
    SHAPE ABUTMENT ;
    PORT
      LAYER M5 ;
      RECT 33.252 1252.608 33.276 1252.800 ;
    END
  END q[148]
  PIN q[149]
    DIRECTION OUTPUT ;
    USE SIGNAL ;
    SHAPE ABUTMENT ;
    PORT
      LAYER M5 ;
      RECT 33.444 1252.608 33.468 1252.800 ;
    END
  END q[149]
  PIN q[150]
    DIRECTION OUTPUT ;
    USE SIGNAL ;
    SHAPE ABUTMENT ;
    PORT
      LAYER M5 ;
      RECT 33.636 1252.608 33.660 1252.800 ;
    END
  END q[150]
  PIN q[151]
    DIRECTION OUTPUT ;
    USE SIGNAL ;
    SHAPE ABUTMENT ;
    PORT
      LAYER M5 ;
      RECT 33.828 1252.608 33.852 1252.800 ;
    END
  END q[151]
  PIN q[152]
    DIRECTION OUTPUT ;
    USE SIGNAL ;
    SHAPE ABUTMENT ;
    PORT
      LAYER M5 ;
      RECT 34.020 1252.608 34.044 1252.800 ;
    END
  END q[152]
  PIN q[153]
    DIRECTION OUTPUT ;
    USE SIGNAL ;
    SHAPE ABUTMENT ;
    PORT
      LAYER M5 ;
      RECT 34.212 1252.608 34.236 1252.800 ;
    END
  END q[153]
  PIN q[154]
    DIRECTION OUTPUT ;
    USE SIGNAL ;
    SHAPE ABUTMENT ;
    PORT
      LAYER M5 ;
      RECT 34.404 1252.608 34.428 1252.800 ;
    END
  END q[154]
  PIN q[155]
    DIRECTION OUTPUT ;
    USE SIGNAL ;
    SHAPE ABUTMENT ;
    PORT
      LAYER M5 ;
      RECT 34.596 1252.608 34.620 1252.800 ;
    END
  END q[155]
  PIN q[156]
    DIRECTION OUTPUT ;
    USE SIGNAL ;
    SHAPE ABUTMENT ;
    PORT
      LAYER M5 ;
      RECT 34.788 1252.608 34.812 1252.800 ;
    END
  END q[156]
  PIN q[157]
    DIRECTION OUTPUT ;
    USE SIGNAL ;
    SHAPE ABUTMENT ;
    PORT
      LAYER M5 ;
      RECT 34.980 1252.608 35.004 1252.800 ;
    END
  END q[157]
  PIN q[158]
    DIRECTION OUTPUT ;
    USE SIGNAL ;
    SHAPE ABUTMENT ;
    PORT
      LAYER M5 ;
      RECT 35.172 1252.608 35.196 1252.800 ;
    END
  END q[158]
  PIN q[159]
    DIRECTION OUTPUT ;
    USE SIGNAL ;
    SHAPE ABUTMENT ;
    PORT
      LAYER M5 ;
      RECT 35.364 1252.608 35.388 1252.800 ;
    END
  END q[159]
  PIN q[160]
    DIRECTION OUTPUT ;
    USE SIGNAL ;
    SHAPE ABUTMENT ;
    PORT
      LAYER M5 ;
      RECT 35.556 1252.608 35.580 1252.800 ;
    END
  END q[160]
  PIN q[161]
    DIRECTION OUTPUT ;
    USE SIGNAL ;
    SHAPE ABUTMENT ;
    PORT
      LAYER M5 ;
      RECT 35.748 1252.608 35.772 1252.800 ;
    END
  END q[161]
  PIN q[162]
    DIRECTION OUTPUT ;
    USE SIGNAL ;
    SHAPE ABUTMENT ;
    PORT
      LAYER M5 ;
      RECT 35.940 1252.608 35.964 1252.800 ;
    END
  END q[162]
  PIN q[163]
    DIRECTION OUTPUT ;
    USE SIGNAL ;
    SHAPE ABUTMENT ;
    PORT
      LAYER M5 ;
      RECT 36.132 1252.608 36.156 1252.800 ;
    END
  END q[163]
  PIN q[164]
    DIRECTION OUTPUT ;
    USE SIGNAL ;
    SHAPE ABUTMENT ;
    PORT
      LAYER M5 ;
      RECT 36.324 1252.608 36.348 1252.800 ;
    END
  END q[164]
  PIN q[165]
    DIRECTION OUTPUT ;
    USE SIGNAL ;
    SHAPE ABUTMENT ;
    PORT
      LAYER M5 ;
      RECT 36.516 1252.608 36.540 1252.800 ;
    END
  END q[165]
  PIN q[166]
    DIRECTION OUTPUT ;
    USE SIGNAL ;
    SHAPE ABUTMENT ;
    PORT
      LAYER M5 ;
      RECT 36.708 1252.608 36.732 1252.800 ;
    END
  END q[166]
  PIN q[167]
    DIRECTION OUTPUT ;
    USE SIGNAL ;
    SHAPE ABUTMENT ;
    PORT
      LAYER M5 ;
      RECT 36.900 1252.608 36.924 1252.800 ;
    END
  END q[167]
  PIN q[168]
    DIRECTION OUTPUT ;
    USE SIGNAL ;
    SHAPE ABUTMENT ;
    PORT
      LAYER M5 ;
      RECT 37.092 1252.608 37.116 1252.800 ;
    END
  END q[168]
  PIN q[169]
    DIRECTION OUTPUT ;
    USE SIGNAL ;
    SHAPE ABUTMENT ;
    PORT
      LAYER M5 ;
      RECT 37.284 1252.608 37.308 1252.800 ;
    END
  END q[169]
  PIN q[170]
    DIRECTION OUTPUT ;
    USE SIGNAL ;
    SHAPE ABUTMENT ;
    PORT
      LAYER M5 ;
      RECT 37.476 1252.608 37.500 1252.800 ;
    END
  END q[170]
  PIN q[171]
    DIRECTION OUTPUT ;
    USE SIGNAL ;
    SHAPE ABUTMENT ;
    PORT
      LAYER M5 ;
      RECT 37.668 1252.608 37.692 1252.800 ;
    END
  END q[171]
  PIN q[172]
    DIRECTION OUTPUT ;
    USE SIGNAL ;
    SHAPE ABUTMENT ;
    PORT
      LAYER M5 ;
      RECT 37.860 1252.608 37.884 1252.800 ;
    END
  END q[172]
  PIN q[173]
    DIRECTION OUTPUT ;
    USE SIGNAL ;
    SHAPE ABUTMENT ;
    PORT
      LAYER M5 ;
      RECT 38.052 1252.608 38.076 1252.800 ;
    END
  END q[173]
  PIN q[174]
    DIRECTION OUTPUT ;
    USE SIGNAL ;
    SHAPE ABUTMENT ;
    PORT
      LAYER M5 ;
      RECT 38.244 1252.608 38.268 1252.800 ;
    END
  END q[174]
  PIN q[175]
    DIRECTION OUTPUT ;
    USE SIGNAL ;
    SHAPE ABUTMENT ;
    PORT
      LAYER M5 ;
      RECT 38.436 1252.608 38.460 1252.800 ;
    END
  END q[175]
  PIN q[176]
    DIRECTION OUTPUT ;
    USE SIGNAL ;
    SHAPE ABUTMENT ;
    PORT
      LAYER M5 ;
      RECT 38.628 1252.608 38.652 1252.800 ;
    END
  END q[176]
  PIN q[177]
    DIRECTION OUTPUT ;
    USE SIGNAL ;
    SHAPE ABUTMENT ;
    PORT
      LAYER M5 ;
      RECT 38.820 1252.608 38.844 1252.800 ;
    END
  END q[177]
  PIN q[178]
    DIRECTION OUTPUT ;
    USE SIGNAL ;
    SHAPE ABUTMENT ;
    PORT
      LAYER M5 ;
      RECT 39.012 1252.608 39.036 1252.800 ;
    END
  END q[178]
  PIN q[179]
    DIRECTION OUTPUT ;
    USE SIGNAL ;
    SHAPE ABUTMENT ;
    PORT
      LAYER M5 ;
      RECT 39.204 1252.608 39.228 1252.800 ;
    END
  END q[179]
  PIN q[180]
    DIRECTION OUTPUT ;
    USE SIGNAL ;
    SHAPE ABUTMENT ;
    PORT
      LAYER M5 ;
      RECT 39.396 1252.608 39.420 1252.800 ;
    END
  END q[180]
  PIN q[181]
    DIRECTION OUTPUT ;
    USE SIGNAL ;
    SHAPE ABUTMENT ;
    PORT
      LAYER M5 ;
      RECT 39.588 1252.608 39.612 1252.800 ;
    END
  END q[181]
  PIN q[182]
    DIRECTION OUTPUT ;
    USE SIGNAL ;
    SHAPE ABUTMENT ;
    PORT
      LAYER M5 ;
      RECT 39.780 1252.608 39.804 1252.800 ;
    END
  END q[182]
  PIN q[183]
    DIRECTION OUTPUT ;
    USE SIGNAL ;
    SHAPE ABUTMENT ;
    PORT
      LAYER M5 ;
      RECT 39.972 1252.608 39.996 1252.800 ;
    END
  END q[183]
  PIN q[184]
    DIRECTION OUTPUT ;
    USE SIGNAL ;
    SHAPE ABUTMENT ;
    PORT
      LAYER M5 ;
      RECT 40.164 1252.608 40.188 1252.800 ;
    END
  END q[184]
  PIN q[185]
    DIRECTION OUTPUT ;
    USE SIGNAL ;
    SHAPE ABUTMENT ;
    PORT
      LAYER M5 ;
      RECT 40.356 1252.608 40.380 1252.800 ;
    END
  END q[185]
  PIN q[186]
    DIRECTION OUTPUT ;
    USE SIGNAL ;
    SHAPE ABUTMENT ;
    PORT
      LAYER M5 ;
      RECT 40.548 1252.608 40.572 1252.800 ;
    END
  END q[186]
  PIN q[187]
    DIRECTION OUTPUT ;
    USE SIGNAL ;
    SHAPE ABUTMENT ;
    PORT
      LAYER M5 ;
      RECT 40.740 1252.608 40.764 1252.800 ;
    END
  END q[187]
  PIN q[188]
    DIRECTION OUTPUT ;
    USE SIGNAL ;
    SHAPE ABUTMENT ;
    PORT
      LAYER M5 ;
      RECT 40.932 1252.608 40.956 1252.800 ;
    END
  END q[188]
  PIN q[189]
    DIRECTION OUTPUT ;
    USE SIGNAL ;
    SHAPE ABUTMENT ;
    PORT
      LAYER M5 ;
      RECT 41.124 1252.608 41.148 1252.800 ;
    END
  END q[189]
  PIN q[190]
    DIRECTION OUTPUT ;
    USE SIGNAL ;
    SHAPE ABUTMENT ;
    PORT
      LAYER M5 ;
      RECT 41.316 1252.608 41.340 1252.800 ;
    END
  END q[190]
  PIN q[191]
    DIRECTION OUTPUT ;
    USE SIGNAL ;
    SHAPE ABUTMENT ;
    PORT
      LAYER M5 ;
      RECT 41.508 1252.608 41.532 1252.800 ;
    END
  END q[191]
  PIN q[192]
    DIRECTION OUTPUT ;
    USE SIGNAL ;
    SHAPE ABUTMENT ;
    PORT
      LAYER M5 ;
      RECT 41.700 1252.608 41.724 1252.800 ;
    END
  END q[192]
  PIN q[193]
    DIRECTION OUTPUT ;
    USE SIGNAL ;
    SHAPE ABUTMENT ;
    PORT
      LAYER M5 ;
      RECT 41.892 1252.608 41.916 1252.800 ;
    END
  END q[193]
  PIN q[194]
    DIRECTION OUTPUT ;
    USE SIGNAL ;
    SHAPE ABUTMENT ;
    PORT
      LAYER M5 ;
      RECT 42.084 1252.608 42.108 1252.800 ;
    END
  END q[194]
  PIN q[195]
    DIRECTION OUTPUT ;
    USE SIGNAL ;
    SHAPE ABUTMENT ;
    PORT
      LAYER M5 ;
      RECT 42.276 1252.608 42.300 1252.800 ;
    END
  END q[195]
  PIN q[196]
    DIRECTION OUTPUT ;
    USE SIGNAL ;
    SHAPE ABUTMENT ;
    PORT
      LAYER M5 ;
      RECT 42.468 1252.608 42.492 1252.800 ;
    END
  END q[196]
  PIN q[197]
    DIRECTION OUTPUT ;
    USE SIGNAL ;
    SHAPE ABUTMENT ;
    PORT
      LAYER M5 ;
      RECT 42.660 1252.608 42.684 1252.800 ;
    END
  END q[197]
  PIN q[198]
    DIRECTION OUTPUT ;
    USE SIGNAL ;
    SHAPE ABUTMENT ;
    PORT
      LAYER M5 ;
      RECT 42.852 1252.608 42.876 1252.800 ;
    END
  END q[198]
  PIN q[199]
    DIRECTION OUTPUT ;
    USE SIGNAL ;
    SHAPE ABUTMENT ;
    PORT
      LAYER M5 ;
      RECT 43.044 1252.608 43.068 1252.800 ;
    END
  END q[199]
  PIN q[200]
    DIRECTION OUTPUT ;
    USE SIGNAL ;
    SHAPE ABUTMENT ;
    PORT
      LAYER M5 ;
      RECT 43.236 1252.608 43.260 1252.800 ;
    END
  END q[200]
  PIN q[201]
    DIRECTION OUTPUT ;
    USE SIGNAL ;
    SHAPE ABUTMENT ;
    PORT
      LAYER M5 ;
      RECT 43.428 1252.608 43.452 1252.800 ;
    END
  END q[201]
  PIN q[202]
    DIRECTION OUTPUT ;
    USE SIGNAL ;
    SHAPE ABUTMENT ;
    PORT
      LAYER M5 ;
      RECT 43.620 1252.608 43.644 1252.800 ;
    END
  END q[202]
  PIN q[203]
    DIRECTION OUTPUT ;
    USE SIGNAL ;
    SHAPE ABUTMENT ;
    PORT
      LAYER M5 ;
      RECT 43.812 1252.608 43.836 1252.800 ;
    END
  END q[203]
  PIN q[204]
    DIRECTION OUTPUT ;
    USE SIGNAL ;
    SHAPE ABUTMENT ;
    PORT
      LAYER M5 ;
      RECT 44.004 1252.608 44.028 1252.800 ;
    END
  END q[204]
  PIN q[205]
    DIRECTION OUTPUT ;
    USE SIGNAL ;
    SHAPE ABUTMENT ;
    PORT
      LAYER M5 ;
      RECT 44.196 1252.608 44.220 1252.800 ;
    END
  END q[205]
  PIN q[206]
    DIRECTION OUTPUT ;
    USE SIGNAL ;
    SHAPE ABUTMENT ;
    PORT
      LAYER M5 ;
      RECT 44.388 1252.608 44.412 1252.800 ;
    END
  END q[206]
  PIN q[207]
    DIRECTION OUTPUT ;
    USE SIGNAL ;
    SHAPE ABUTMENT ;
    PORT
      LAYER M5 ;
      RECT 44.580 1252.608 44.604 1252.800 ;
    END
  END q[207]
  PIN q[208]
    DIRECTION OUTPUT ;
    USE SIGNAL ;
    SHAPE ABUTMENT ;
    PORT
      LAYER M5 ;
      RECT 44.772 1252.608 44.796 1252.800 ;
    END
  END q[208]
  PIN q[209]
    DIRECTION OUTPUT ;
    USE SIGNAL ;
    SHAPE ABUTMENT ;
    PORT
      LAYER M5 ;
      RECT 44.964 1252.608 44.988 1252.800 ;
    END
  END q[209]
  PIN q[210]
    DIRECTION OUTPUT ;
    USE SIGNAL ;
    SHAPE ABUTMENT ;
    PORT
      LAYER M5 ;
      RECT 45.156 1252.608 45.180 1252.800 ;
    END
  END q[210]
  PIN q[211]
    DIRECTION OUTPUT ;
    USE SIGNAL ;
    SHAPE ABUTMENT ;
    PORT
      LAYER M5 ;
      RECT 45.348 1252.608 45.372 1252.800 ;
    END
  END q[211]
  PIN q[212]
    DIRECTION OUTPUT ;
    USE SIGNAL ;
    SHAPE ABUTMENT ;
    PORT
      LAYER M5 ;
      RECT 45.540 1252.608 45.564 1252.800 ;
    END
  END q[212]
  PIN q[213]
    DIRECTION OUTPUT ;
    USE SIGNAL ;
    SHAPE ABUTMENT ;
    PORT
      LAYER M5 ;
      RECT 45.732 1252.608 45.756 1252.800 ;
    END
  END q[213]
  PIN q[214]
    DIRECTION OUTPUT ;
    USE SIGNAL ;
    SHAPE ABUTMENT ;
    PORT
      LAYER M5 ;
      RECT 45.924 1252.608 45.948 1252.800 ;
    END
  END q[214]
  PIN q[215]
    DIRECTION OUTPUT ;
    USE SIGNAL ;
    SHAPE ABUTMENT ;
    PORT
      LAYER M5 ;
      RECT 46.116 1252.608 46.140 1252.800 ;
    END
  END q[215]
  PIN q[216]
    DIRECTION OUTPUT ;
    USE SIGNAL ;
    SHAPE ABUTMENT ;
    PORT
      LAYER M5 ;
      RECT 46.308 1252.608 46.332 1252.800 ;
    END
  END q[216]
  PIN q[217]
    DIRECTION OUTPUT ;
    USE SIGNAL ;
    SHAPE ABUTMENT ;
    PORT
      LAYER M5 ;
      RECT 46.500 1252.608 46.524 1252.800 ;
    END
  END q[217]
  PIN q[218]
    DIRECTION OUTPUT ;
    USE SIGNAL ;
    SHAPE ABUTMENT ;
    PORT
      LAYER M5 ;
      RECT 46.692 1252.608 46.716 1252.800 ;
    END
  END q[218]
  PIN q[219]
    DIRECTION OUTPUT ;
    USE SIGNAL ;
    SHAPE ABUTMENT ;
    PORT
      LAYER M5 ;
      RECT 46.884 1252.608 46.908 1252.800 ;
    END
  END q[219]
  PIN q[220]
    DIRECTION OUTPUT ;
    USE SIGNAL ;
    SHAPE ABUTMENT ;
    PORT
      LAYER M5 ;
      RECT 47.076 1252.608 47.100 1252.800 ;
    END
  END q[220]
  PIN q[221]
    DIRECTION OUTPUT ;
    USE SIGNAL ;
    SHAPE ABUTMENT ;
    PORT
      LAYER M5 ;
      RECT 47.268 1252.608 47.292 1252.800 ;
    END
  END q[221]
  PIN q[222]
    DIRECTION OUTPUT ;
    USE SIGNAL ;
    SHAPE ABUTMENT ;
    PORT
      LAYER M5 ;
      RECT 47.460 1252.608 47.484 1252.800 ;
    END
  END q[222]
  PIN q[223]
    DIRECTION OUTPUT ;
    USE SIGNAL ;
    SHAPE ABUTMENT ;
    PORT
      LAYER M5 ;
      RECT 47.652 1252.608 47.676 1252.800 ;
    END
  END q[223]
  PIN q[224]
    DIRECTION OUTPUT ;
    USE SIGNAL ;
    SHAPE ABUTMENT ;
    PORT
      LAYER M5 ;
      RECT 47.844 1252.608 47.868 1252.800 ;
    END
  END q[224]
  PIN q[225]
    DIRECTION OUTPUT ;
    USE SIGNAL ;
    SHAPE ABUTMENT ;
    PORT
      LAYER M5 ;
      RECT 48.036 1252.608 48.060 1252.800 ;
    END
  END q[225]
  PIN q[226]
    DIRECTION OUTPUT ;
    USE SIGNAL ;
    SHAPE ABUTMENT ;
    PORT
      LAYER M5 ;
      RECT 48.228 1252.608 48.252 1252.800 ;
    END
  END q[226]
  PIN q[227]
    DIRECTION OUTPUT ;
    USE SIGNAL ;
    SHAPE ABUTMENT ;
    PORT
      LAYER M5 ;
      RECT 48.420 1252.608 48.444 1252.800 ;
    END
  END q[227]
  PIN q[228]
    DIRECTION OUTPUT ;
    USE SIGNAL ;
    SHAPE ABUTMENT ;
    PORT
      LAYER M5 ;
      RECT 48.612 1252.608 48.636 1252.800 ;
    END
  END q[228]
  PIN q[229]
    DIRECTION OUTPUT ;
    USE SIGNAL ;
    SHAPE ABUTMENT ;
    PORT
      LAYER M5 ;
      RECT 48.804 1252.608 48.828 1252.800 ;
    END
  END q[229]
  PIN q[230]
    DIRECTION OUTPUT ;
    USE SIGNAL ;
    SHAPE ABUTMENT ;
    PORT
      LAYER M5 ;
      RECT 48.996 1252.608 49.020 1252.800 ;
    END
  END q[230]
  PIN q[231]
    DIRECTION OUTPUT ;
    USE SIGNAL ;
    SHAPE ABUTMENT ;
    PORT
      LAYER M5 ;
      RECT 49.188 1252.608 49.212 1252.800 ;
    END
  END q[231]
  PIN q[232]
    DIRECTION OUTPUT ;
    USE SIGNAL ;
    SHAPE ABUTMENT ;
    PORT
      LAYER M5 ;
      RECT 49.380 1252.608 49.404 1252.800 ;
    END
  END q[232]
  PIN q[233]
    DIRECTION OUTPUT ;
    USE SIGNAL ;
    SHAPE ABUTMENT ;
    PORT
      LAYER M5 ;
      RECT 49.572 1252.608 49.596 1252.800 ;
    END
  END q[233]
  PIN q[234]
    DIRECTION OUTPUT ;
    USE SIGNAL ;
    SHAPE ABUTMENT ;
    PORT
      LAYER M5 ;
      RECT 49.764 1252.608 49.788 1252.800 ;
    END
  END q[234]
  PIN q[235]
    DIRECTION OUTPUT ;
    USE SIGNAL ;
    SHAPE ABUTMENT ;
    PORT
      LAYER M5 ;
      RECT 49.956 1252.608 49.980 1252.800 ;
    END
  END q[235]
  PIN q[236]
    DIRECTION OUTPUT ;
    USE SIGNAL ;
    SHAPE ABUTMENT ;
    PORT
      LAYER M5 ;
      RECT 50.148 1252.608 50.172 1252.800 ;
    END
  END q[236]
  PIN q[237]
    DIRECTION OUTPUT ;
    USE SIGNAL ;
    SHAPE ABUTMENT ;
    PORT
      LAYER M5 ;
      RECT 50.340 1252.608 50.364 1252.800 ;
    END
  END q[237]
  PIN q[238]
    DIRECTION OUTPUT ;
    USE SIGNAL ;
    SHAPE ABUTMENT ;
    PORT
      LAYER M5 ;
      RECT 50.532 1252.608 50.556 1252.800 ;
    END
  END q[238]
  PIN q[239]
    DIRECTION OUTPUT ;
    USE SIGNAL ;
    SHAPE ABUTMENT ;
    PORT
      LAYER M5 ;
      RECT 50.724 1252.608 50.748 1252.800 ;
    END
  END q[239]
  PIN q[240]
    DIRECTION OUTPUT ;
    USE SIGNAL ;
    SHAPE ABUTMENT ;
    PORT
      LAYER M5 ;
      RECT 50.916 1252.608 50.940 1252.800 ;
    END
  END q[240]
  PIN q[241]
    DIRECTION OUTPUT ;
    USE SIGNAL ;
    SHAPE ABUTMENT ;
    PORT
      LAYER M5 ;
      RECT 51.108 1252.608 51.132 1252.800 ;
    END
  END q[241]
  PIN q[242]
    DIRECTION OUTPUT ;
    USE SIGNAL ;
    SHAPE ABUTMENT ;
    PORT
      LAYER M5 ;
      RECT 51.300 1252.608 51.324 1252.800 ;
    END
  END q[242]
  PIN q[243]
    DIRECTION OUTPUT ;
    USE SIGNAL ;
    SHAPE ABUTMENT ;
    PORT
      LAYER M5 ;
      RECT 51.492 1252.608 51.516 1252.800 ;
    END
  END q[243]
  PIN q[244]
    DIRECTION OUTPUT ;
    USE SIGNAL ;
    SHAPE ABUTMENT ;
    PORT
      LAYER M5 ;
      RECT 51.684 1252.608 51.708 1252.800 ;
    END
  END q[244]
  PIN q[245]
    DIRECTION OUTPUT ;
    USE SIGNAL ;
    SHAPE ABUTMENT ;
    PORT
      LAYER M5 ;
      RECT 51.876 1252.608 51.900 1252.800 ;
    END
  END q[245]
  PIN q[246]
    DIRECTION OUTPUT ;
    USE SIGNAL ;
    SHAPE ABUTMENT ;
    PORT
      LAYER M5 ;
      RECT 52.068 1252.608 52.092 1252.800 ;
    END
  END q[246]
  PIN q[247]
    DIRECTION OUTPUT ;
    USE SIGNAL ;
    SHAPE ABUTMENT ;
    PORT
      LAYER M5 ;
      RECT 52.260 1252.608 52.284 1252.800 ;
    END
  END q[247]
  PIN q[248]
    DIRECTION OUTPUT ;
    USE SIGNAL ;
    SHAPE ABUTMENT ;
    PORT
      LAYER M5 ;
      RECT 52.452 1252.608 52.476 1252.800 ;
    END
  END q[248]
  PIN q[249]
    DIRECTION OUTPUT ;
    USE SIGNAL ;
    SHAPE ABUTMENT ;
    PORT
      LAYER M5 ;
      RECT 52.644 1252.608 52.668 1252.800 ;
    END
  END q[249]
  PIN q[250]
    DIRECTION OUTPUT ;
    USE SIGNAL ;
    SHAPE ABUTMENT ;
    PORT
      LAYER M5 ;
      RECT 52.836 1252.608 52.860 1252.800 ;
    END
  END q[250]
  PIN q[251]
    DIRECTION OUTPUT ;
    USE SIGNAL ;
    SHAPE ABUTMENT ;
    PORT
      LAYER M5 ;
      RECT 53.028 1252.608 53.052 1252.800 ;
    END
  END q[251]
  PIN q[252]
    DIRECTION OUTPUT ;
    USE SIGNAL ;
    SHAPE ABUTMENT ;
    PORT
      LAYER M5 ;
      RECT 53.220 1252.608 53.244 1252.800 ;
    END
  END q[252]
  PIN q[253]
    DIRECTION OUTPUT ;
    USE SIGNAL ;
    SHAPE ABUTMENT ;
    PORT
      LAYER M5 ;
      RECT 53.412 1252.608 53.436 1252.800 ;
    END
  END q[253]
  PIN q[254]
    DIRECTION OUTPUT ;
    USE SIGNAL ;
    SHAPE ABUTMENT ;
    PORT
      LAYER M5 ;
      RECT 53.604 1252.608 53.628 1252.800 ;
    END
  END q[254]
  PIN q[255]
    DIRECTION OUTPUT ;
    USE SIGNAL ;
    SHAPE ABUTMENT ;
    PORT
      LAYER M5 ;
      RECT 53.796 1252.608 53.820 1252.800 ;
    END
  END q[255]
  PIN q[256]
    DIRECTION OUTPUT ;
    USE SIGNAL ;
    SHAPE ABUTMENT ;
    PORT
      LAYER M5 ;
      RECT 53.988 1252.608 54.012 1252.800 ;
    END
  END q[256]
  PIN q[257]
    DIRECTION OUTPUT ;
    USE SIGNAL ;
    SHAPE ABUTMENT ;
    PORT
      LAYER M5 ;
      RECT 54.180 1252.608 54.204 1252.800 ;
    END
  END q[257]
  PIN q[258]
    DIRECTION OUTPUT ;
    USE SIGNAL ;
    SHAPE ABUTMENT ;
    PORT
      LAYER M5 ;
      RECT 54.372 1252.608 54.396 1252.800 ;
    END
  END q[258]
  PIN q[259]
    DIRECTION OUTPUT ;
    USE SIGNAL ;
    SHAPE ABUTMENT ;
    PORT
      LAYER M5 ;
      RECT 54.564 1252.608 54.588 1252.800 ;
    END
  END q[259]
  PIN q[260]
    DIRECTION OUTPUT ;
    USE SIGNAL ;
    SHAPE ABUTMENT ;
    PORT
      LAYER M5 ;
      RECT 54.756 1252.608 54.780 1252.800 ;
    END
  END q[260]
  PIN q[261]
    DIRECTION OUTPUT ;
    USE SIGNAL ;
    SHAPE ABUTMENT ;
    PORT
      LAYER M5 ;
      RECT 54.948 1252.608 54.972 1252.800 ;
    END
  END q[261]
  PIN q[262]
    DIRECTION OUTPUT ;
    USE SIGNAL ;
    SHAPE ABUTMENT ;
    PORT
      LAYER M5 ;
      RECT 55.140 1252.608 55.164 1252.800 ;
    END
  END q[262]
  PIN q[263]
    DIRECTION OUTPUT ;
    USE SIGNAL ;
    SHAPE ABUTMENT ;
    PORT
      LAYER M5 ;
      RECT 55.332 1252.608 55.356 1252.800 ;
    END
  END q[263]
  PIN q[264]
    DIRECTION OUTPUT ;
    USE SIGNAL ;
    SHAPE ABUTMENT ;
    PORT
      LAYER M5 ;
      RECT 55.524 1252.608 55.548 1252.800 ;
    END
  END q[264]
  PIN q[265]
    DIRECTION OUTPUT ;
    USE SIGNAL ;
    SHAPE ABUTMENT ;
    PORT
      LAYER M5 ;
      RECT 55.716 1252.608 55.740 1252.800 ;
    END
  END q[265]
  PIN q[266]
    DIRECTION OUTPUT ;
    USE SIGNAL ;
    SHAPE ABUTMENT ;
    PORT
      LAYER M5 ;
      RECT 55.908 1252.608 55.932 1252.800 ;
    END
  END q[266]
  PIN q[267]
    DIRECTION OUTPUT ;
    USE SIGNAL ;
    SHAPE ABUTMENT ;
    PORT
      LAYER M5 ;
      RECT 56.100 1252.608 56.124 1252.800 ;
    END
  END q[267]
  PIN q[268]
    DIRECTION OUTPUT ;
    USE SIGNAL ;
    SHAPE ABUTMENT ;
    PORT
      LAYER M5 ;
      RECT 56.292 1252.608 56.316 1252.800 ;
    END
  END q[268]
  PIN q[269]
    DIRECTION OUTPUT ;
    USE SIGNAL ;
    SHAPE ABUTMENT ;
    PORT
      LAYER M5 ;
      RECT 56.484 1252.608 56.508 1252.800 ;
    END
  END q[269]
  PIN q[270]
    DIRECTION OUTPUT ;
    USE SIGNAL ;
    SHAPE ABUTMENT ;
    PORT
      LAYER M5 ;
      RECT 56.676 1252.608 56.700 1252.800 ;
    END
  END q[270]
  PIN q[271]
    DIRECTION OUTPUT ;
    USE SIGNAL ;
    SHAPE ABUTMENT ;
    PORT
      LAYER M5 ;
      RECT 56.868 1252.608 56.892 1252.800 ;
    END
  END q[271]
  PIN q[272]
    DIRECTION OUTPUT ;
    USE SIGNAL ;
    SHAPE ABUTMENT ;
    PORT
      LAYER M5 ;
      RECT 57.060 1252.608 57.084 1252.800 ;
    END
  END q[272]
  PIN q[273]
    DIRECTION OUTPUT ;
    USE SIGNAL ;
    SHAPE ABUTMENT ;
    PORT
      LAYER M5 ;
      RECT 57.252 1252.608 57.276 1252.800 ;
    END
  END q[273]
  PIN q[274]
    DIRECTION OUTPUT ;
    USE SIGNAL ;
    SHAPE ABUTMENT ;
    PORT
      LAYER M5 ;
      RECT 57.444 1252.608 57.468 1252.800 ;
    END
  END q[274]
  PIN q[275]
    DIRECTION OUTPUT ;
    USE SIGNAL ;
    SHAPE ABUTMENT ;
    PORT
      LAYER M5 ;
      RECT 57.636 1252.608 57.660 1252.800 ;
    END
  END q[275]
  PIN q[276]
    DIRECTION OUTPUT ;
    USE SIGNAL ;
    SHAPE ABUTMENT ;
    PORT
      LAYER M5 ;
      RECT 57.828 1252.608 57.852 1252.800 ;
    END
  END q[276]
  PIN q[277]
    DIRECTION OUTPUT ;
    USE SIGNAL ;
    SHAPE ABUTMENT ;
    PORT
      LAYER M5 ;
      RECT 58.020 1252.608 58.044 1252.800 ;
    END
  END q[277]
  PIN q[278]
    DIRECTION OUTPUT ;
    USE SIGNAL ;
    SHAPE ABUTMENT ;
    PORT
      LAYER M5 ;
      RECT 58.212 1252.608 58.236 1252.800 ;
    END
  END q[278]
  PIN q[279]
    DIRECTION OUTPUT ;
    USE SIGNAL ;
    SHAPE ABUTMENT ;
    PORT
      LAYER M5 ;
      RECT 58.404 1252.608 58.428 1252.800 ;
    END
  END q[279]
  PIN q[280]
    DIRECTION OUTPUT ;
    USE SIGNAL ;
    SHAPE ABUTMENT ;
    PORT
      LAYER M5 ;
      RECT 58.596 1252.608 58.620 1252.800 ;
    END
  END q[280]
  PIN q[281]
    DIRECTION OUTPUT ;
    USE SIGNAL ;
    SHAPE ABUTMENT ;
    PORT
      LAYER M5 ;
      RECT 58.788 1252.608 58.812 1252.800 ;
    END
  END q[281]
  PIN q[282]
    DIRECTION OUTPUT ;
    USE SIGNAL ;
    SHAPE ABUTMENT ;
    PORT
      LAYER M5 ;
      RECT 58.980 1252.608 59.004 1252.800 ;
    END
  END q[282]
  PIN q[283]
    DIRECTION OUTPUT ;
    USE SIGNAL ;
    SHAPE ABUTMENT ;
    PORT
      LAYER M5 ;
      RECT 59.172 1252.608 59.196 1252.800 ;
    END
  END q[283]
  PIN q[284]
    DIRECTION OUTPUT ;
    USE SIGNAL ;
    SHAPE ABUTMENT ;
    PORT
      LAYER M5 ;
      RECT 59.364 1252.608 59.388 1252.800 ;
    END
  END q[284]
  PIN q[285]
    DIRECTION OUTPUT ;
    USE SIGNAL ;
    SHAPE ABUTMENT ;
    PORT
      LAYER M5 ;
      RECT 59.556 1252.608 59.580 1252.800 ;
    END
  END q[285]
  PIN q[286]
    DIRECTION OUTPUT ;
    USE SIGNAL ;
    SHAPE ABUTMENT ;
    PORT
      LAYER M5 ;
      RECT 59.748 1252.608 59.772 1252.800 ;
    END
  END q[286]
  PIN q[287]
    DIRECTION OUTPUT ;
    USE SIGNAL ;
    SHAPE ABUTMENT ;
    PORT
      LAYER M5 ;
      RECT 59.940 1252.608 59.964 1252.800 ;
    END
  END q[287]
  PIN q[288]
    DIRECTION OUTPUT ;
    USE SIGNAL ;
    SHAPE ABUTMENT ;
    PORT
      LAYER M5 ;
      RECT 60.132 1252.608 60.156 1252.800 ;
    END
  END q[288]
  PIN q[289]
    DIRECTION OUTPUT ;
    USE SIGNAL ;
    SHAPE ABUTMENT ;
    PORT
      LAYER M5 ;
      RECT 60.324 1252.608 60.348 1252.800 ;
    END
  END q[289]
  PIN q[290]
    DIRECTION OUTPUT ;
    USE SIGNAL ;
    SHAPE ABUTMENT ;
    PORT
      LAYER M5 ;
      RECT 60.516 1252.608 60.540 1252.800 ;
    END
  END q[290]
  PIN q[291]
    DIRECTION OUTPUT ;
    USE SIGNAL ;
    SHAPE ABUTMENT ;
    PORT
      LAYER M5 ;
      RECT 60.708 1252.608 60.732 1252.800 ;
    END
  END q[291]
  PIN q[292]
    DIRECTION OUTPUT ;
    USE SIGNAL ;
    SHAPE ABUTMENT ;
    PORT
      LAYER M5 ;
      RECT 60.900 1252.608 60.924 1252.800 ;
    END
  END q[292]
  PIN q[293]
    DIRECTION OUTPUT ;
    USE SIGNAL ;
    SHAPE ABUTMENT ;
    PORT
      LAYER M5 ;
      RECT 61.092 1252.608 61.116 1252.800 ;
    END
  END q[293]
  PIN q[294]
    DIRECTION OUTPUT ;
    USE SIGNAL ;
    SHAPE ABUTMENT ;
    PORT
      LAYER M5 ;
      RECT 61.284 1252.608 61.308 1252.800 ;
    END
  END q[294]
  PIN q[295]
    DIRECTION OUTPUT ;
    USE SIGNAL ;
    SHAPE ABUTMENT ;
    PORT
      LAYER M5 ;
      RECT 61.476 1252.608 61.500 1252.800 ;
    END
  END q[295]
  PIN q[296]
    DIRECTION OUTPUT ;
    USE SIGNAL ;
    SHAPE ABUTMENT ;
    PORT
      LAYER M5 ;
      RECT 61.668 1252.608 61.692 1252.800 ;
    END
  END q[296]
  PIN q[297]
    DIRECTION OUTPUT ;
    USE SIGNAL ;
    SHAPE ABUTMENT ;
    PORT
      LAYER M5 ;
      RECT 61.860 1252.608 61.884 1252.800 ;
    END
  END q[297]
  PIN q[298]
    DIRECTION OUTPUT ;
    USE SIGNAL ;
    SHAPE ABUTMENT ;
    PORT
      LAYER M5 ;
      RECT 62.052 1252.608 62.076 1252.800 ;
    END
  END q[298]
  PIN q[299]
    DIRECTION OUTPUT ;
    USE SIGNAL ;
    SHAPE ABUTMENT ;
    PORT
      LAYER M5 ;
      RECT 62.244 1252.608 62.268 1252.800 ;
    END
  END q[299]
  PIN q[300]
    DIRECTION OUTPUT ;
    USE SIGNAL ;
    SHAPE ABUTMENT ;
    PORT
      LAYER M5 ;
      RECT 62.436 1252.608 62.460 1252.800 ;
    END
  END q[300]
  PIN q[301]
    DIRECTION OUTPUT ;
    USE SIGNAL ;
    SHAPE ABUTMENT ;
    PORT
      LAYER M5 ;
      RECT 62.628 1252.608 62.652 1252.800 ;
    END
  END q[301]
  PIN q[302]
    DIRECTION OUTPUT ;
    USE SIGNAL ;
    SHAPE ABUTMENT ;
    PORT
      LAYER M5 ;
      RECT 62.820 1252.608 62.844 1252.800 ;
    END
  END q[302]
  PIN q[303]
    DIRECTION OUTPUT ;
    USE SIGNAL ;
    SHAPE ABUTMENT ;
    PORT
      LAYER M5 ;
      RECT 63.012 1252.608 63.036 1252.800 ;
    END
  END q[303]
  PIN q[304]
    DIRECTION OUTPUT ;
    USE SIGNAL ;
    SHAPE ABUTMENT ;
    PORT
      LAYER M5 ;
      RECT 63.204 1252.608 63.228 1252.800 ;
    END
  END q[304]
  PIN q[305]
    DIRECTION OUTPUT ;
    USE SIGNAL ;
    SHAPE ABUTMENT ;
    PORT
      LAYER M5 ;
      RECT 63.396 1252.608 63.420 1252.800 ;
    END
  END q[305]
  PIN q[306]
    DIRECTION OUTPUT ;
    USE SIGNAL ;
    SHAPE ABUTMENT ;
    PORT
      LAYER M5 ;
      RECT 63.588 1252.608 63.612 1252.800 ;
    END
  END q[306]
  PIN q[307]
    DIRECTION OUTPUT ;
    USE SIGNAL ;
    SHAPE ABUTMENT ;
    PORT
      LAYER M5 ;
      RECT 63.780 1252.608 63.804 1252.800 ;
    END
  END q[307]
  PIN q[308]
    DIRECTION OUTPUT ;
    USE SIGNAL ;
    SHAPE ABUTMENT ;
    PORT
      LAYER M5 ;
      RECT 63.972 1252.608 63.996 1252.800 ;
    END
  END q[308]
  PIN q[309]
    DIRECTION OUTPUT ;
    USE SIGNAL ;
    SHAPE ABUTMENT ;
    PORT
      LAYER M5 ;
      RECT 64.164 1252.608 64.188 1252.800 ;
    END
  END q[309]
  PIN q[310]
    DIRECTION OUTPUT ;
    USE SIGNAL ;
    SHAPE ABUTMENT ;
    PORT
      LAYER M5 ;
      RECT 64.356 1252.608 64.380 1252.800 ;
    END
  END q[310]
  PIN q[311]
    DIRECTION OUTPUT ;
    USE SIGNAL ;
    SHAPE ABUTMENT ;
    PORT
      LAYER M5 ;
      RECT 64.548 1252.608 64.572 1252.800 ;
    END
  END q[311]
  PIN q[312]
    DIRECTION OUTPUT ;
    USE SIGNAL ;
    SHAPE ABUTMENT ;
    PORT
      LAYER M5 ;
      RECT 64.740 1252.608 64.764 1252.800 ;
    END
  END q[312]
  PIN q[313]
    DIRECTION OUTPUT ;
    USE SIGNAL ;
    SHAPE ABUTMENT ;
    PORT
      LAYER M5 ;
      RECT 64.932 1252.608 64.956 1252.800 ;
    END
  END q[313]
  PIN q[314]
    DIRECTION OUTPUT ;
    USE SIGNAL ;
    SHAPE ABUTMENT ;
    PORT
      LAYER M5 ;
      RECT 65.124 1252.608 65.148 1252.800 ;
    END
  END q[314]
  PIN q[315]
    DIRECTION OUTPUT ;
    USE SIGNAL ;
    SHAPE ABUTMENT ;
    PORT
      LAYER M5 ;
      RECT 65.316 1252.608 65.340 1252.800 ;
    END
  END q[315]
  PIN q[316]
    DIRECTION OUTPUT ;
    USE SIGNAL ;
    SHAPE ABUTMENT ;
    PORT
      LAYER M5 ;
      RECT 65.508 1252.608 65.532 1252.800 ;
    END
  END q[316]
  PIN q[317]
    DIRECTION OUTPUT ;
    USE SIGNAL ;
    SHAPE ABUTMENT ;
    PORT
      LAYER M5 ;
      RECT 65.700 1252.608 65.724 1252.800 ;
    END
  END q[317]
  PIN q[318]
    DIRECTION OUTPUT ;
    USE SIGNAL ;
    SHAPE ABUTMENT ;
    PORT
      LAYER M5 ;
      RECT 65.892 1252.608 65.916 1252.800 ;
    END
  END q[318]
  PIN q[319]
    DIRECTION OUTPUT ;
    USE SIGNAL ;
    SHAPE ABUTMENT ;
    PORT
      LAYER M5 ;
      RECT 66.084 1252.608 66.108 1252.800 ;
    END
  END q[319]
  PIN q[320]
    DIRECTION OUTPUT ;
    USE SIGNAL ;
    SHAPE ABUTMENT ;
    PORT
      LAYER M5 ;
      RECT 66.276 1252.608 66.300 1252.800 ;
    END
  END q[320]
  PIN q[321]
    DIRECTION OUTPUT ;
    USE SIGNAL ;
    SHAPE ABUTMENT ;
    PORT
      LAYER M5 ;
      RECT 66.468 1252.608 66.492 1252.800 ;
    END
  END q[321]
  PIN q[322]
    DIRECTION OUTPUT ;
    USE SIGNAL ;
    SHAPE ABUTMENT ;
    PORT
      LAYER M5 ;
      RECT 66.660 1252.608 66.684 1252.800 ;
    END
  END q[322]
  PIN q[323]
    DIRECTION OUTPUT ;
    USE SIGNAL ;
    SHAPE ABUTMENT ;
    PORT
      LAYER M5 ;
      RECT 66.852 1252.608 66.876 1252.800 ;
    END
  END q[323]
  PIN q[324]
    DIRECTION OUTPUT ;
    USE SIGNAL ;
    SHAPE ABUTMENT ;
    PORT
      LAYER M5 ;
      RECT 67.044 1252.608 67.068 1252.800 ;
    END
  END q[324]
  PIN q[325]
    DIRECTION OUTPUT ;
    USE SIGNAL ;
    SHAPE ABUTMENT ;
    PORT
      LAYER M5 ;
      RECT 67.236 1252.608 67.260 1252.800 ;
    END
  END q[325]
  PIN q[326]
    DIRECTION OUTPUT ;
    USE SIGNAL ;
    SHAPE ABUTMENT ;
    PORT
      LAYER M5 ;
      RECT 67.428 1252.608 67.452 1252.800 ;
    END
  END q[326]
  PIN q[327]
    DIRECTION OUTPUT ;
    USE SIGNAL ;
    SHAPE ABUTMENT ;
    PORT
      LAYER M5 ;
      RECT 67.620 1252.608 67.644 1252.800 ;
    END
  END q[327]
  PIN q[328]
    DIRECTION OUTPUT ;
    USE SIGNAL ;
    SHAPE ABUTMENT ;
    PORT
      LAYER M5 ;
      RECT 67.812 1252.608 67.836 1252.800 ;
    END
  END q[328]
  PIN q[329]
    DIRECTION OUTPUT ;
    USE SIGNAL ;
    SHAPE ABUTMENT ;
    PORT
      LAYER M5 ;
      RECT 68.004 1252.608 68.028 1252.800 ;
    END
  END q[329]
  PIN q[330]
    DIRECTION OUTPUT ;
    USE SIGNAL ;
    SHAPE ABUTMENT ;
    PORT
      LAYER M5 ;
      RECT 68.196 1252.608 68.220 1252.800 ;
    END
  END q[330]
  PIN q[331]
    DIRECTION OUTPUT ;
    USE SIGNAL ;
    SHAPE ABUTMENT ;
    PORT
      LAYER M5 ;
      RECT 68.388 1252.608 68.412 1252.800 ;
    END
  END q[331]
  PIN q[332]
    DIRECTION OUTPUT ;
    USE SIGNAL ;
    SHAPE ABUTMENT ;
    PORT
      LAYER M5 ;
      RECT 68.580 1252.608 68.604 1252.800 ;
    END
  END q[332]
  PIN q[333]
    DIRECTION OUTPUT ;
    USE SIGNAL ;
    SHAPE ABUTMENT ;
    PORT
      LAYER M5 ;
      RECT 68.772 1252.608 68.796 1252.800 ;
    END
  END q[333]
  PIN q[334]
    DIRECTION OUTPUT ;
    USE SIGNAL ;
    SHAPE ABUTMENT ;
    PORT
      LAYER M5 ;
      RECT 68.964 1252.608 68.988 1252.800 ;
    END
  END q[334]
  PIN q[335]
    DIRECTION OUTPUT ;
    USE SIGNAL ;
    SHAPE ABUTMENT ;
    PORT
      LAYER M5 ;
      RECT 69.156 1252.608 69.180 1252.800 ;
    END
  END q[335]
  PIN q[336]
    DIRECTION OUTPUT ;
    USE SIGNAL ;
    SHAPE ABUTMENT ;
    PORT
      LAYER M5 ;
      RECT 69.348 1252.608 69.372 1252.800 ;
    END
  END q[336]
  PIN q[337]
    DIRECTION OUTPUT ;
    USE SIGNAL ;
    SHAPE ABUTMENT ;
    PORT
      LAYER M5 ;
      RECT 69.540 1252.608 69.564 1252.800 ;
    END
  END q[337]
  PIN q[338]
    DIRECTION OUTPUT ;
    USE SIGNAL ;
    SHAPE ABUTMENT ;
    PORT
      LAYER M5 ;
      RECT 69.732 1252.608 69.756 1252.800 ;
    END
  END q[338]
  PIN q[339]
    DIRECTION OUTPUT ;
    USE SIGNAL ;
    SHAPE ABUTMENT ;
    PORT
      LAYER M5 ;
      RECT 69.924 1252.608 69.948 1252.800 ;
    END
  END q[339]
  PIN q[340]
    DIRECTION OUTPUT ;
    USE SIGNAL ;
    SHAPE ABUTMENT ;
    PORT
      LAYER M5 ;
      RECT 70.116 1252.608 70.140 1252.800 ;
    END
  END q[340]
  PIN q[341]
    DIRECTION OUTPUT ;
    USE SIGNAL ;
    SHAPE ABUTMENT ;
    PORT
      LAYER M5 ;
      RECT 70.308 1252.608 70.332 1252.800 ;
    END
  END q[341]
  PIN q[342]
    DIRECTION OUTPUT ;
    USE SIGNAL ;
    SHAPE ABUTMENT ;
    PORT
      LAYER M5 ;
      RECT 70.500 1252.608 70.524 1252.800 ;
    END
  END q[342]
  PIN q[343]
    DIRECTION OUTPUT ;
    USE SIGNAL ;
    SHAPE ABUTMENT ;
    PORT
      LAYER M5 ;
      RECT 70.692 1252.608 70.716 1252.800 ;
    END
  END q[343]
  PIN q[344]
    DIRECTION OUTPUT ;
    USE SIGNAL ;
    SHAPE ABUTMENT ;
    PORT
      LAYER M5 ;
      RECT 70.884 1252.608 70.908 1252.800 ;
    END
  END q[344]
  PIN q[345]
    DIRECTION OUTPUT ;
    USE SIGNAL ;
    SHAPE ABUTMENT ;
    PORT
      LAYER M5 ;
      RECT 71.076 1252.608 71.100 1252.800 ;
    END
  END q[345]
  PIN q[346]
    DIRECTION OUTPUT ;
    USE SIGNAL ;
    SHAPE ABUTMENT ;
    PORT
      LAYER M5 ;
      RECT 71.268 1252.608 71.292 1252.800 ;
    END
  END q[346]
  PIN q[347]
    DIRECTION OUTPUT ;
    USE SIGNAL ;
    SHAPE ABUTMENT ;
    PORT
      LAYER M5 ;
      RECT 71.460 1252.608 71.484 1252.800 ;
    END
  END q[347]
  PIN q[348]
    DIRECTION OUTPUT ;
    USE SIGNAL ;
    SHAPE ABUTMENT ;
    PORT
      LAYER M5 ;
      RECT 71.652 1252.608 71.676 1252.800 ;
    END
  END q[348]
  PIN q[349]
    DIRECTION OUTPUT ;
    USE SIGNAL ;
    SHAPE ABUTMENT ;
    PORT
      LAYER M5 ;
      RECT 71.844 1252.608 71.868 1252.800 ;
    END
  END q[349]
  PIN q[350]
    DIRECTION OUTPUT ;
    USE SIGNAL ;
    SHAPE ABUTMENT ;
    PORT
      LAYER M5 ;
      RECT 72.036 1252.608 72.060 1252.800 ;
    END
  END q[350]
  PIN q[351]
    DIRECTION OUTPUT ;
    USE SIGNAL ;
    SHAPE ABUTMENT ;
    PORT
      LAYER M5 ;
      RECT 72.228 1252.608 72.252 1252.800 ;
    END
  END q[351]
  PIN q[352]
    DIRECTION OUTPUT ;
    USE SIGNAL ;
    SHAPE ABUTMENT ;
    PORT
      LAYER M5 ;
      RECT 72.420 1252.608 72.444 1252.800 ;
    END
  END q[352]
  PIN q[353]
    DIRECTION OUTPUT ;
    USE SIGNAL ;
    SHAPE ABUTMENT ;
    PORT
      LAYER M5 ;
      RECT 72.612 1252.608 72.636 1252.800 ;
    END
  END q[353]
  PIN q[354]
    DIRECTION OUTPUT ;
    USE SIGNAL ;
    SHAPE ABUTMENT ;
    PORT
      LAYER M5 ;
      RECT 72.804 1252.608 72.828 1252.800 ;
    END
  END q[354]
  PIN q[355]
    DIRECTION OUTPUT ;
    USE SIGNAL ;
    SHAPE ABUTMENT ;
    PORT
      LAYER M5 ;
      RECT 72.996 1252.608 73.020 1252.800 ;
    END
  END q[355]
  PIN q[356]
    DIRECTION OUTPUT ;
    USE SIGNAL ;
    SHAPE ABUTMENT ;
    PORT
      LAYER M5 ;
      RECT 73.188 1252.608 73.212 1252.800 ;
    END
  END q[356]
  PIN q[357]
    DIRECTION OUTPUT ;
    USE SIGNAL ;
    SHAPE ABUTMENT ;
    PORT
      LAYER M5 ;
      RECT 73.380 1252.608 73.404 1252.800 ;
    END
  END q[357]
  PIN q[358]
    DIRECTION OUTPUT ;
    USE SIGNAL ;
    SHAPE ABUTMENT ;
    PORT
      LAYER M5 ;
      RECT 73.572 1252.608 73.596 1252.800 ;
    END
  END q[358]
  PIN q[359]
    DIRECTION OUTPUT ;
    USE SIGNAL ;
    SHAPE ABUTMENT ;
    PORT
      LAYER M5 ;
      RECT 73.764 1252.608 73.788 1252.800 ;
    END
  END q[359]
  PIN q[360]
    DIRECTION OUTPUT ;
    USE SIGNAL ;
    SHAPE ABUTMENT ;
    PORT
      LAYER M5 ;
      RECT 73.956 1252.608 73.980 1252.800 ;
    END
  END q[360]
  PIN q[361]
    DIRECTION OUTPUT ;
    USE SIGNAL ;
    SHAPE ABUTMENT ;
    PORT
      LAYER M5 ;
      RECT 74.148 1252.608 74.172 1252.800 ;
    END
  END q[361]
  PIN q[362]
    DIRECTION OUTPUT ;
    USE SIGNAL ;
    SHAPE ABUTMENT ;
    PORT
      LAYER M5 ;
      RECT 74.340 1252.608 74.364 1252.800 ;
    END
  END q[362]
  PIN q[363]
    DIRECTION OUTPUT ;
    USE SIGNAL ;
    SHAPE ABUTMENT ;
    PORT
      LAYER M5 ;
      RECT 74.532 1252.608 74.556 1252.800 ;
    END
  END q[363]
  PIN q[364]
    DIRECTION OUTPUT ;
    USE SIGNAL ;
    SHAPE ABUTMENT ;
    PORT
      LAYER M5 ;
      RECT 74.724 1252.608 74.748 1252.800 ;
    END
  END q[364]
  PIN q[365]
    DIRECTION OUTPUT ;
    USE SIGNAL ;
    SHAPE ABUTMENT ;
    PORT
      LAYER M5 ;
      RECT 74.916 1252.608 74.940 1252.800 ;
    END
  END q[365]
  PIN q[366]
    DIRECTION OUTPUT ;
    USE SIGNAL ;
    SHAPE ABUTMENT ;
    PORT
      LAYER M5 ;
      RECT 75.108 1252.608 75.132 1252.800 ;
    END
  END q[366]
  PIN q[367]
    DIRECTION OUTPUT ;
    USE SIGNAL ;
    SHAPE ABUTMENT ;
    PORT
      LAYER M5 ;
      RECT 75.300 1252.608 75.324 1252.800 ;
    END
  END q[367]
  PIN q[368]
    DIRECTION OUTPUT ;
    USE SIGNAL ;
    SHAPE ABUTMENT ;
    PORT
      LAYER M5 ;
      RECT 75.492 1252.608 75.516 1252.800 ;
    END
  END q[368]
  PIN q[369]
    DIRECTION OUTPUT ;
    USE SIGNAL ;
    SHAPE ABUTMENT ;
    PORT
      LAYER M5 ;
      RECT 75.684 1252.608 75.708 1252.800 ;
    END
  END q[369]
  PIN q[370]
    DIRECTION OUTPUT ;
    USE SIGNAL ;
    SHAPE ABUTMENT ;
    PORT
      LAYER M5 ;
      RECT 75.876 1252.608 75.900 1252.800 ;
    END
  END q[370]
  PIN q[371]
    DIRECTION OUTPUT ;
    USE SIGNAL ;
    SHAPE ABUTMENT ;
    PORT
      LAYER M5 ;
      RECT 76.068 1252.608 76.092 1252.800 ;
    END
  END q[371]
  PIN q[372]
    DIRECTION OUTPUT ;
    USE SIGNAL ;
    SHAPE ABUTMENT ;
    PORT
      LAYER M5 ;
      RECT 76.260 1252.608 76.284 1252.800 ;
    END
  END q[372]
  PIN q[373]
    DIRECTION OUTPUT ;
    USE SIGNAL ;
    SHAPE ABUTMENT ;
    PORT
      LAYER M5 ;
      RECT 76.452 1252.608 76.476 1252.800 ;
    END
  END q[373]
  PIN q[374]
    DIRECTION OUTPUT ;
    USE SIGNAL ;
    SHAPE ABUTMENT ;
    PORT
      LAYER M5 ;
      RECT 76.644 1252.608 76.668 1252.800 ;
    END
  END q[374]
  PIN q[375]
    DIRECTION OUTPUT ;
    USE SIGNAL ;
    SHAPE ABUTMENT ;
    PORT
      LAYER M5 ;
      RECT 76.836 1252.608 76.860 1252.800 ;
    END
  END q[375]
  PIN q[376]
    DIRECTION OUTPUT ;
    USE SIGNAL ;
    SHAPE ABUTMENT ;
    PORT
      LAYER M5 ;
      RECT 77.028 1252.608 77.052 1252.800 ;
    END
  END q[376]
  PIN q[377]
    DIRECTION OUTPUT ;
    USE SIGNAL ;
    SHAPE ABUTMENT ;
    PORT
      LAYER M5 ;
      RECT 77.220 1252.608 77.244 1252.800 ;
    END
  END q[377]
  PIN q[378]
    DIRECTION OUTPUT ;
    USE SIGNAL ;
    SHAPE ABUTMENT ;
    PORT
      LAYER M5 ;
      RECT 77.412 1252.608 77.436 1252.800 ;
    END
  END q[378]
  PIN q[379]
    DIRECTION OUTPUT ;
    USE SIGNAL ;
    SHAPE ABUTMENT ;
    PORT
      LAYER M5 ;
      RECT 77.604 1252.608 77.628 1252.800 ;
    END
  END q[379]
  PIN q[380]
    DIRECTION OUTPUT ;
    USE SIGNAL ;
    SHAPE ABUTMENT ;
    PORT
      LAYER M5 ;
      RECT 77.796 1252.608 77.820 1252.800 ;
    END
  END q[380]
  PIN q[381]
    DIRECTION OUTPUT ;
    USE SIGNAL ;
    SHAPE ABUTMENT ;
    PORT
      LAYER M5 ;
      RECT 77.988 1252.608 78.012 1252.800 ;
    END
  END q[381]
  PIN q[382]
    DIRECTION OUTPUT ;
    USE SIGNAL ;
    SHAPE ABUTMENT ;
    PORT
      LAYER M5 ;
      RECT 78.180 1252.608 78.204 1252.800 ;
    END
  END q[382]
  PIN q[383]
    DIRECTION OUTPUT ;
    USE SIGNAL ;
    SHAPE ABUTMENT ;
    PORT
      LAYER M5 ;
      RECT 78.372 1252.608 78.396 1252.800 ;
    END
  END q[383]
  PIN q[384]
    DIRECTION OUTPUT ;
    USE SIGNAL ;
    SHAPE ABUTMENT ;
    PORT
      LAYER M5 ;
      RECT 78.564 1252.608 78.588 1252.800 ;
    END
  END q[384]
  PIN q[385]
    DIRECTION OUTPUT ;
    USE SIGNAL ;
    SHAPE ABUTMENT ;
    PORT
      LAYER M5 ;
      RECT 78.756 1252.608 78.780 1252.800 ;
    END
  END q[385]
  PIN q[386]
    DIRECTION OUTPUT ;
    USE SIGNAL ;
    SHAPE ABUTMENT ;
    PORT
      LAYER M5 ;
      RECT 78.948 1252.608 78.972 1252.800 ;
    END
  END q[386]
  PIN q[387]
    DIRECTION OUTPUT ;
    USE SIGNAL ;
    SHAPE ABUTMENT ;
    PORT
      LAYER M5 ;
      RECT 79.140 1252.608 79.164 1252.800 ;
    END
  END q[387]
  PIN q[388]
    DIRECTION OUTPUT ;
    USE SIGNAL ;
    SHAPE ABUTMENT ;
    PORT
      LAYER M5 ;
      RECT 79.332 1252.608 79.356 1252.800 ;
    END
  END q[388]
  PIN q[389]
    DIRECTION OUTPUT ;
    USE SIGNAL ;
    SHAPE ABUTMENT ;
    PORT
      LAYER M5 ;
      RECT 79.524 1252.608 79.548 1252.800 ;
    END
  END q[389]
  PIN q[390]
    DIRECTION OUTPUT ;
    USE SIGNAL ;
    SHAPE ABUTMENT ;
    PORT
      LAYER M5 ;
      RECT 79.716 1252.608 79.740 1252.800 ;
    END
  END q[390]
  PIN q[391]
    DIRECTION OUTPUT ;
    USE SIGNAL ;
    SHAPE ABUTMENT ;
    PORT
      LAYER M5 ;
      RECT 79.908 1252.608 79.932 1252.800 ;
    END
  END q[391]
  PIN q[392]
    DIRECTION OUTPUT ;
    USE SIGNAL ;
    SHAPE ABUTMENT ;
    PORT
      LAYER M5 ;
      RECT 80.100 1252.608 80.124 1252.800 ;
    END
  END q[392]
  PIN q[393]
    DIRECTION OUTPUT ;
    USE SIGNAL ;
    SHAPE ABUTMENT ;
    PORT
      LAYER M5 ;
      RECT 80.292 1252.608 80.316 1252.800 ;
    END
  END q[393]
  PIN q[394]
    DIRECTION OUTPUT ;
    USE SIGNAL ;
    SHAPE ABUTMENT ;
    PORT
      LAYER M5 ;
      RECT 80.484 1252.608 80.508 1252.800 ;
    END
  END q[394]
  PIN q[395]
    DIRECTION OUTPUT ;
    USE SIGNAL ;
    SHAPE ABUTMENT ;
    PORT
      LAYER M5 ;
      RECT 80.676 1252.608 80.700 1252.800 ;
    END
  END q[395]
  PIN q[396]
    DIRECTION OUTPUT ;
    USE SIGNAL ;
    SHAPE ABUTMENT ;
    PORT
      LAYER M5 ;
      RECT 80.868 1252.608 80.892 1252.800 ;
    END
  END q[396]
  PIN q[397]
    DIRECTION OUTPUT ;
    USE SIGNAL ;
    SHAPE ABUTMENT ;
    PORT
      LAYER M5 ;
      RECT 81.060 1252.608 81.084 1252.800 ;
    END
  END q[397]
  PIN q[398]
    DIRECTION OUTPUT ;
    USE SIGNAL ;
    SHAPE ABUTMENT ;
    PORT
      LAYER M5 ;
      RECT 81.252 1252.608 81.276 1252.800 ;
    END
  END q[398]
  PIN q[399]
    DIRECTION OUTPUT ;
    USE SIGNAL ;
    SHAPE ABUTMENT ;
    PORT
      LAYER M5 ;
      RECT 81.444 1252.608 81.468 1252.800 ;
    END
  END q[399]
  PIN q[400]
    DIRECTION OUTPUT ;
    USE SIGNAL ;
    SHAPE ABUTMENT ;
    PORT
      LAYER M5 ;
      RECT 81.636 1252.608 81.660 1252.800 ;
    END
  END q[400]
  PIN q[401]
    DIRECTION OUTPUT ;
    USE SIGNAL ;
    SHAPE ABUTMENT ;
    PORT
      LAYER M5 ;
      RECT 81.828 1252.608 81.852 1252.800 ;
    END
  END q[401]
  PIN q[402]
    DIRECTION OUTPUT ;
    USE SIGNAL ;
    SHAPE ABUTMENT ;
    PORT
      LAYER M5 ;
      RECT 82.020 1252.608 82.044 1252.800 ;
    END
  END q[402]
  PIN q[403]
    DIRECTION OUTPUT ;
    USE SIGNAL ;
    SHAPE ABUTMENT ;
    PORT
      LAYER M5 ;
      RECT 82.212 1252.608 82.236 1252.800 ;
    END
  END q[403]
  PIN q[404]
    DIRECTION OUTPUT ;
    USE SIGNAL ;
    SHAPE ABUTMENT ;
    PORT
      LAYER M5 ;
      RECT 82.404 1252.608 82.428 1252.800 ;
    END
  END q[404]
  PIN q[405]
    DIRECTION OUTPUT ;
    USE SIGNAL ;
    SHAPE ABUTMENT ;
    PORT
      LAYER M5 ;
      RECT 82.596 1252.608 82.620 1252.800 ;
    END
  END q[405]
  PIN q[406]
    DIRECTION OUTPUT ;
    USE SIGNAL ;
    SHAPE ABUTMENT ;
    PORT
      LAYER M5 ;
      RECT 82.788 1252.608 82.812 1252.800 ;
    END
  END q[406]
  PIN q[407]
    DIRECTION OUTPUT ;
    USE SIGNAL ;
    SHAPE ABUTMENT ;
    PORT
      LAYER M5 ;
      RECT 82.980 1252.608 83.004 1252.800 ;
    END
  END q[407]
  PIN q[408]
    DIRECTION OUTPUT ;
    USE SIGNAL ;
    SHAPE ABUTMENT ;
    PORT
      LAYER M5 ;
      RECT 83.172 1252.608 83.196 1252.800 ;
    END
  END q[408]
  PIN q[409]
    DIRECTION OUTPUT ;
    USE SIGNAL ;
    SHAPE ABUTMENT ;
    PORT
      LAYER M5 ;
      RECT 83.364 1252.608 83.388 1252.800 ;
    END
  END q[409]
  PIN q[410]
    DIRECTION OUTPUT ;
    USE SIGNAL ;
    SHAPE ABUTMENT ;
    PORT
      LAYER M5 ;
      RECT 83.556 1252.608 83.580 1252.800 ;
    END
  END q[410]
  PIN q[411]
    DIRECTION OUTPUT ;
    USE SIGNAL ;
    SHAPE ABUTMENT ;
    PORT
      LAYER M5 ;
      RECT 83.748 1252.608 83.772 1252.800 ;
    END
  END q[411]
  PIN q[412]
    DIRECTION OUTPUT ;
    USE SIGNAL ;
    SHAPE ABUTMENT ;
    PORT
      LAYER M5 ;
      RECT 83.940 1252.608 83.964 1252.800 ;
    END
  END q[412]
  PIN q[413]
    DIRECTION OUTPUT ;
    USE SIGNAL ;
    SHAPE ABUTMENT ;
    PORT
      LAYER M5 ;
      RECT 84.132 1252.608 84.156 1252.800 ;
    END
  END q[413]
  PIN q[414]
    DIRECTION OUTPUT ;
    USE SIGNAL ;
    SHAPE ABUTMENT ;
    PORT
      LAYER M5 ;
      RECT 84.324 1252.608 84.348 1252.800 ;
    END
  END q[414]
  PIN q[415]
    DIRECTION OUTPUT ;
    USE SIGNAL ;
    SHAPE ABUTMENT ;
    PORT
      LAYER M5 ;
      RECT 84.516 1252.608 84.540 1252.800 ;
    END
  END q[415]
  PIN q[416]
    DIRECTION OUTPUT ;
    USE SIGNAL ;
    SHAPE ABUTMENT ;
    PORT
      LAYER M5 ;
      RECT 84.708 1252.608 84.732 1252.800 ;
    END
  END q[416]
  PIN q[417]
    DIRECTION OUTPUT ;
    USE SIGNAL ;
    SHAPE ABUTMENT ;
    PORT
      LAYER M5 ;
      RECT 84.900 1252.608 84.924 1252.800 ;
    END
  END q[417]
  PIN q[418]
    DIRECTION OUTPUT ;
    USE SIGNAL ;
    SHAPE ABUTMENT ;
    PORT
      LAYER M5 ;
      RECT 85.092 1252.608 85.116 1252.800 ;
    END
  END q[418]
  PIN q[419]
    DIRECTION OUTPUT ;
    USE SIGNAL ;
    SHAPE ABUTMENT ;
    PORT
      LAYER M5 ;
      RECT 85.284 1252.608 85.308 1252.800 ;
    END
  END q[419]
  PIN q[420]
    DIRECTION OUTPUT ;
    USE SIGNAL ;
    SHAPE ABUTMENT ;
    PORT
      LAYER M5 ;
      RECT 85.476 1252.608 85.500 1252.800 ;
    END
  END q[420]
  PIN q[421]
    DIRECTION OUTPUT ;
    USE SIGNAL ;
    SHAPE ABUTMENT ;
    PORT
      LAYER M5 ;
      RECT 85.668 1252.608 85.692 1252.800 ;
    END
  END q[421]
  PIN q[422]
    DIRECTION OUTPUT ;
    USE SIGNAL ;
    SHAPE ABUTMENT ;
    PORT
      LAYER M5 ;
      RECT 85.860 1252.608 85.884 1252.800 ;
    END
  END q[422]
  PIN q[423]
    DIRECTION OUTPUT ;
    USE SIGNAL ;
    SHAPE ABUTMENT ;
    PORT
      LAYER M5 ;
      RECT 86.052 1252.608 86.076 1252.800 ;
    END
  END q[423]
  PIN q[424]
    DIRECTION OUTPUT ;
    USE SIGNAL ;
    SHAPE ABUTMENT ;
    PORT
      LAYER M5 ;
      RECT 86.244 1252.608 86.268 1252.800 ;
    END
  END q[424]
  PIN q[425]
    DIRECTION OUTPUT ;
    USE SIGNAL ;
    SHAPE ABUTMENT ;
    PORT
      LAYER M5 ;
      RECT 86.436 1252.608 86.460 1252.800 ;
    END
  END q[425]
  PIN q[426]
    DIRECTION OUTPUT ;
    USE SIGNAL ;
    SHAPE ABUTMENT ;
    PORT
      LAYER M5 ;
      RECT 86.628 1252.608 86.652 1252.800 ;
    END
  END q[426]
  PIN q[427]
    DIRECTION OUTPUT ;
    USE SIGNAL ;
    SHAPE ABUTMENT ;
    PORT
      LAYER M5 ;
      RECT 86.820 1252.608 86.844 1252.800 ;
    END
  END q[427]
  PIN q[428]
    DIRECTION OUTPUT ;
    USE SIGNAL ;
    SHAPE ABUTMENT ;
    PORT
      LAYER M5 ;
      RECT 87.012 1252.608 87.036 1252.800 ;
    END
  END q[428]
  PIN q[429]
    DIRECTION OUTPUT ;
    USE SIGNAL ;
    SHAPE ABUTMENT ;
    PORT
      LAYER M5 ;
      RECT 87.204 1252.608 87.228 1252.800 ;
    END
  END q[429]
  PIN q[430]
    DIRECTION OUTPUT ;
    USE SIGNAL ;
    SHAPE ABUTMENT ;
    PORT
      LAYER M5 ;
      RECT 87.396 1252.608 87.420 1252.800 ;
    END
  END q[430]
  PIN q[431]
    DIRECTION OUTPUT ;
    USE SIGNAL ;
    SHAPE ABUTMENT ;
    PORT
      LAYER M5 ;
      RECT 87.588 1252.608 87.612 1252.800 ;
    END
  END q[431]
  PIN q[432]
    DIRECTION OUTPUT ;
    USE SIGNAL ;
    SHAPE ABUTMENT ;
    PORT
      LAYER M5 ;
      RECT 87.780 1252.608 87.804 1252.800 ;
    END
  END q[432]
  PIN q[433]
    DIRECTION OUTPUT ;
    USE SIGNAL ;
    SHAPE ABUTMENT ;
    PORT
      LAYER M5 ;
      RECT 87.972 1252.608 87.996 1252.800 ;
    END
  END q[433]
  PIN q[434]
    DIRECTION OUTPUT ;
    USE SIGNAL ;
    SHAPE ABUTMENT ;
    PORT
      LAYER M5 ;
      RECT 88.164 1252.608 88.188 1252.800 ;
    END
  END q[434]
  PIN q[435]
    DIRECTION OUTPUT ;
    USE SIGNAL ;
    SHAPE ABUTMENT ;
    PORT
      LAYER M5 ;
      RECT 88.356 1252.608 88.380 1252.800 ;
    END
  END q[435]
  PIN q[436]
    DIRECTION OUTPUT ;
    USE SIGNAL ;
    SHAPE ABUTMENT ;
    PORT
      LAYER M5 ;
      RECT 88.548 1252.608 88.572 1252.800 ;
    END
  END q[436]
  PIN q[437]
    DIRECTION OUTPUT ;
    USE SIGNAL ;
    SHAPE ABUTMENT ;
    PORT
      LAYER M5 ;
      RECT 88.740 1252.608 88.764 1252.800 ;
    END
  END q[437]
  PIN q[438]
    DIRECTION OUTPUT ;
    USE SIGNAL ;
    SHAPE ABUTMENT ;
    PORT
      LAYER M5 ;
      RECT 88.932 1252.608 88.956 1252.800 ;
    END
  END q[438]
  PIN q[439]
    DIRECTION OUTPUT ;
    USE SIGNAL ;
    SHAPE ABUTMENT ;
    PORT
      LAYER M5 ;
      RECT 89.124 1252.608 89.148 1252.800 ;
    END
  END q[439]
  PIN q[440]
    DIRECTION OUTPUT ;
    USE SIGNAL ;
    SHAPE ABUTMENT ;
    PORT
      LAYER M5 ;
      RECT 89.316 1252.608 89.340 1252.800 ;
    END
  END q[440]
  PIN q[441]
    DIRECTION OUTPUT ;
    USE SIGNAL ;
    SHAPE ABUTMENT ;
    PORT
      LAYER M5 ;
      RECT 89.508 1252.608 89.532 1252.800 ;
    END
  END q[441]
  PIN q[442]
    DIRECTION OUTPUT ;
    USE SIGNAL ;
    SHAPE ABUTMENT ;
    PORT
      LAYER M5 ;
      RECT 89.700 1252.608 89.724 1252.800 ;
    END
  END q[442]
  PIN q[443]
    DIRECTION OUTPUT ;
    USE SIGNAL ;
    SHAPE ABUTMENT ;
    PORT
      LAYER M5 ;
      RECT 89.892 1252.608 89.916 1252.800 ;
    END
  END q[443]
  PIN q[444]
    DIRECTION OUTPUT ;
    USE SIGNAL ;
    SHAPE ABUTMENT ;
    PORT
      LAYER M5 ;
      RECT 90.084 1252.608 90.108 1252.800 ;
    END
  END q[444]
  PIN q[445]
    DIRECTION OUTPUT ;
    USE SIGNAL ;
    SHAPE ABUTMENT ;
    PORT
      LAYER M5 ;
      RECT 90.276 1252.608 90.300 1252.800 ;
    END
  END q[445]
  PIN q[446]
    DIRECTION OUTPUT ;
    USE SIGNAL ;
    SHAPE ABUTMENT ;
    PORT
      LAYER M5 ;
      RECT 90.468 1252.608 90.492 1252.800 ;
    END
  END q[446]
  PIN q[447]
    DIRECTION OUTPUT ;
    USE SIGNAL ;
    SHAPE ABUTMENT ;
    PORT
      LAYER M5 ;
      RECT 90.660 1252.608 90.684 1252.800 ;
    END
  END q[447]
  PIN q[448]
    DIRECTION OUTPUT ;
    USE SIGNAL ;
    SHAPE ABUTMENT ;
    PORT
      LAYER M5 ;
      RECT 90.852 1252.608 90.876 1252.800 ;
    END
  END q[448]
  PIN q[449]
    DIRECTION OUTPUT ;
    USE SIGNAL ;
    SHAPE ABUTMENT ;
    PORT
      LAYER M5 ;
      RECT 91.044 1252.608 91.068 1252.800 ;
    END
  END q[449]
  PIN q[450]
    DIRECTION OUTPUT ;
    USE SIGNAL ;
    SHAPE ABUTMENT ;
    PORT
      LAYER M5 ;
      RECT 91.236 1252.608 91.260 1252.800 ;
    END
  END q[450]
  PIN q[451]
    DIRECTION OUTPUT ;
    USE SIGNAL ;
    SHAPE ABUTMENT ;
    PORT
      LAYER M5 ;
      RECT 91.428 1252.608 91.452 1252.800 ;
    END
  END q[451]
  PIN q[452]
    DIRECTION OUTPUT ;
    USE SIGNAL ;
    SHAPE ABUTMENT ;
    PORT
      LAYER M5 ;
      RECT 91.620 1252.608 91.644 1252.800 ;
    END
  END q[452]
  PIN q[453]
    DIRECTION OUTPUT ;
    USE SIGNAL ;
    SHAPE ABUTMENT ;
    PORT
      LAYER M5 ;
      RECT 91.812 1252.608 91.836 1252.800 ;
    END
  END q[453]
  PIN q[454]
    DIRECTION OUTPUT ;
    USE SIGNAL ;
    SHAPE ABUTMENT ;
    PORT
      LAYER M5 ;
      RECT 92.004 1252.608 92.028 1252.800 ;
    END
  END q[454]
  PIN q[455]
    DIRECTION OUTPUT ;
    USE SIGNAL ;
    SHAPE ABUTMENT ;
    PORT
      LAYER M5 ;
      RECT 92.196 1252.608 92.220 1252.800 ;
    END
  END q[455]
  PIN q[456]
    DIRECTION OUTPUT ;
    USE SIGNAL ;
    SHAPE ABUTMENT ;
    PORT
      LAYER M5 ;
      RECT 92.388 1252.608 92.412 1252.800 ;
    END
  END q[456]
  PIN q[457]
    DIRECTION OUTPUT ;
    USE SIGNAL ;
    SHAPE ABUTMENT ;
    PORT
      LAYER M5 ;
      RECT 92.580 1252.608 92.604 1252.800 ;
    END
  END q[457]
  PIN q[458]
    DIRECTION OUTPUT ;
    USE SIGNAL ;
    SHAPE ABUTMENT ;
    PORT
      LAYER M5 ;
      RECT 92.772 1252.608 92.796 1252.800 ;
    END
  END q[458]
  PIN q[459]
    DIRECTION OUTPUT ;
    USE SIGNAL ;
    SHAPE ABUTMENT ;
    PORT
      LAYER M5 ;
      RECT 92.964 1252.608 92.988 1252.800 ;
    END
  END q[459]
  PIN q[460]
    DIRECTION OUTPUT ;
    USE SIGNAL ;
    SHAPE ABUTMENT ;
    PORT
      LAYER M5 ;
      RECT 93.156 1252.608 93.180 1252.800 ;
    END
  END q[460]
  PIN q[461]
    DIRECTION OUTPUT ;
    USE SIGNAL ;
    SHAPE ABUTMENT ;
    PORT
      LAYER M5 ;
      RECT 93.348 1252.608 93.372 1252.800 ;
    END
  END q[461]
  PIN q[462]
    DIRECTION OUTPUT ;
    USE SIGNAL ;
    SHAPE ABUTMENT ;
    PORT
      LAYER M5 ;
      RECT 93.540 1252.608 93.564 1252.800 ;
    END
  END q[462]
  PIN q[463]
    DIRECTION OUTPUT ;
    USE SIGNAL ;
    SHAPE ABUTMENT ;
    PORT
      LAYER M5 ;
      RECT 93.732 1252.608 93.756 1252.800 ;
    END
  END q[463]
  PIN q[464]
    DIRECTION OUTPUT ;
    USE SIGNAL ;
    SHAPE ABUTMENT ;
    PORT
      LAYER M5 ;
      RECT 93.924 1252.608 93.948 1252.800 ;
    END
  END q[464]
  PIN q[465]
    DIRECTION OUTPUT ;
    USE SIGNAL ;
    SHAPE ABUTMENT ;
    PORT
      LAYER M5 ;
      RECT 94.116 1252.608 94.140 1252.800 ;
    END
  END q[465]
  PIN q[466]
    DIRECTION OUTPUT ;
    USE SIGNAL ;
    SHAPE ABUTMENT ;
    PORT
      LAYER M5 ;
      RECT 94.308 1252.608 94.332 1252.800 ;
    END
  END q[466]
  PIN q[467]
    DIRECTION OUTPUT ;
    USE SIGNAL ;
    SHAPE ABUTMENT ;
    PORT
      LAYER M5 ;
      RECT 94.500 1252.608 94.524 1252.800 ;
    END
  END q[467]
  PIN q[468]
    DIRECTION OUTPUT ;
    USE SIGNAL ;
    SHAPE ABUTMENT ;
    PORT
      LAYER M5 ;
      RECT 94.692 1252.608 94.716 1252.800 ;
    END
  END q[468]
  PIN q[469]
    DIRECTION OUTPUT ;
    USE SIGNAL ;
    SHAPE ABUTMENT ;
    PORT
      LAYER M5 ;
      RECT 94.884 1252.608 94.908 1252.800 ;
    END
  END q[469]
  PIN q[470]
    DIRECTION OUTPUT ;
    USE SIGNAL ;
    SHAPE ABUTMENT ;
    PORT
      LAYER M5 ;
      RECT 95.076 1252.608 95.100 1252.800 ;
    END
  END q[470]
  PIN q[471]
    DIRECTION OUTPUT ;
    USE SIGNAL ;
    SHAPE ABUTMENT ;
    PORT
      LAYER M5 ;
      RECT 95.268 1252.608 95.292 1252.800 ;
    END
  END q[471]
  PIN q[472]
    DIRECTION OUTPUT ;
    USE SIGNAL ;
    SHAPE ABUTMENT ;
    PORT
      LAYER M5 ;
      RECT 95.460 1252.608 95.484 1252.800 ;
    END
  END q[472]
  PIN q[473]
    DIRECTION OUTPUT ;
    USE SIGNAL ;
    SHAPE ABUTMENT ;
    PORT
      LAYER M5 ;
      RECT 95.652 1252.608 95.676 1252.800 ;
    END
  END q[473]
  PIN q[474]
    DIRECTION OUTPUT ;
    USE SIGNAL ;
    SHAPE ABUTMENT ;
    PORT
      LAYER M5 ;
      RECT 95.844 1252.608 95.868 1252.800 ;
    END
  END q[474]
  PIN q[475]
    DIRECTION OUTPUT ;
    USE SIGNAL ;
    SHAPE ABUTMENT ;
    PORT
      LAYER M5 ;
      RECT 96.036 1252.608 96.060 1252.800 ;
    END
  END q[475]
  PIN q[476]
    DIRECTION OUTPUT ;
    USE SIGNAL ;
    SHAPE ABUTMENT ;
    PORT
      LAYER M5 ;
      RECT 96.228 1252.608 96.252 1252.800 ;
    END
  END q[476]
  PIN q[477]
    DIRECTION OUTPUT ;
    USE SIGNAL ;
    SHAPE ABUTMENT ;
    PORT
      LAYER M5 ;
      RECT 96.420 1252.608 96.444 1252.800 ;
    END
  END q[477]
  PIN q[478]
    DIRECTION OUTPUT ;
    USE SIGNAL ;
    SHAPE ABUTMENT ;
    PORT
      LAYER M5 ;
      RECT 96.612 1252.608 96.636 1252.800 ;
    END
  END q[478]
  PIN q[479]
    DIRECTION OUTPUT ;
    USE SIGNAL ;
    SHAPE ABUTMENT ;
    PORT
      LAYER M5 ;
      RECT 96.804 1252.608 96.828 1252.800 ;
    END
  END q[479]
  PIN q[480]
    DIRECTION OUTPUT ;
    USE SIGNAL ;
    SHAPE ABUTMENT ;
    PORT
      LAYER M5 ;
      RECT 96.996 1252.608 97.020 1252.800 ;
    END
  END q[480]
  PIN q[481]
    DIRECTION OUTPUT ;
    USE SIGNAL ;
    SHAPE ABUTMENT ;
    PORT
      LAYER M5 ;
      RECT 97.188 1252.608 97.212 1252.800 ;
    END
  END q[481]
  PIN q[482]
    DIRECTION OUTPUT ;
    USE SIGNAL ;
    SHAPE ABUTMENT ;
    PORT
      LAYER M5 ;
      RECT 97.380 1252.608 97.404 1252.800 ;
    END
  END q[482]
  PIN q[483]
    DIRECTION OUTPUT ;
    USE SIGNAL ;
    SHAPE ABUTMENT ;
    PORT
      LAYER M5 ;
      RECT 97.572 1252.608 97.596 1252.800 ;
    END
  END q[483]
  PIN q[484]
    DIRECTION OUTPUT ;
    USE SIGNAL ;
    SHAPE ABUTMENT ;
    PORT
      LAYER M5 ;
      RECT 97.764 1252.608 97.788 1252.800 ;
    END
  END q[484]
  PIN q[485]
    DIRECTION OUTPUT ;
    USE SIGNAL ;
    SHAPE ABUTMENT ;
    PORT
      LAYER M5 ;
      RECT 97.956 1252.608 97.980 1252.800 ;
    END
  END q[485]
  PIN q[486]
    DIRECTION OUTPUT ;
    USE SIGNAL ;
    SHAPE ABUTMENT ;
    PORT
      LAYER M5 ;
      RECT 98.148 1252.608 98.172 1252.800 ;
    END
  END q[486]
  PIN q[487]
    DIRECTION OUTPUT ;
    USE SIGNAL ;
    SHAPE ABUTMENT ;
    PORT
      LAYER M5 ;
      RECT 98.340 1252.608 98.364 1252.800 ;
    END
  END q[487]
  PIN q[488]
    DIRECTION OUTPUT ;
    USE SIGNAL ;
    SHAPE ABUTMENT ;
    PORT
      LAYER M5 ;
      RECT 98.532 1252.608 98.556 1252.800 ;
    END
  END q[488]
  PIN q[489]
    DIRECTION OUTPUT ;
    USE SIGNAL ;
    SHAPE ABUTMENT ;
    PORT
      LAYER M5 ;
      RECT 98.724 1252.608 98.748 1252.800 ;
    END
  END q[489]
  PIN q[490]
    DIRECTION OUTPUT ;
    USE SIGNAL ;
    SHAPE ABUTMENT ;
    PORT
      LAYER M5 ;
      RECT 98.916 1252.608 98.940 1252.800 ;
    END
  END q[490]
  PIN q[491]
    DIRECTION OUTPUT ;
    USE SIGNAL ;
    SHAPE ABUTMENT ;
    PORT
      LAYER M5 ;
      RECT 99.108 1252.608 99.132 1252.800 ;
    END
  END q[491]
  PIN q[492]
    DIRECTION OUTPUT ;
    USE SIGNAL ;
    SHAPE ABUTMENT ;
    PORT
      LAYER M5 ;
      RECT 99.300 1252.608 99.324 1252.800 ;
    END
  END q[492]
  PIN q[493]
    DIRECTION OUTPUT ;
    USE SIGNAL ;
    SHAPE ABUTMENT ;
    PORT
      LAYER M5 ;
      RECT 99.492 1252.608 99.516 1252.800 ;
    END
  END q[493]
  PIN q[494]
    DIRECTION OUTPUT ;
    USE SIGNAL ;
    SHAPE ABUTMENT ;
    PORT
      LAYER M5 ;
      RECT 99.684 1252.608 99.708 1252.800 ;
    END
  END q[494]
  PIN q[495]
    DIRECTION OUTPUT ;
    USE SIGNAL ;
    SHAPE ABUTMENT ;
    PORT
      LAYER M5 ;
      RECT 99.876 1252.608 99.900 1252.800 ;
    END
  END q[495]
  PIN q[496]
    DIRECTION OUTPUT ;
    USE SIGNAL ;
    SHAPE ABUTMENT ;
    PORT
      LAYER M5 ;
      RECT 100.068 1252.608 100.092 1252.800 ;
    END
  END q[496]
  PIN q[497]
    DIRECTION OUTPUT ;
    USE SIGNAL ;
    SHAPE ABUTMENT ;
    PORT
      LAYER M5 ;
      RECT 100.260 1252.608 100.284 1252.800 ;
    END
  END q[497]
  PIN q[498]
    DIRECTION OUTPUT ;
    USE SIGNAL ;
    SHAPE ABUTMENT ;
    PORT
      LAYER M5 ;
      RECT 100.452 1252.608 100.476 1252.800 ;
    END
  END q[498]
  PIN q[499]
    DIRECTION OUTPUT ;
    USE SIGNAL ;
    SHAPE ABUTMENT ;
    PORT
      LAYER M5 ;
      RECT 100.644 1252.608 100.668 1252.800 ;
    END
  END q[499]
  PIN q[500]
    DIRECTION OUTPUT ;
    USE SIGNAL ;
    SHAPE ABUTMENT ;
    PORT
      LAYER M5 ;
      RECT 100.836 1252.608 100.860 1252.800 ;
    END
  END q[500]
  PIN q[501]
    DIRECTION OUTPUT ;
    USE SIGNAL ;
    SHAPE ABUTMENT ;
    PORT
      LAYER M5 ;
      RECT 101.028 1252.608 101.052 1252.800 ;
    END
  END q[501]
  PIN q[502]
    DIRECTION OUTPUT ;
    USE SIGNAL ;
    SHAPE ABUTMENT ;
    PORT
      LAYER M5 ;
      RECT 101.220 1252.608 101.244 1252.800 ;
    END
  END q[502]
  PIN q[503]
    DIRECTION OUTPUT ;
    USE SIGNAL ;
    SHAPE ABUTMENT ;
    PORT
      LAYER M5 ;
      RECT 101.412 1252.608 101.436 1252.800 ;
    END
  END q[503]
  PIN q[504]
    DIRECTION OUTPUT ;
    USE SIGNAL ;
    SHAPE ABUTMENT ;
    PORT
      LAYER M5 ;
      RECT 101.604 1252.608 101.628 1252.800 ;
    END
  END q[504]
  PIN q[505]
    DIRECTION OUTPUT ;
    USE SIGNAL ;
    SHAPE ABUTMENT ;
    PORT
      LAYER M5 ;
      RECT 101.796 1252.608 101.820 1252.800 ;
    END
  END q[505]
  PIN q[506]
    DIRECTION OUTPUT ;
    USE SIGNAL ;
    SHAPE ABUTMENT ;
    PORT
      LAYER M5 ;
      RECT 101.988 1252.608 102.012 1252.800 ;
    END
  END q[506]
  PIN q[507]
    DIRECTION OUTPUT ;
    USE SIGNAL ;
    SHAPE ABUTMENT ;
    PORT
      LAYER M5 ;
      RECT 102.180 1252.608 102.204 1252.800 ;
    END
  END q[507]
  PIN q[508]
    DIRECTION OUTPUT ;
    USE SIGNAL ;
    SHAPE ABUTMENT ;
    PORT
      LAYER M5 ;
      RECT 102.372 1252.608 102.396 1252.800 ;
    END
  END q[508]
  PIN q[509]
    DIRECTION OUTPUT ;
    USE SIGNAL ;
    SHAPE ABUTMENT ;
    PORT
      LAYER M5 ;
      RECT 102.564 1252.608 102.588 1252.800 ;
    END
  END q[509]
  PIN q[510]
    DIRECTION OUTPUT ;
    USE SIGNAL ;
    SHAPE ABUTMENT ;
    PORT
      LAYER M5 ;
      RECT 102.756 1252.608 102.780 1252.800 ;
    END
  END q[510]
  PIN q[511]
    DIRECTION OUTPUT ;
    USE SIGNAL ;
    SHAPE ABUTMENT ;
    PORT
      LAYER M5 ;
      RECT 102.948 1252.608 102.972 1252.800 ;
    END
  END q[511]
  PIN q[512]
    DIRECTION OUTPUT ;
    USE SIGNAL ;
    SHAPE ABUTMENT ;
    PORT
      LAYER M5 ;
      RECT 103.140 1252.608 103.164 1252.800 ;
    END
  END q[512]
  PIN VDD
    DIRECTION INOUT ;
    USE POWER ;
    PORT
      LAYER M5 ;
      RECT 0.300 2.000 0.420 1250.800 ;
      RECT 5.700 2.000 5.820 1250.800 ;
      RECT 11.100 2.000 11.220 1250.800 ;
      RECT 16.500 2.000 16.620 1250.800 ;
      RECT 21.900 2.000 22.020 1250.800 ;
      RECT 27.300 2.000 27.420 1250.800 ;
      RECT 32.700 2.000 32.820 1250.800 ;
      RECT 38.100 2.000 38.220 1250.800 ;
      RECT 43.500 2.000 43.620 1250.800 ;
      RECT 48.900 2.000 49.020 1250.800 ;
      RECT 54.300 2.000 54.420 1250.800 ;
      RECT 59.700 2.000 59.820 1250.800 ;
      RECT 65.100 2.000 65.220 1250.800 ;
      RECT 70.500 2.000 70.620 1250.800 ;
      RECT 75.900 2.000 76.020 1250.800 ;
      RECT 81.300 2.000 81.420 1250.800 ;
      RECT 86.700 2.000 86.820 1250.800 ;
      RECT 92.100 2.000 92.220 1250.800 ;
      RECT 97.500 2.000 97.620 1250.800 ;
      RECT 102.900 2.000 103.020 1250.800 ;
    END
  END VDD
  PIN VSS
    DIRECTION INOUT ;
    USE GROUND ;
    PORT
      LAYER M5 ;
      RECT 0.492 2.000 0.612 1250.800 ;
      RECT 5.892 2.000 6.012 1250.800 ;
      RECT 11.292 2.000 11.412 1250.800 ;
      RECT 16.692 2.000 16.812 1250.800 ;
      RECT 22.092 2.000 22.212 1250.800 ;
      RECT 27.492 2.000 27.612 1250.800 ;
      RECT 32.892 2.000 33.012 1250.800 ;
      RECT 38.292 2.000 38.412 1250.800 ;
      RECT 43.692 2.000 43.812 1250.800 ;
      RECT 49.092 2.000 49.212 1250.800 ;
      RECT 54.492 2.000 54.612 1250.800 ;
      RECT 59.892 2.000 60.012 1250.800 ;
      RECT 65.292 2.000 65.412 1250.800 ;
      RECT 70.692 2.000 70.812 1250.800 ;
      RECT 76.092 2.000 76.212 1250.800 ;
      RECT 81.492 2.000 81.612 1250.800 ;
      RECT 86.892 2.000 87.012 1250.800 ;
      RECT 92.292 2.000 92.412 1250.800 ;
      RECT 97.692 2.000 97.812 1250.800 ;
      RECT 103.092 2.000 103.212 1250.800 ;
    END
  END VSS
  OBS
    LAYER M1 ;
    RECT 0 0 108.000 1252.800 ;
    LAYER M2 ;
    RECT 0 0 108.000 1252.800 ;
    LAYER M3 ;
    RECT 0 0 108.000 1252.800 ;
    LAYER M4 ;
    RECT 0 0 108.000 1252.800 ;
    LAYER M5 ;
    RECT 0.000 0.600 0.228 1252.200 ;
    RECT 0.684 0.600 5.628 1252.200 ;
    RECT 6.084 0.600 11.028 1252.200 ;
    RECT 11.484 0.600 16.428 1252.200 ;
    RECT 16.884 0.600 21.828 1252.200 ;
    RECT 22.284 0.600 27.228 1252.200 ;
    RECT 27.684 0.600 32.628 1252.200 ;
    RECT 33.084 0.600 38.028 1252.200 ;
    RECT 38.484 0.600 43.428 1252.200 ;
    RECT 43.884 0.600 48.828 1252.200 ;
    RECT 49.284 0.600 54.228 1252.200 ;
    RECT 54.684 0.600 59.628 1252.200 ;
    RECT 60.084 0.600 65.028 1252.200 ;
    RECT 65.484 0.600 70.428 1252.200 ;
    RECT 70.884 0.600 75.828 1252.200 ;
    RECT 76.284 0.600 81.228 1252.200 ;
    RECT 81.684 0.600 86.628 1252.200 ;
    RECT 87.084 0.600 92.028 1252.200 ;
    RECT 92.484 0.600 97.428 1252.200 ;
    RECT 97.884 0.600 102.828 1252.200 ;
    RECT 103.284 0.600 108.000 1252.200 ;
    RECT 0.300 0.600 0.420 1.928 ;
    RECT 0.300 1250.872 0.420 1252.200 ;
    RECT 0.492 0.600 0.612 1.928 ;
    RECT 0.492 1250.872 0.612 1252.200 ;
    RECT 5.700 0.600 5.820 1.928 ;
    RECT 5.700 1250.872 5.820 1252.200 ;
    RECT 5.892 0.600 6.012 1.928 ;
    RECT 5.892 1250.872 6.012 1252.200 ;
    RECT 11.100 0.600 11.220 1.928 ;
    RECT 11.100 1250.872 11.220 1252.200 ;
    RECT 11.292 0.600 11.412 1.928 ;
    RECT 11.292 1250.872 11.412 1252.200 ;
    RECT 16.500 0.600 16.620 1.928 ;
    RECT 16.500 1250.872 16.620 1252.200 ;
    RECT 16.692 0.600 16.812 1.928 ;
    RECT 16.692 1250.872 16.812 1252.200 ;
    RECT 21.900 0.600 22.020 1.928 ;
    RECT 21.900 1250.872 22.020 1252.200 ;
    RECT 22.092 0.600 22.212 1.928 ;
    RECT 22.092 1250.872 22.212 1252.200 ;
    RECT 27.300 0.600 27.420 1.928 ;
    RECT 27.300 1250.872 27.420 1252.200 ;
    RECT 27.492 0.600 27.612 1.928 ;
    RECT 27.492 1250.872 27.612 1252.200 ;
    RECT 32.700 0.600 32.820 1.928 ;
    RECT 32.700 1250.872 32.820 1252.200 ;
    RECT 32.892 0.600 33.012 1.928 ;
    RECT 32.892 1250.872 33.012 1252.200 ;
    RECT 38.100 0.600 38.220 1.928 ;
    RECT 38.100 1250.872 38.220 1252.200 ;
    RECT 38.292 0.600 38.412 1.928 ;
    RECT 38.292 1250.872 38.412 1252.200 ;
    RECT 43.500 0.600 43.620 1.928 ;
    RECT 43.500 1250.872 43.620 1252.200 ;
    RECT 43.692 0.600 43.812 1.928 ;
    RECT 43.692 1250.872 43.812 1252.200 ;
    RECT 48.900 0.600 49.020 1.928 ;
    RECT 48.900 1250.872 49.020 1252.200 ;
    RECT 49.092 0.600 49.212 1.928 ;
    RECT 49.092 1250.872 49.212 1252.200 ;
    RECT 54.300 0.600 54.420 1.928 ;
    RECT 54.300 1250.872 54.420 1252.200 ;
    RECT 54.492 0.600 54.612 1.928 ;
    RECT 54.492 1250.872 54.612 1252.200 ;
    RECT 59.700 0.600 59.820 1.928 ;
    RECT 59.700 1250.872 59.820 1252.200 ;
    RECT 59.892 0.600 60.012 1.928 ;
    RECT 59.892 1250.872 60.012 1252.200 ;
    RECT 65.100 0.600 65.220 1.928 ;
    RECT 65.100 1250.872 65.220 1252.200 ;
    RECT 65.292 0.600 65.412 1.928 ;
    RECT 65.292 1250.872 65.412 1252.200 ;
    RECT 70.500 0.600 70.620 1.928 ;
    RECT 70.500 1250.872 70.620 1252.200 ;
    RECT 70.692 0.600 70.812 1.928 ;
    RECT 70.692 1250.872 70.812 1252.200 ;
    RECT 75.900 0.600 76.020 1.928 ;
    RECT 75.900 1250.872 76.020 1252.200 ;
    RECT 76.092 0.600 76.212 1.928 ;
    RECT 76.092 1250.872 76.212 1252.200 ;
    RECT 81.300 0.600 81.420 1.928 ;
    RECT 81.300 1250.872 81.420 1252.200 ;
    RECT 81.492 0.600 81.612 1.928 ;
    RECT 81.492 1250.872 81.612 1252.200 ;
    RECT 86.700 0.600 86.820 1.928 ;
    RECT 86.700 1250.872 86.820 1252.200 ;
    RECT 86.892 0.600 87.012 1.928 ;
    RECT 86.892 1250.872 87.012 1252.200 ;
    RECT 92.100 0.600 92.220 1.928 ;
    RECT 92.100 1250.872 92.220 1252.200 ;
    RECT 92.292 0.600 92.412 1.928 ;
    RECT 92.292 1250.872 92.412 1252.200 ;
    RECT 97.500 0.600 97.620 1.928 ;
    RECT 97.500 1250.872 97.620 1252.200 ;
    RECT 97.692 0.600 97.812 1.928 ;
    RECT 97.692 1250.872 97.812 1252.200 ;
    RECT 102.900 0.600 103.020 1.928 ;
    RECT 102.900 1250.872 103.020 1252.200 ;
    RECT 103.092 0.600 103.212 1.928 ;
    RECT 103.092 1250.872 103.212 1252.200 ;
  END
END ot_ucie_pma_rxm

END LIBRARY
